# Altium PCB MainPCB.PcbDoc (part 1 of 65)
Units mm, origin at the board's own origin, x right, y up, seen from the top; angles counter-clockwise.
Board outline 92.01 x 92.01 mm, 10 copper layers (Top Layer, PowerPlane2, Mid-Layer 1, MidLayer4, PowerPlane1, Mid-Layer 2, SecondaryGND, Mid-Layer 3, GroundPlane, Bottom Layer); 840 components, 219 nets, 3641 pads, 3367 vias.

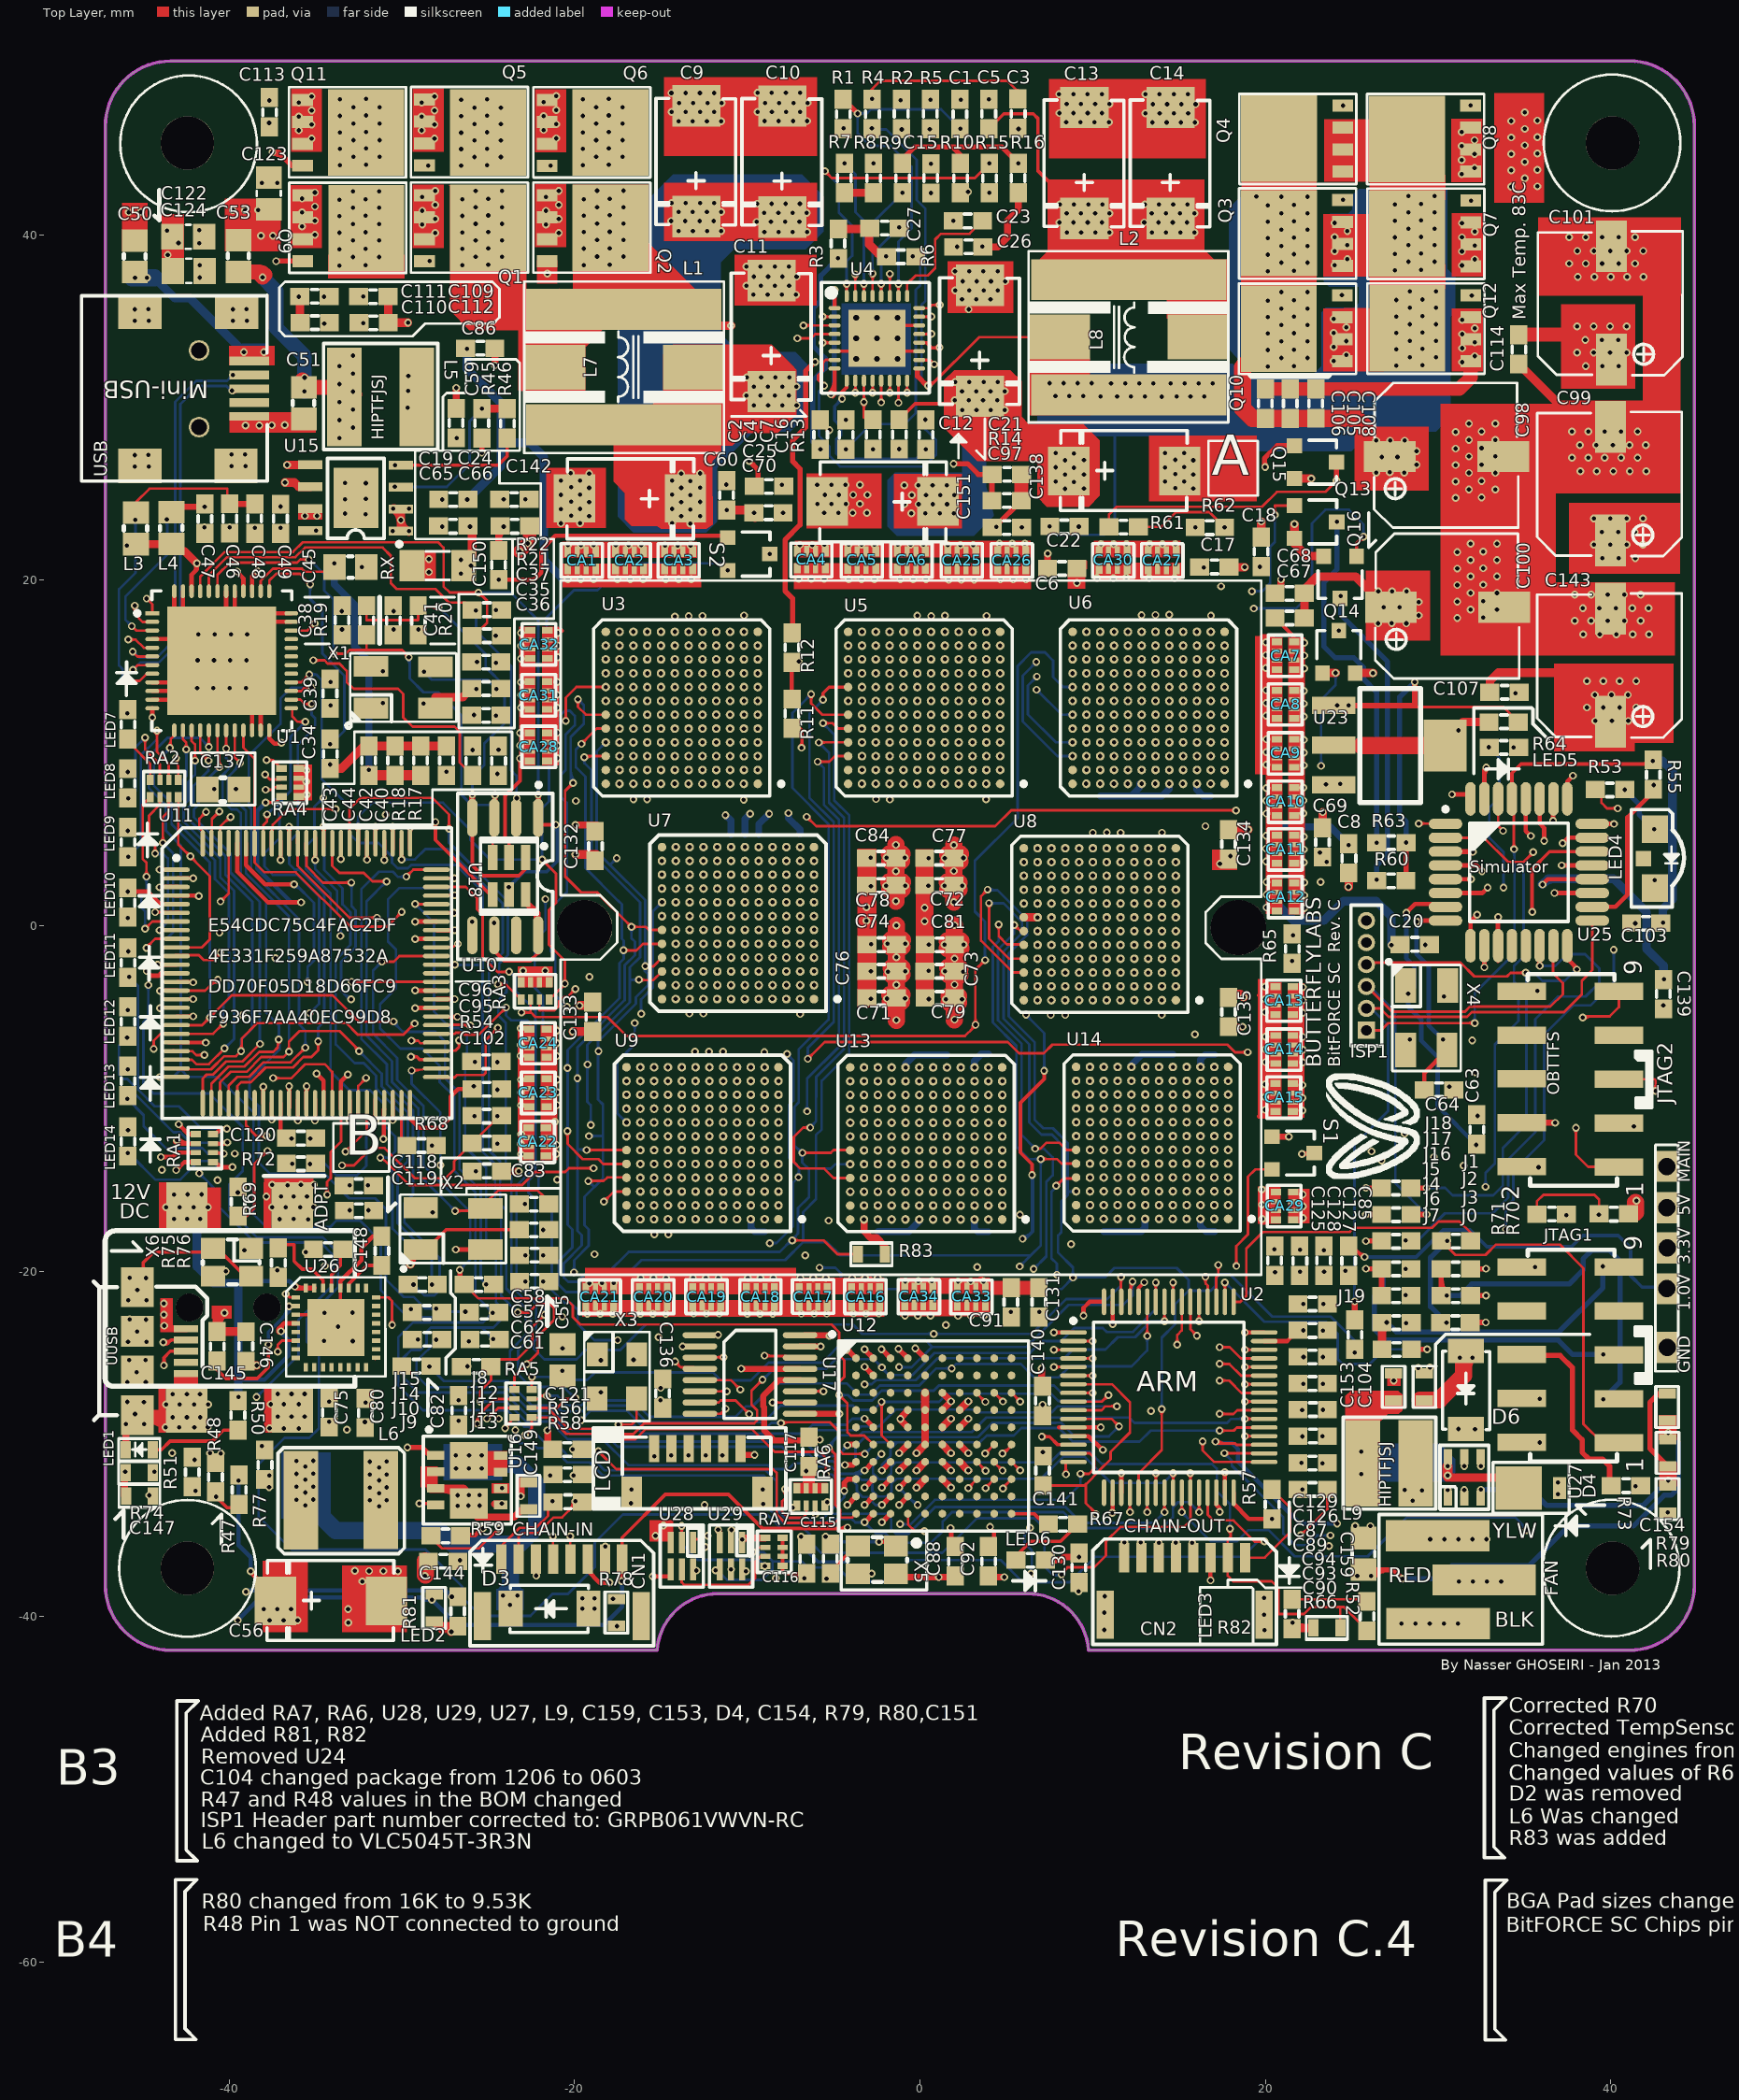
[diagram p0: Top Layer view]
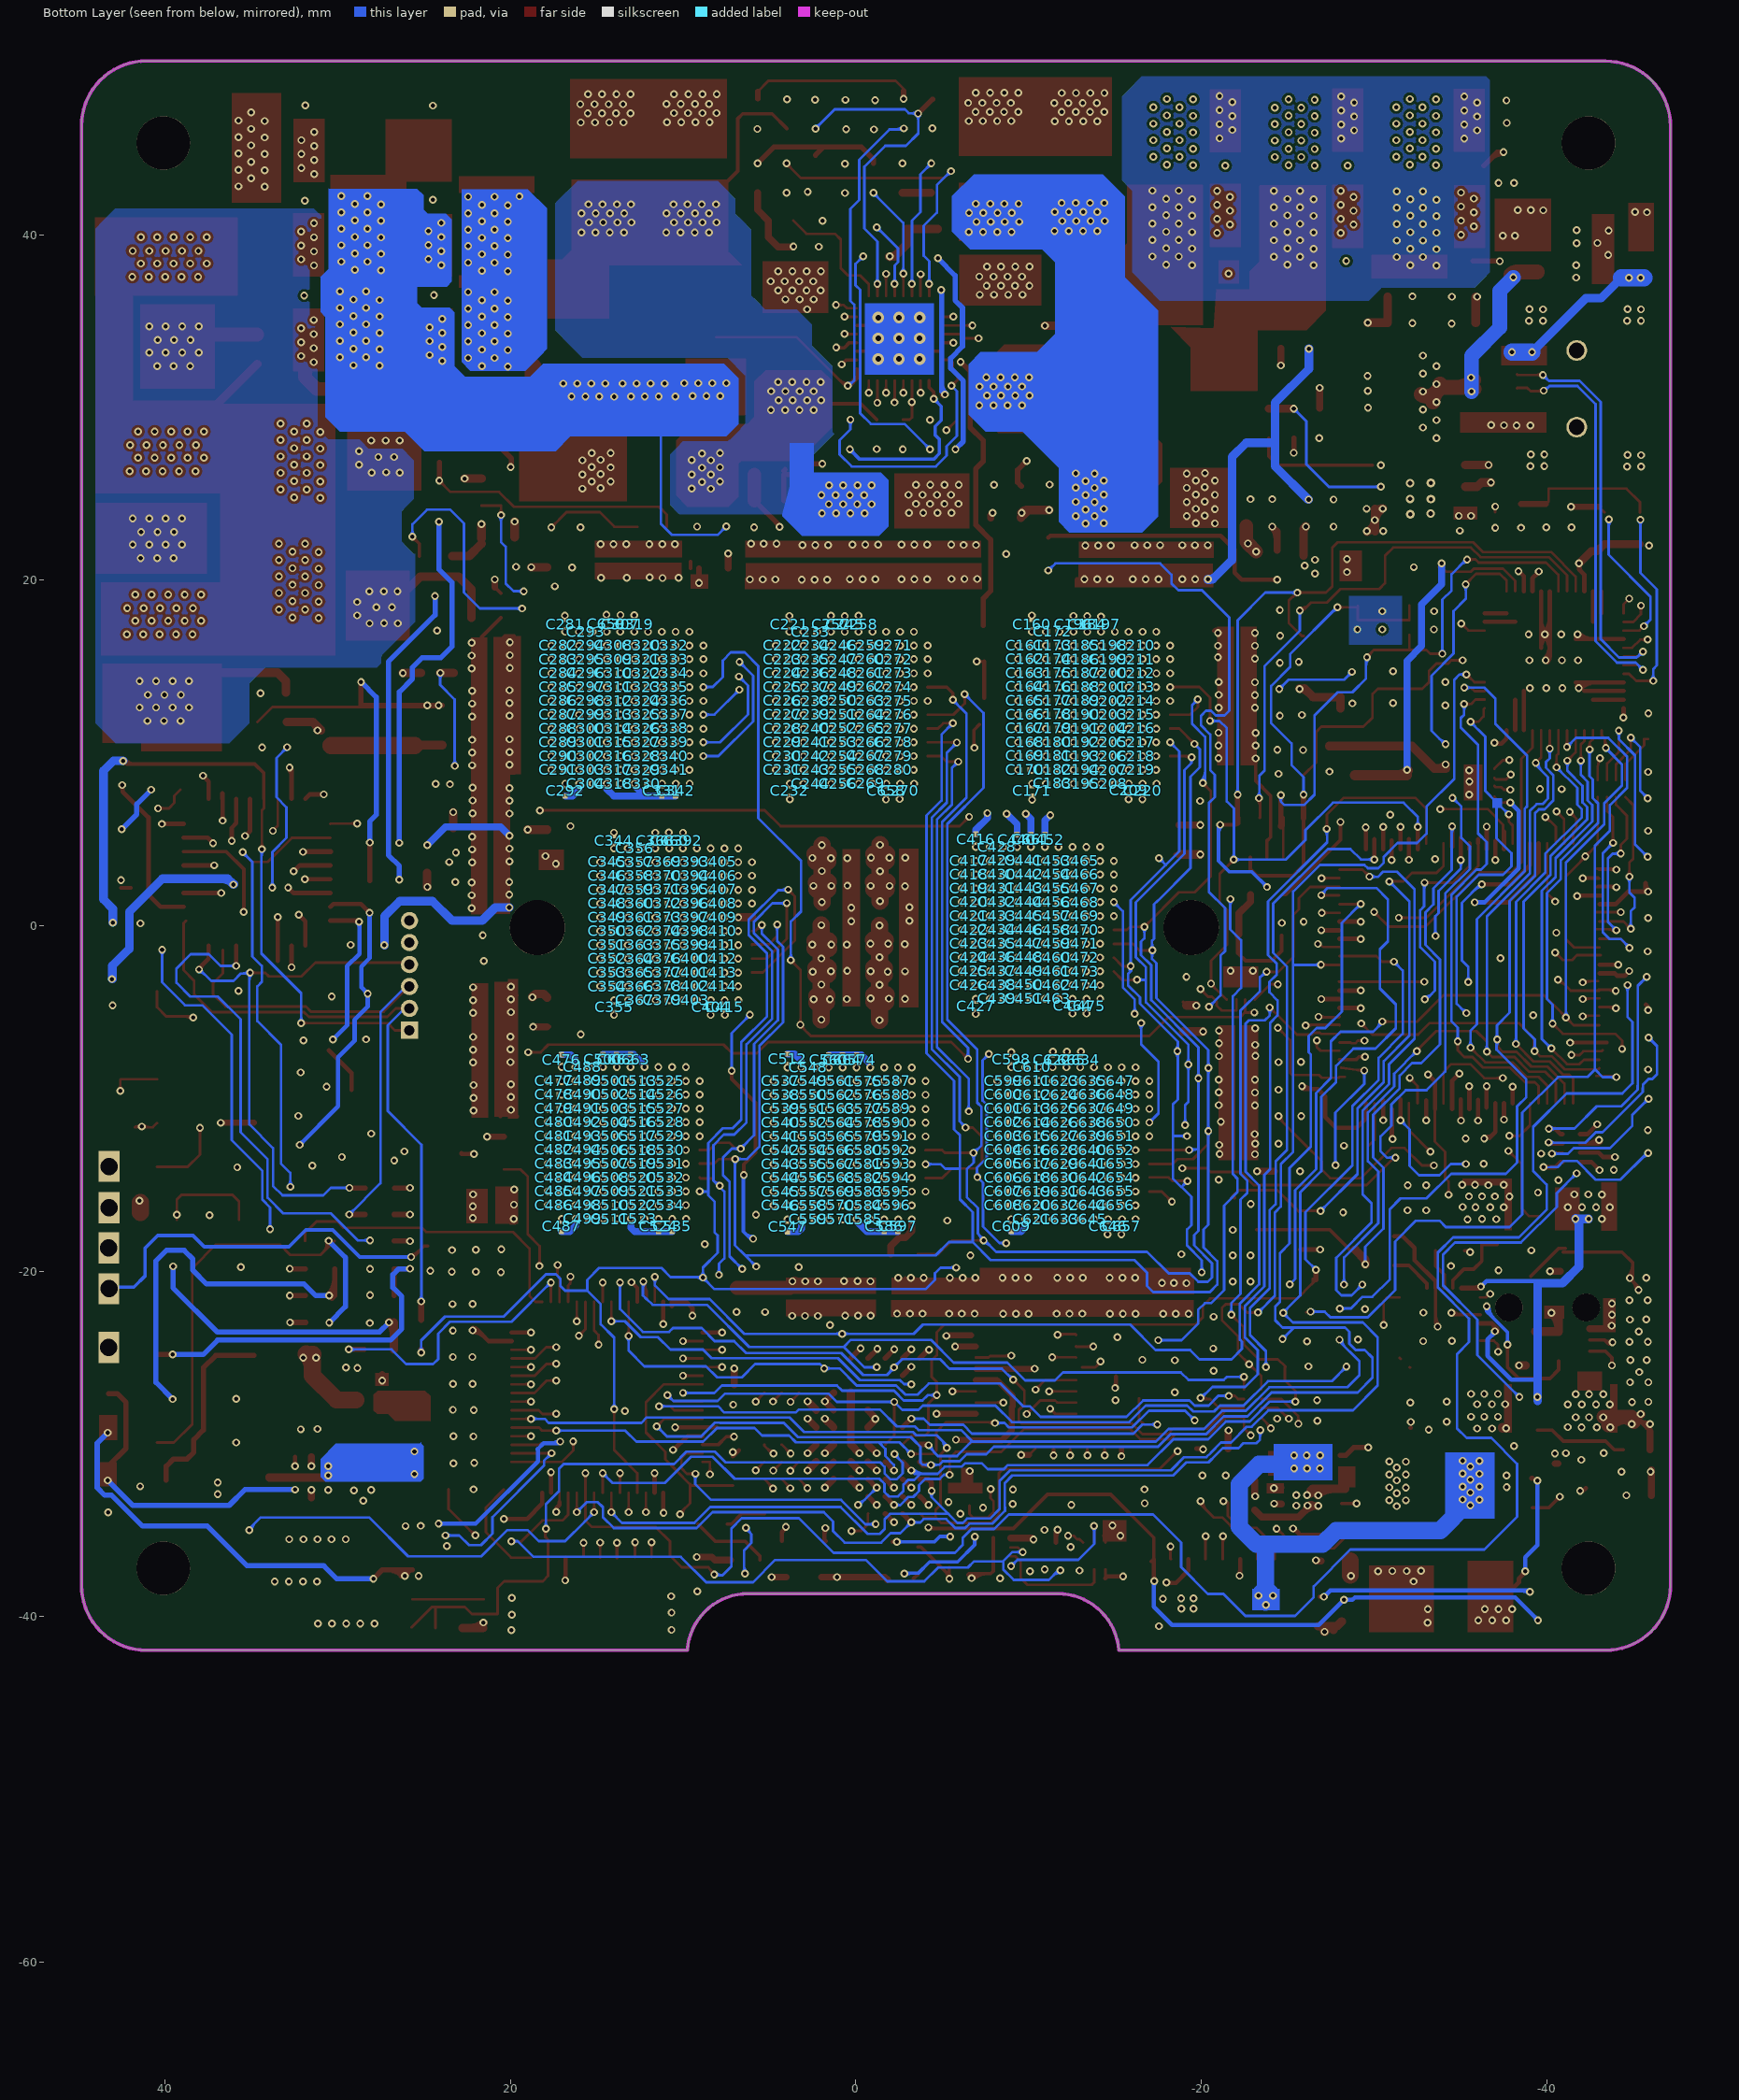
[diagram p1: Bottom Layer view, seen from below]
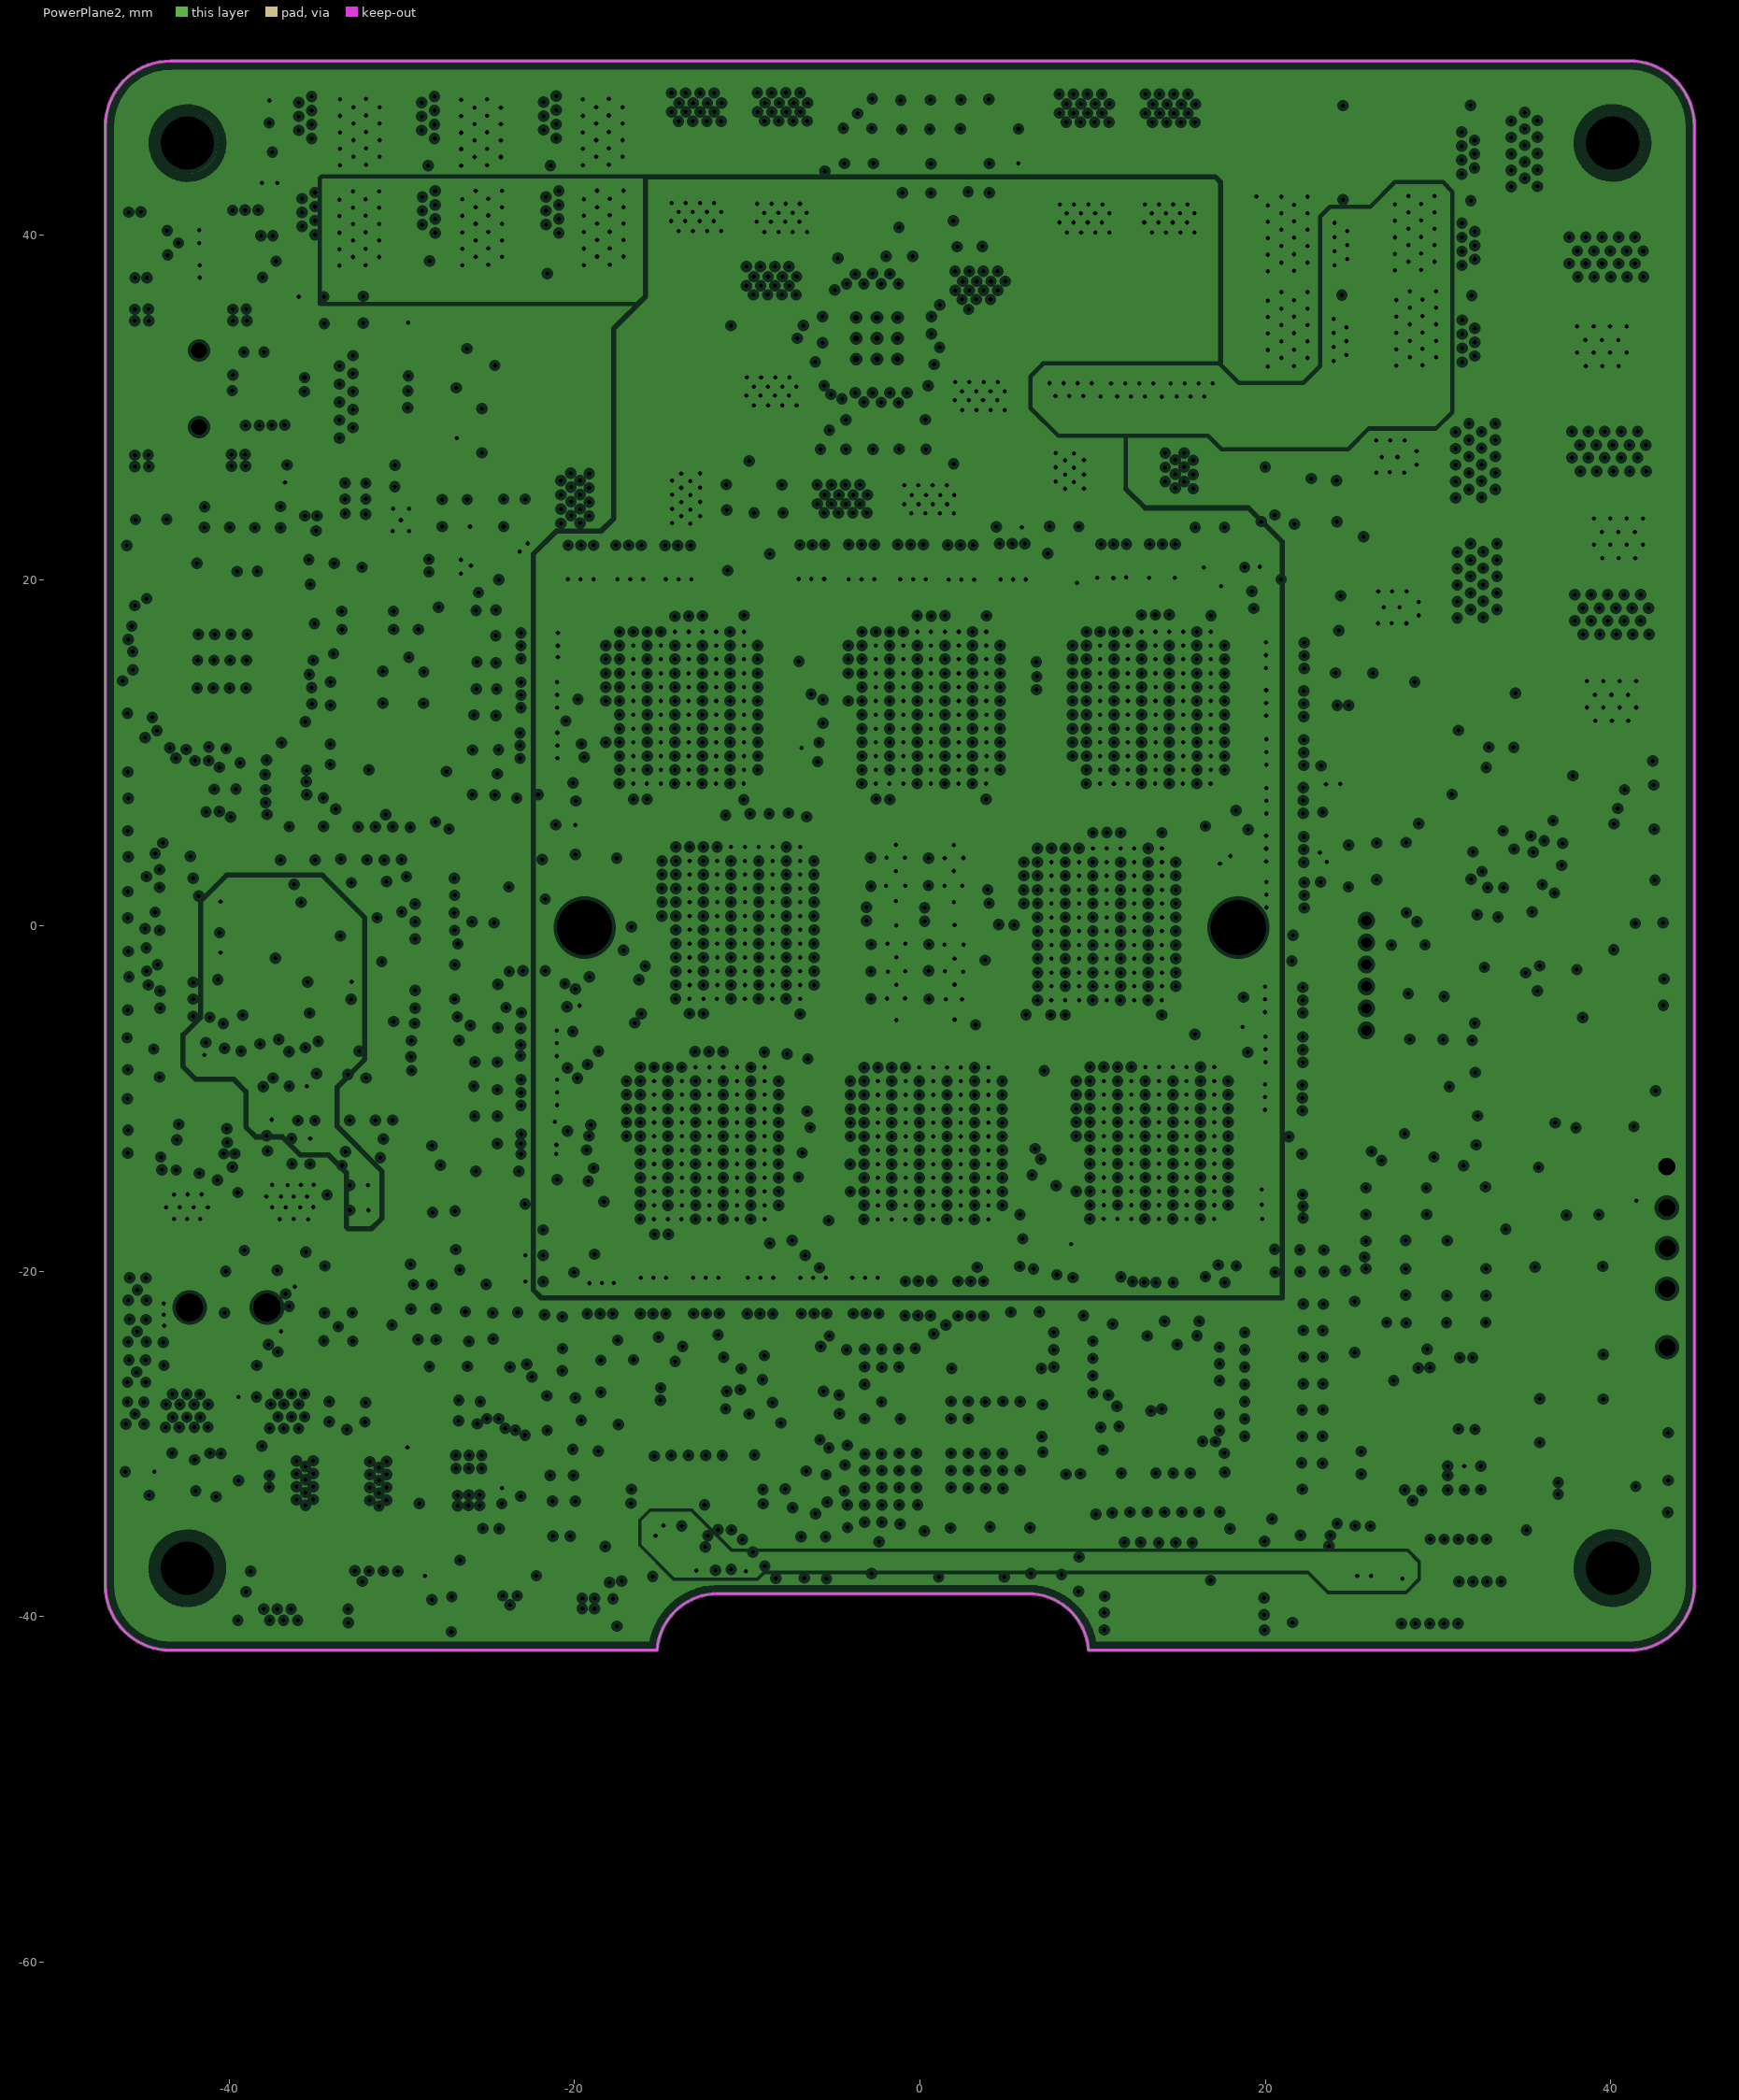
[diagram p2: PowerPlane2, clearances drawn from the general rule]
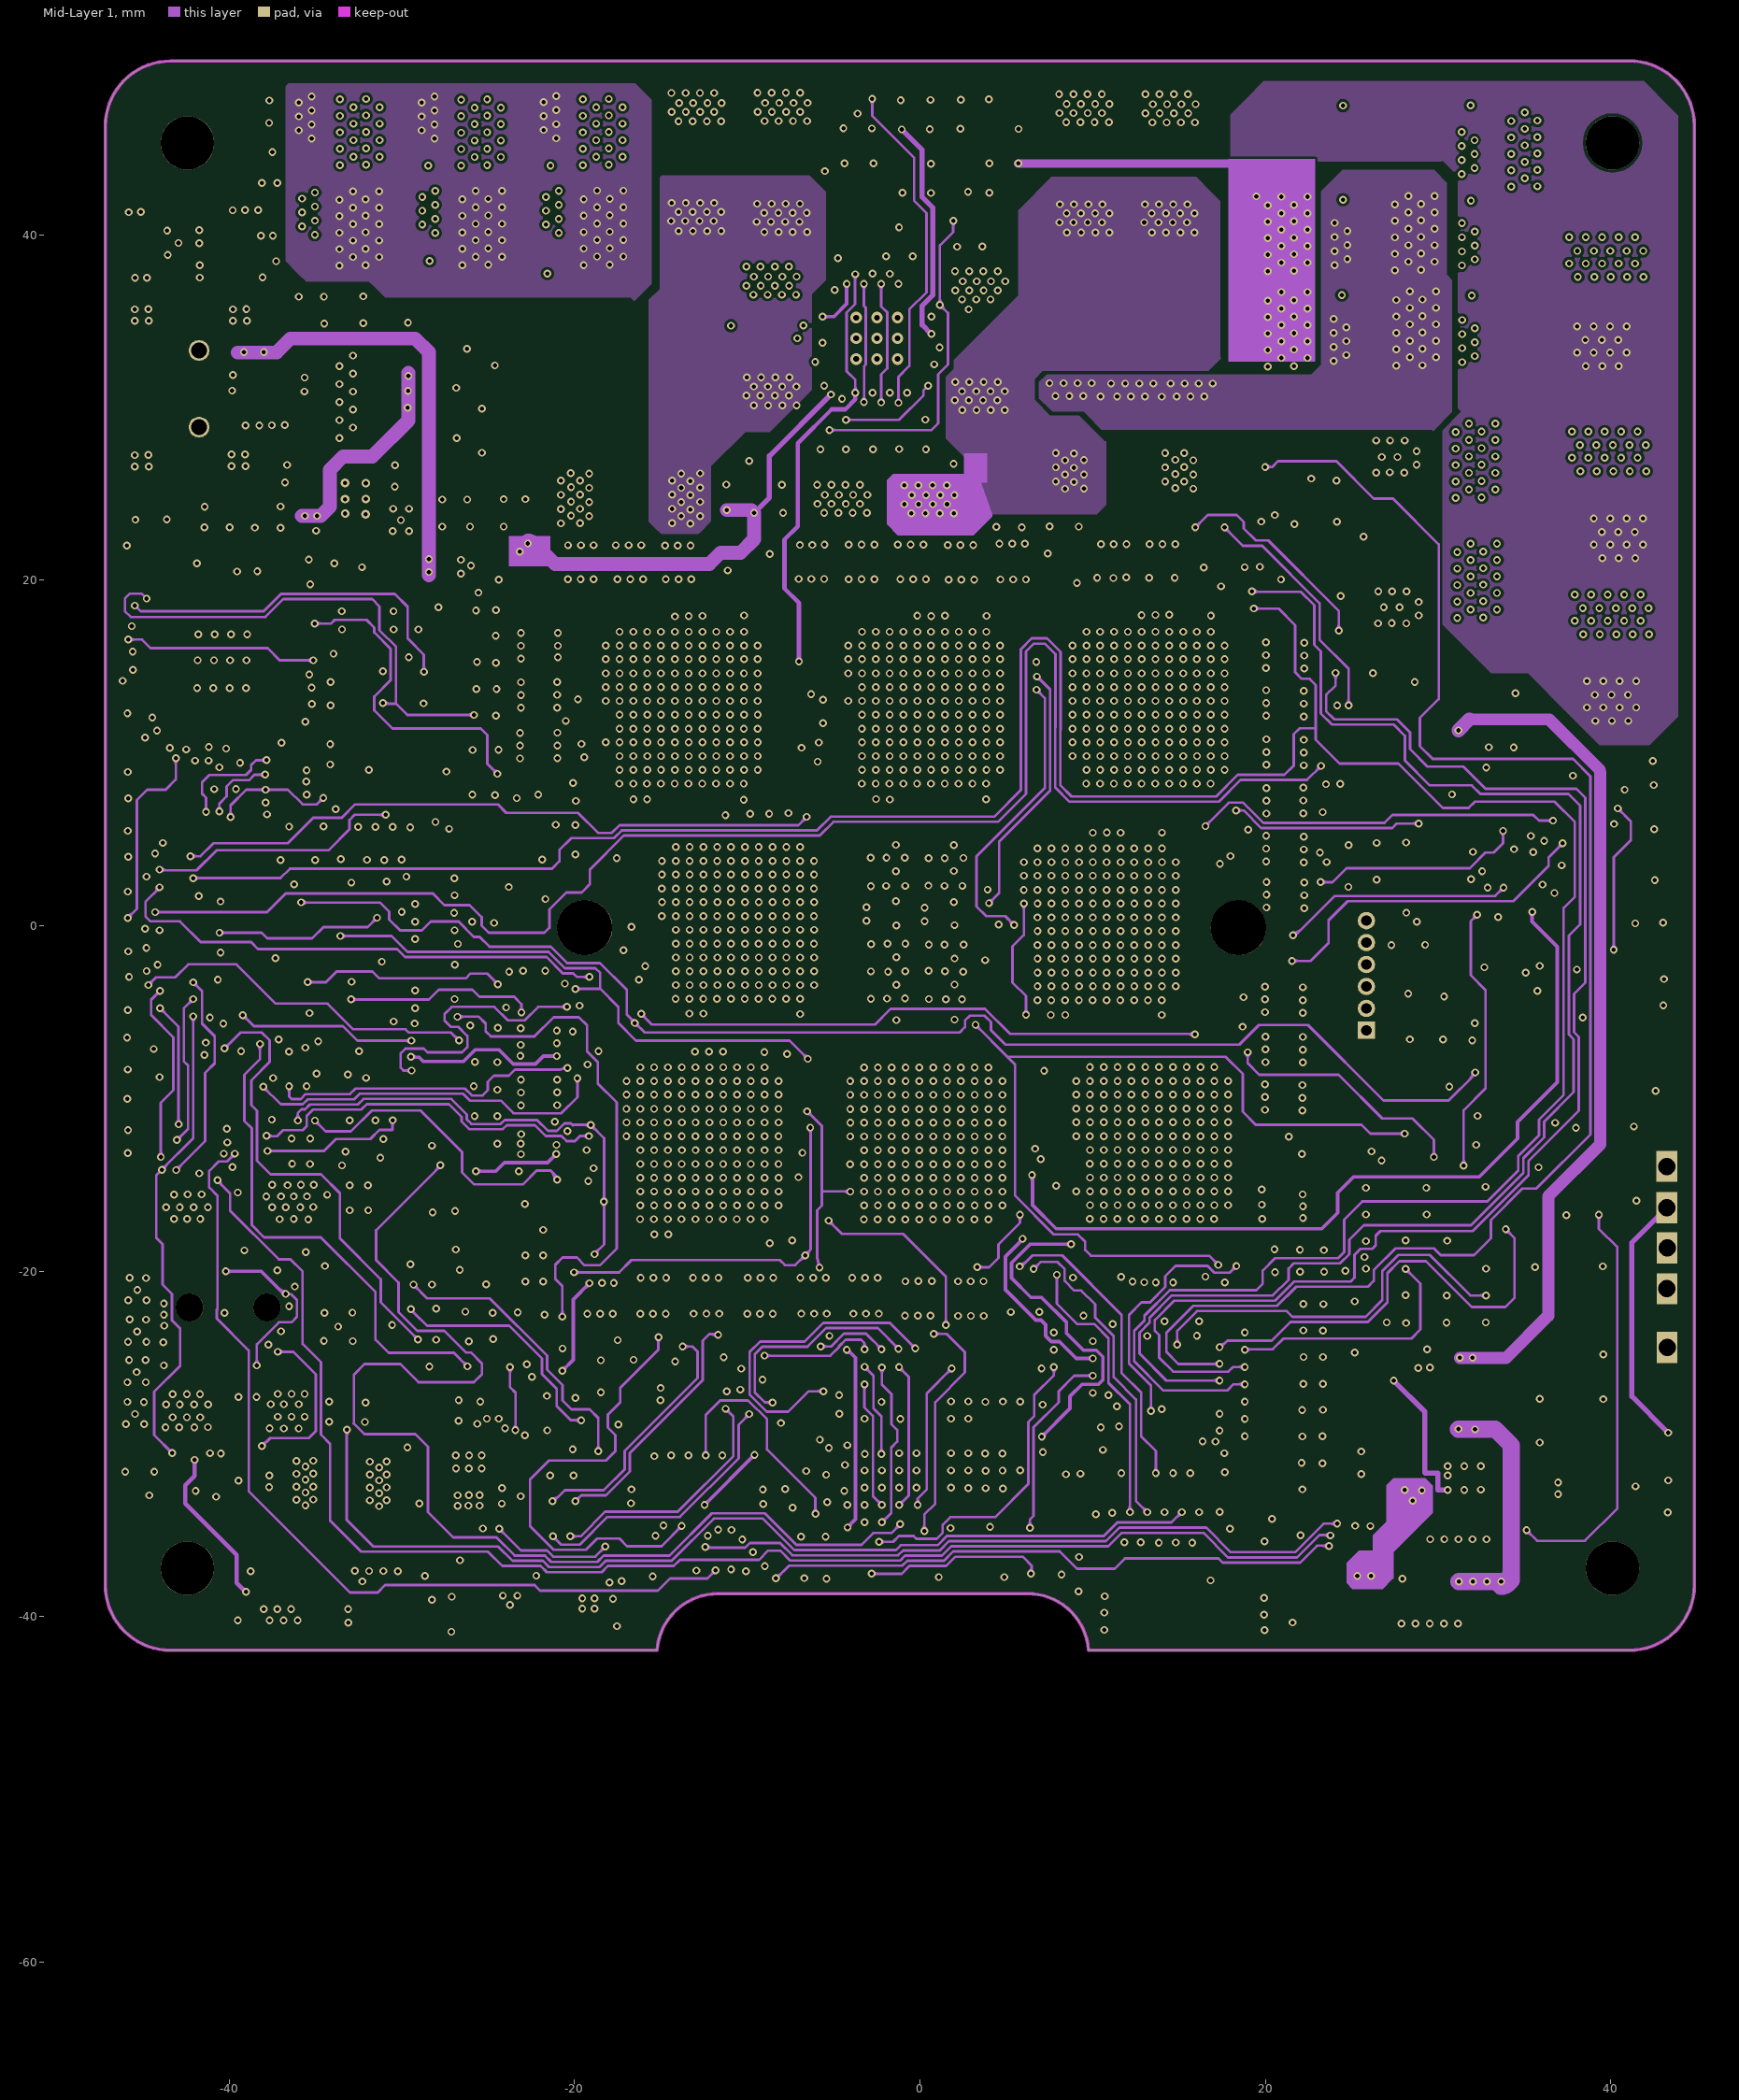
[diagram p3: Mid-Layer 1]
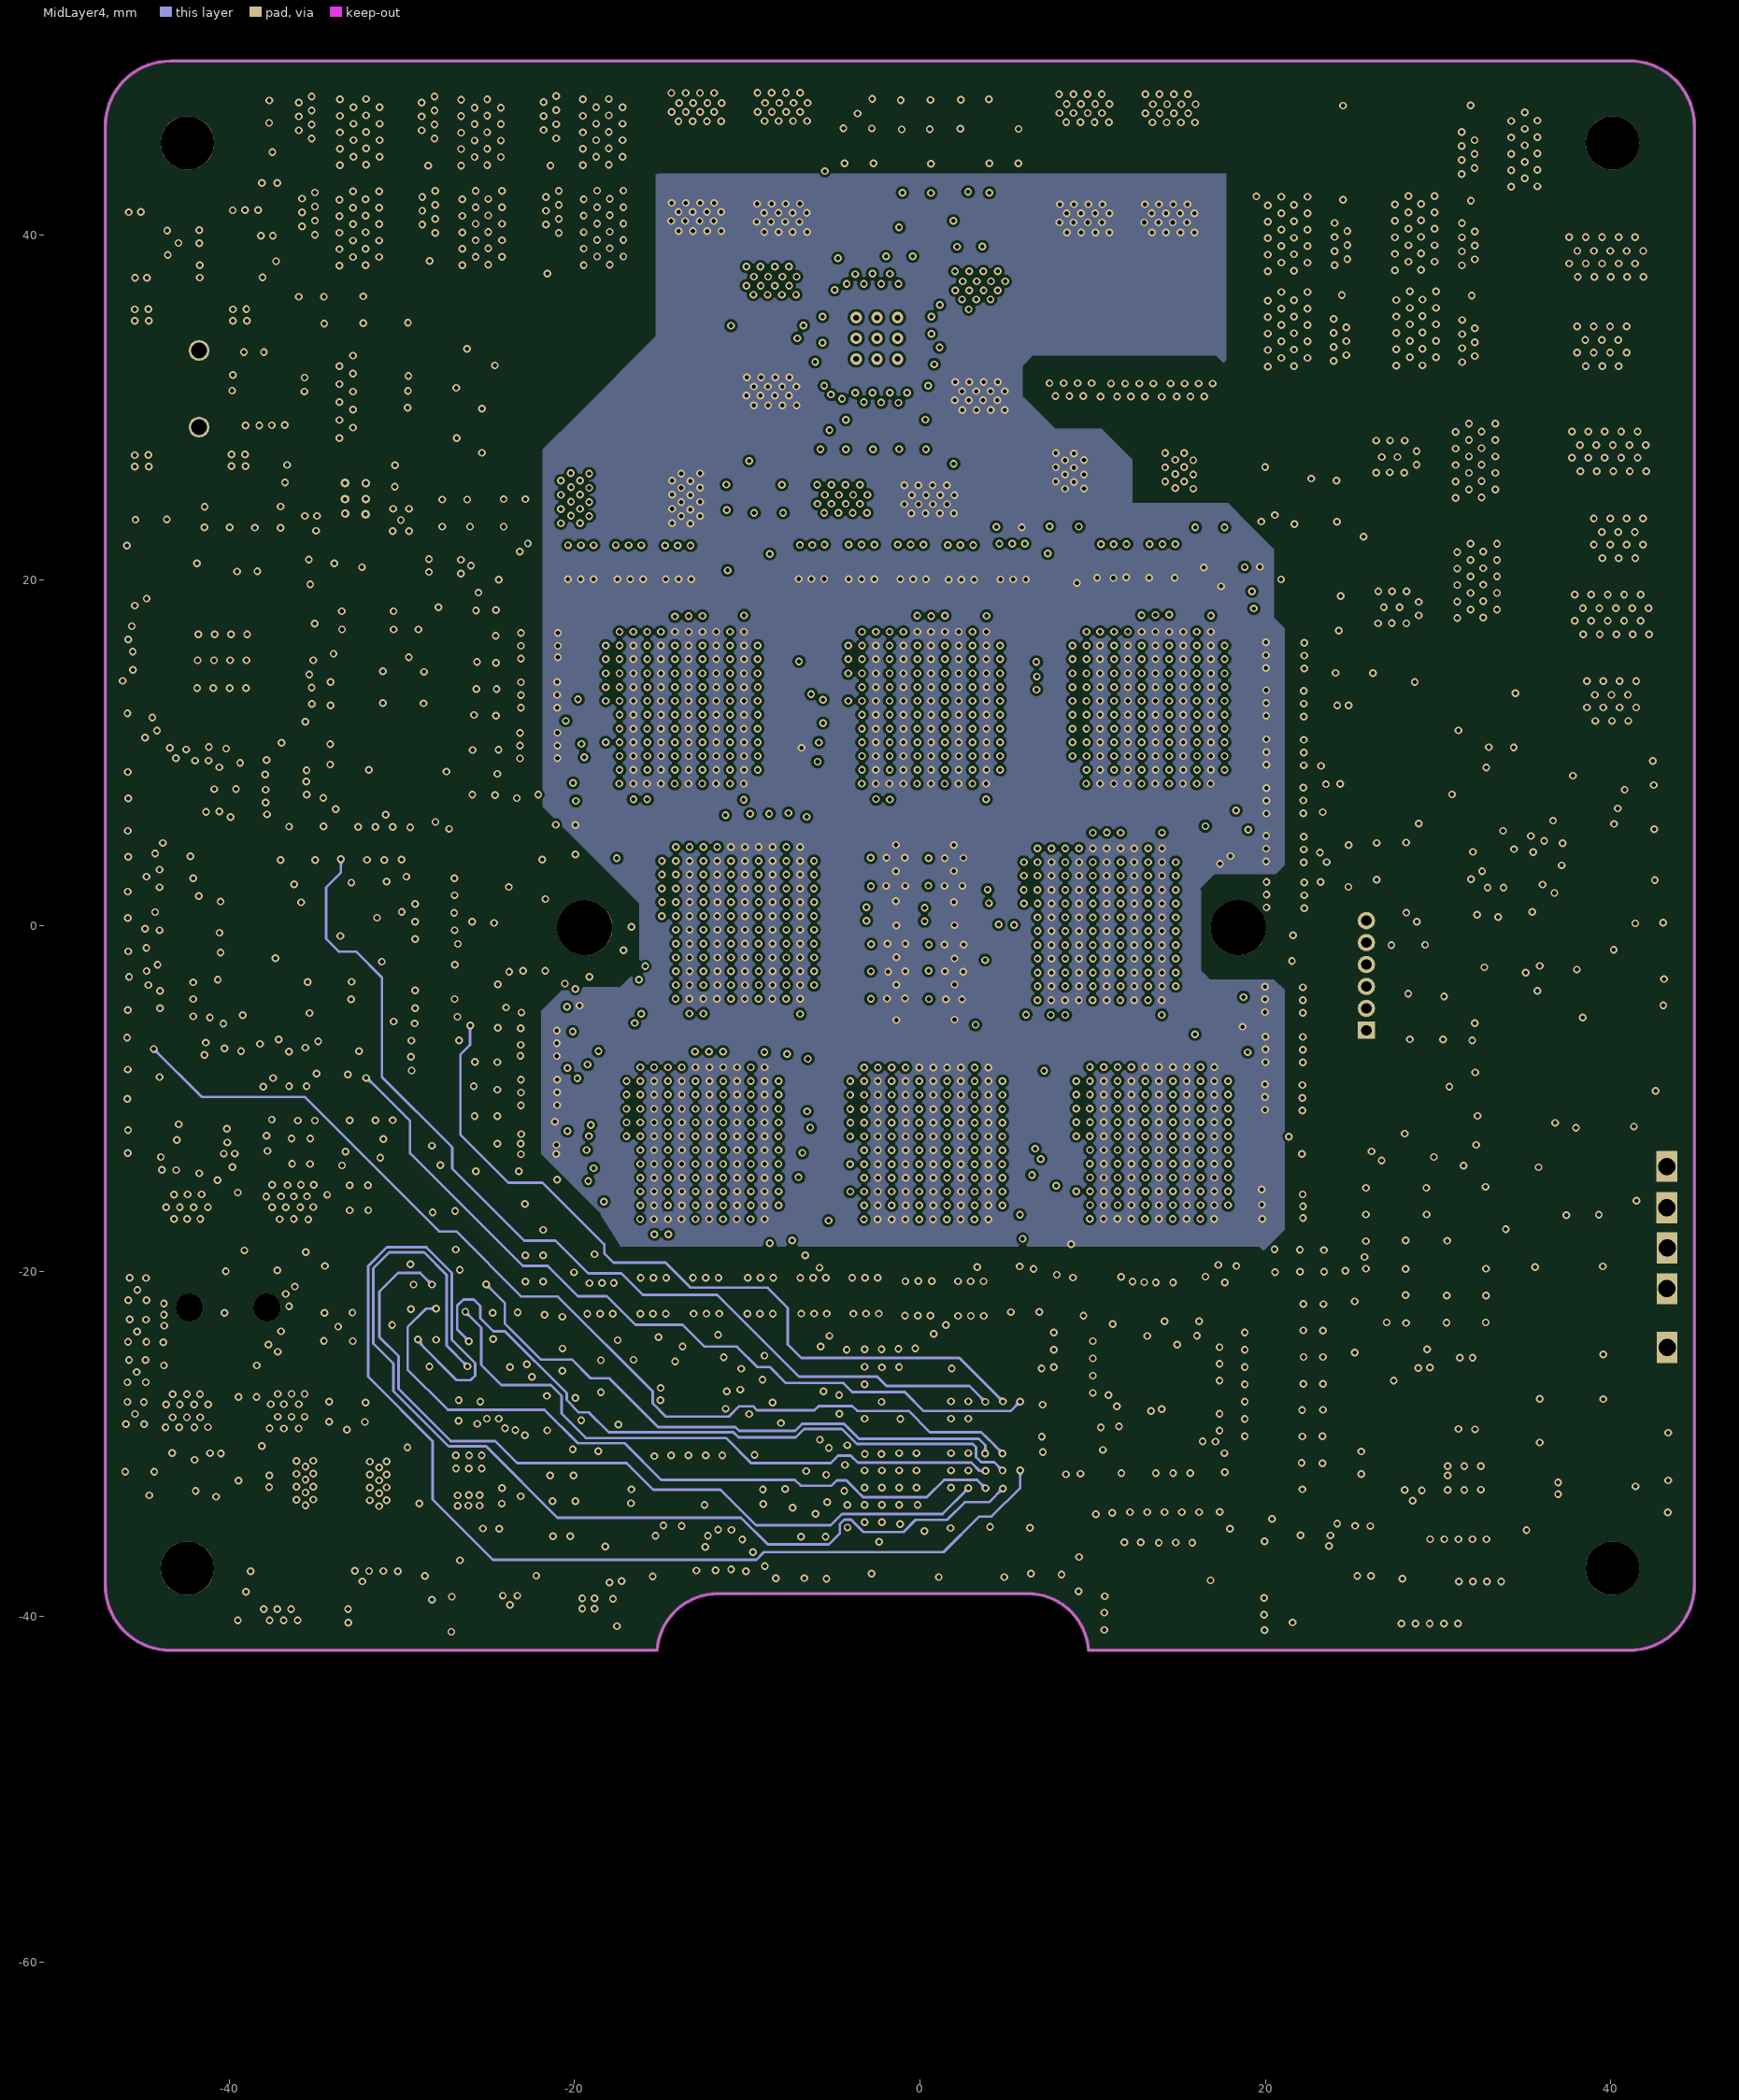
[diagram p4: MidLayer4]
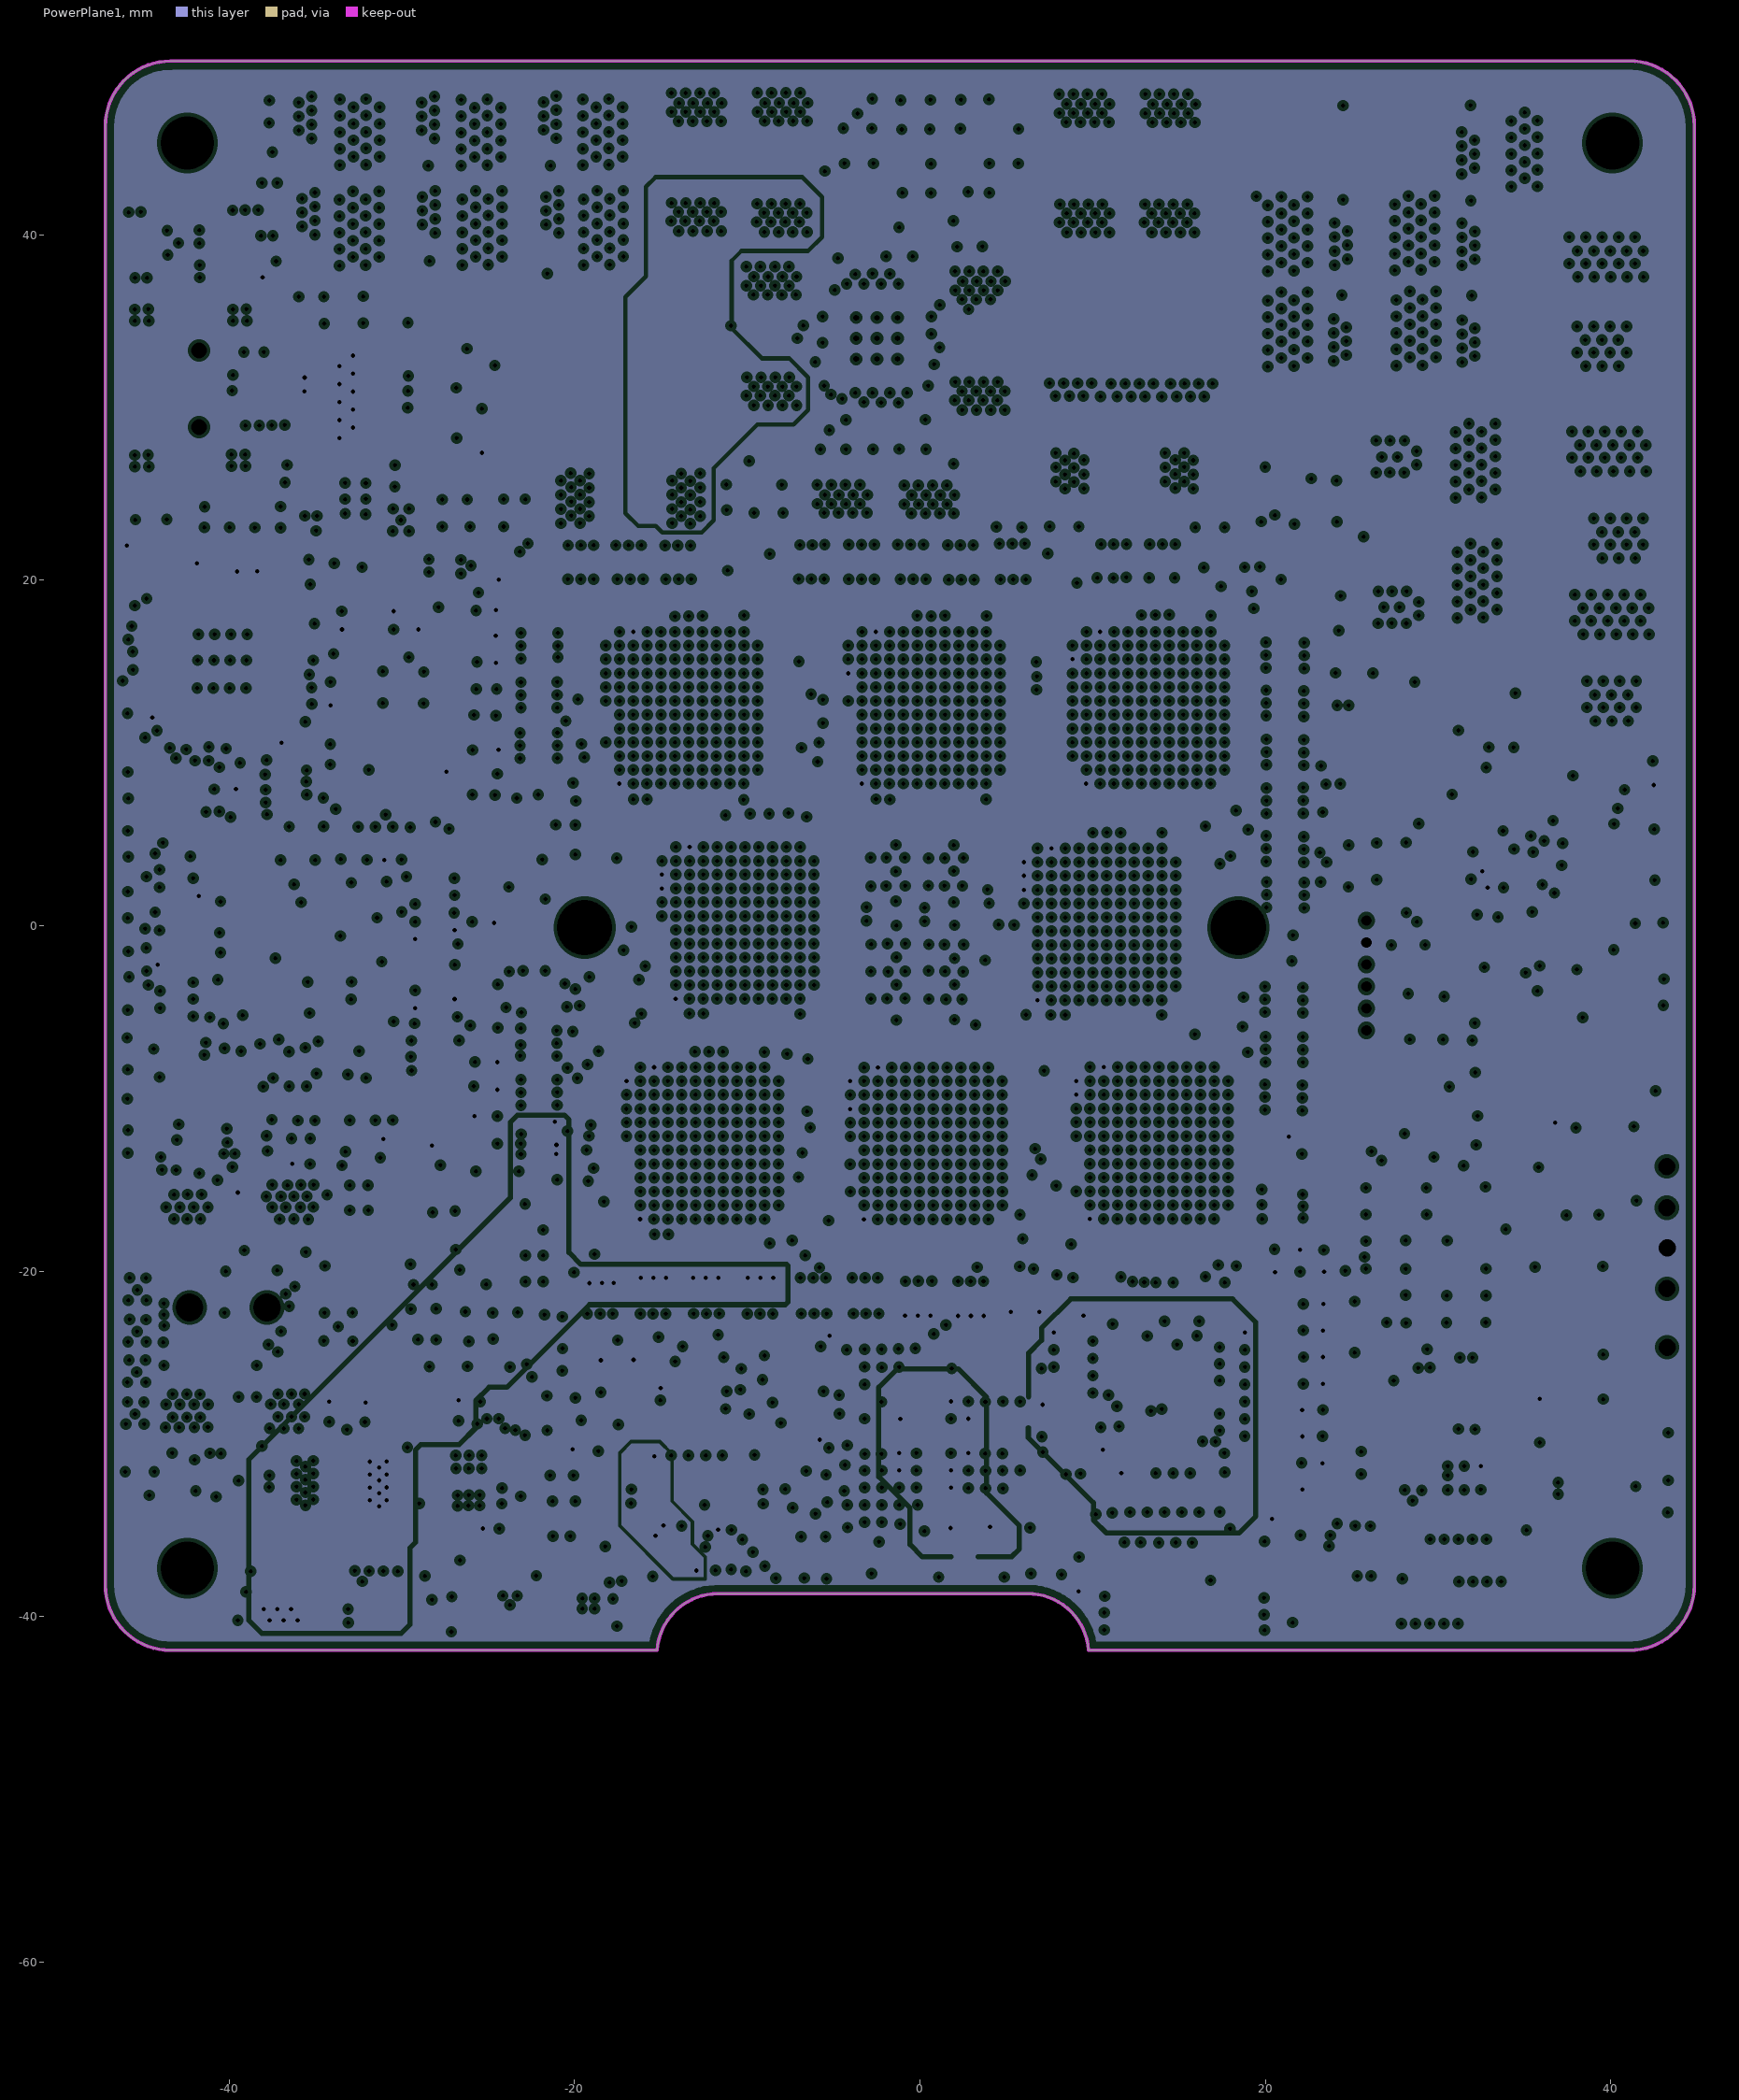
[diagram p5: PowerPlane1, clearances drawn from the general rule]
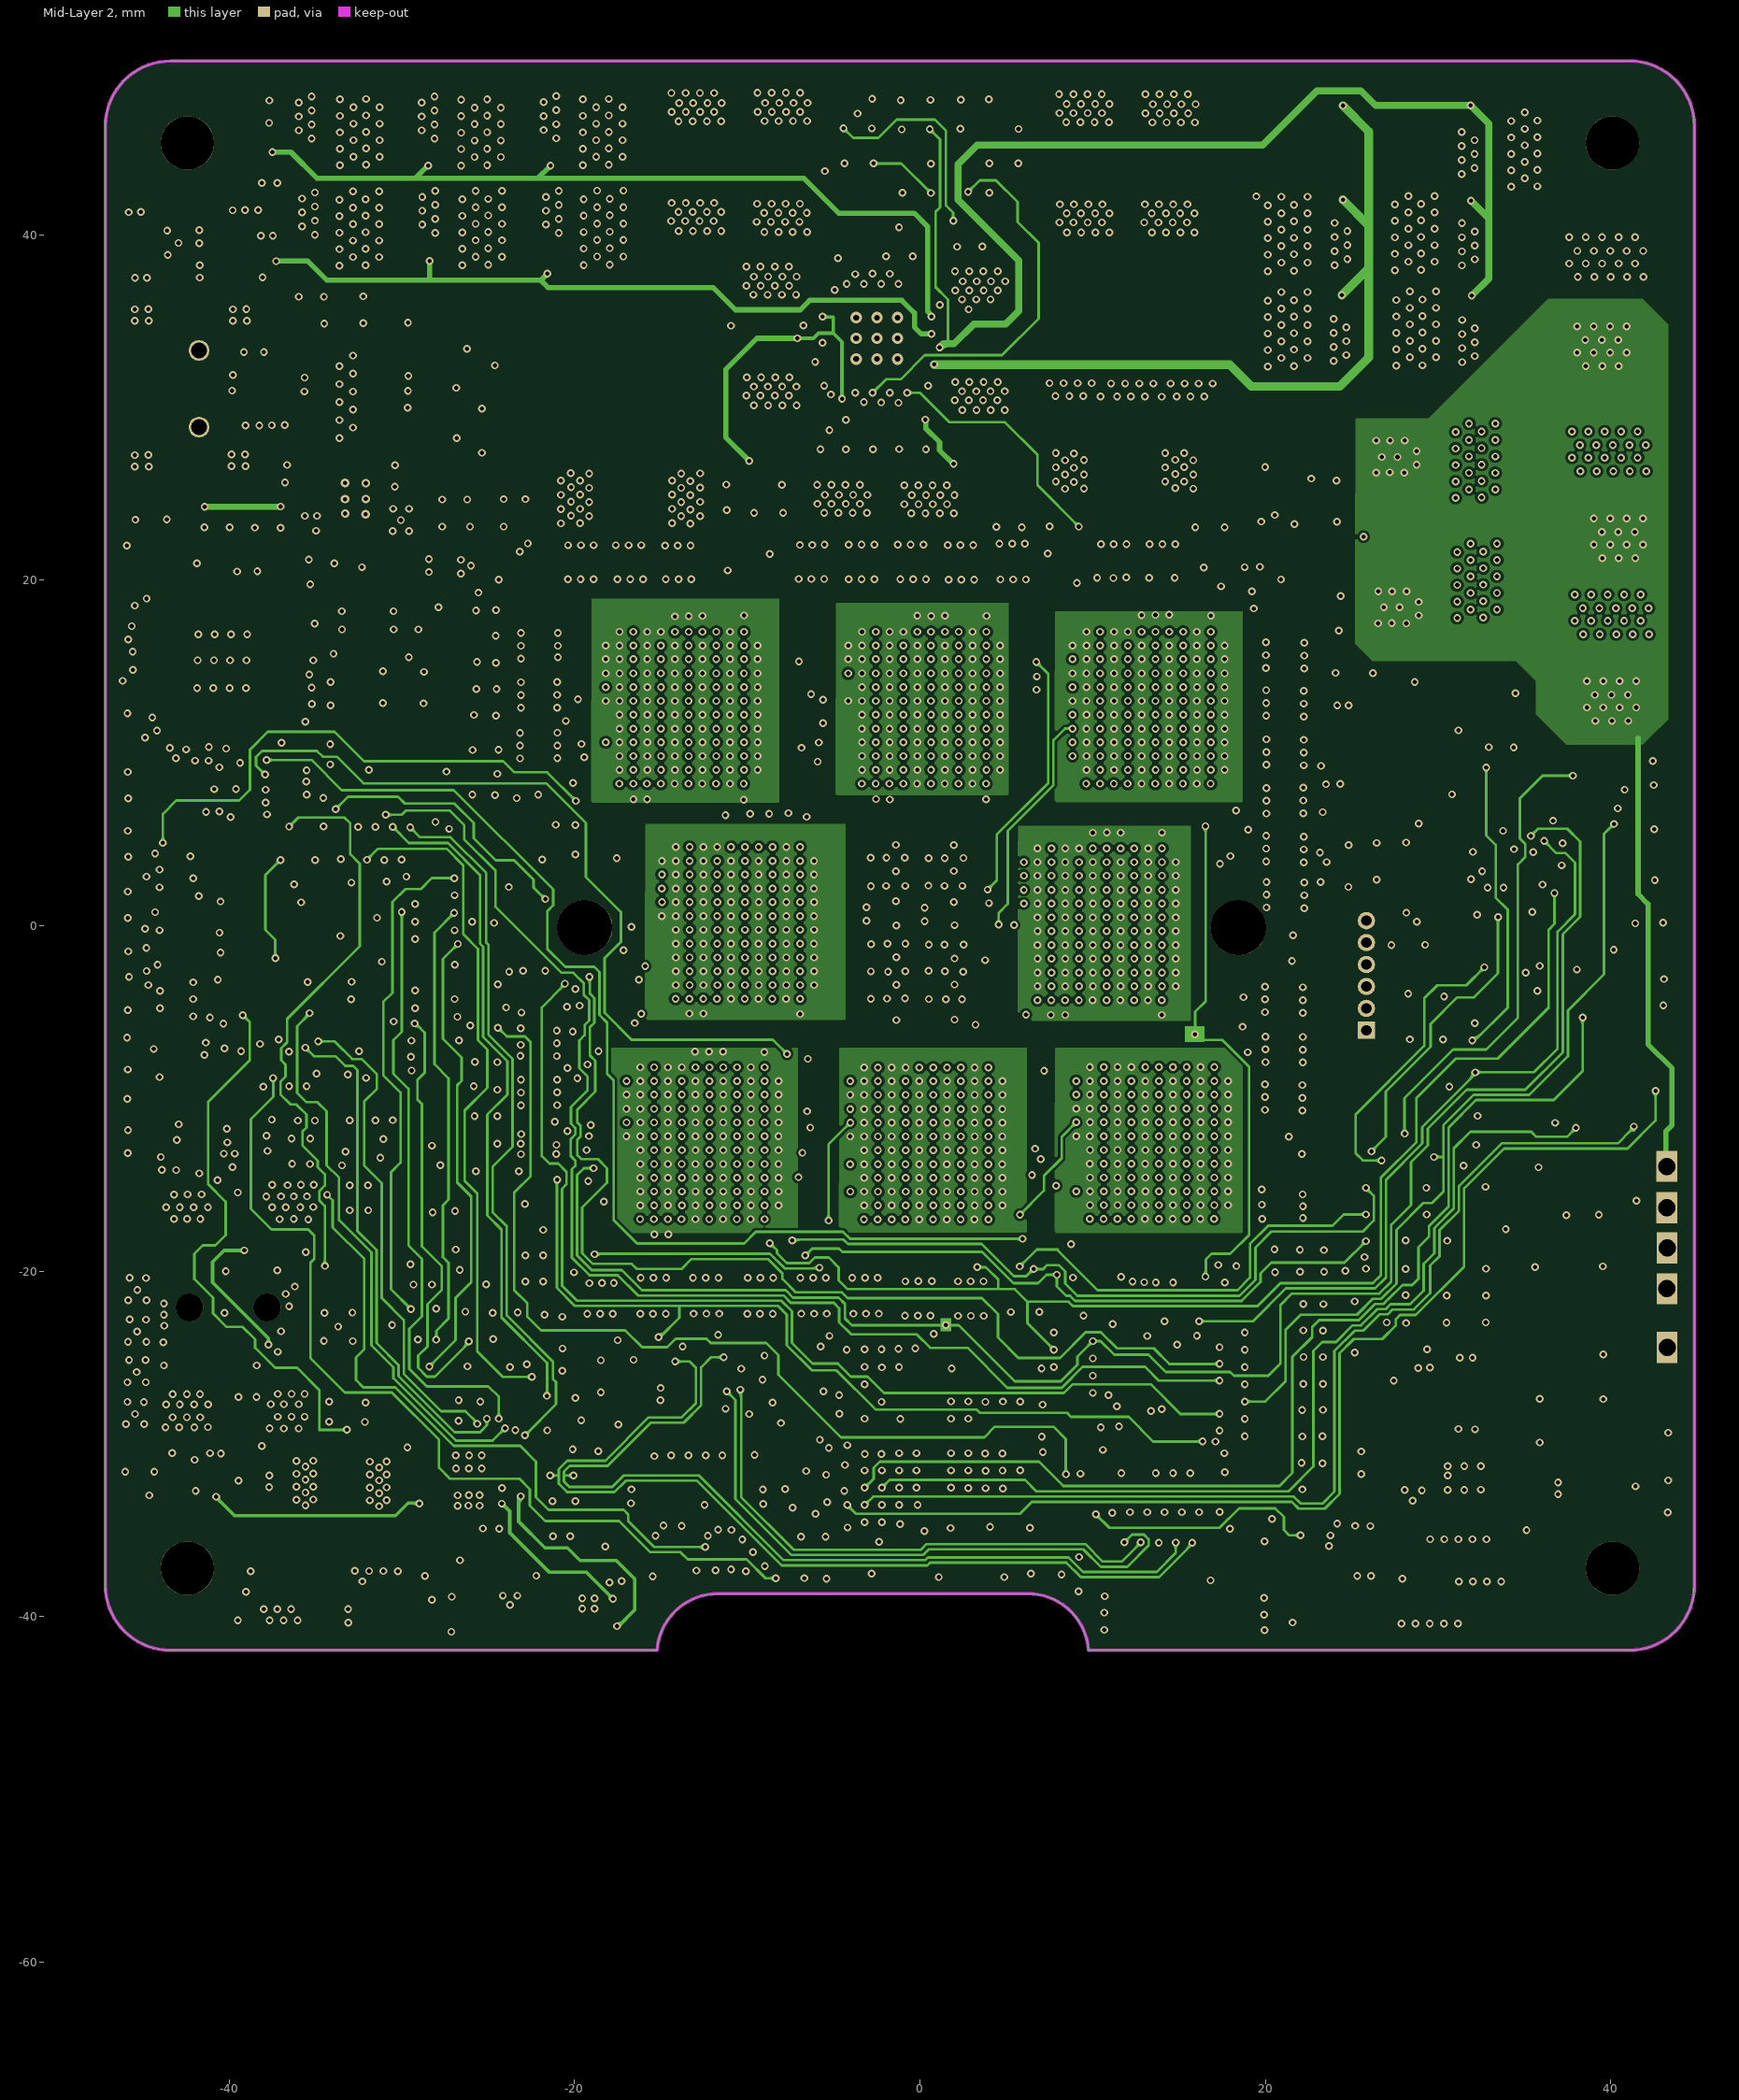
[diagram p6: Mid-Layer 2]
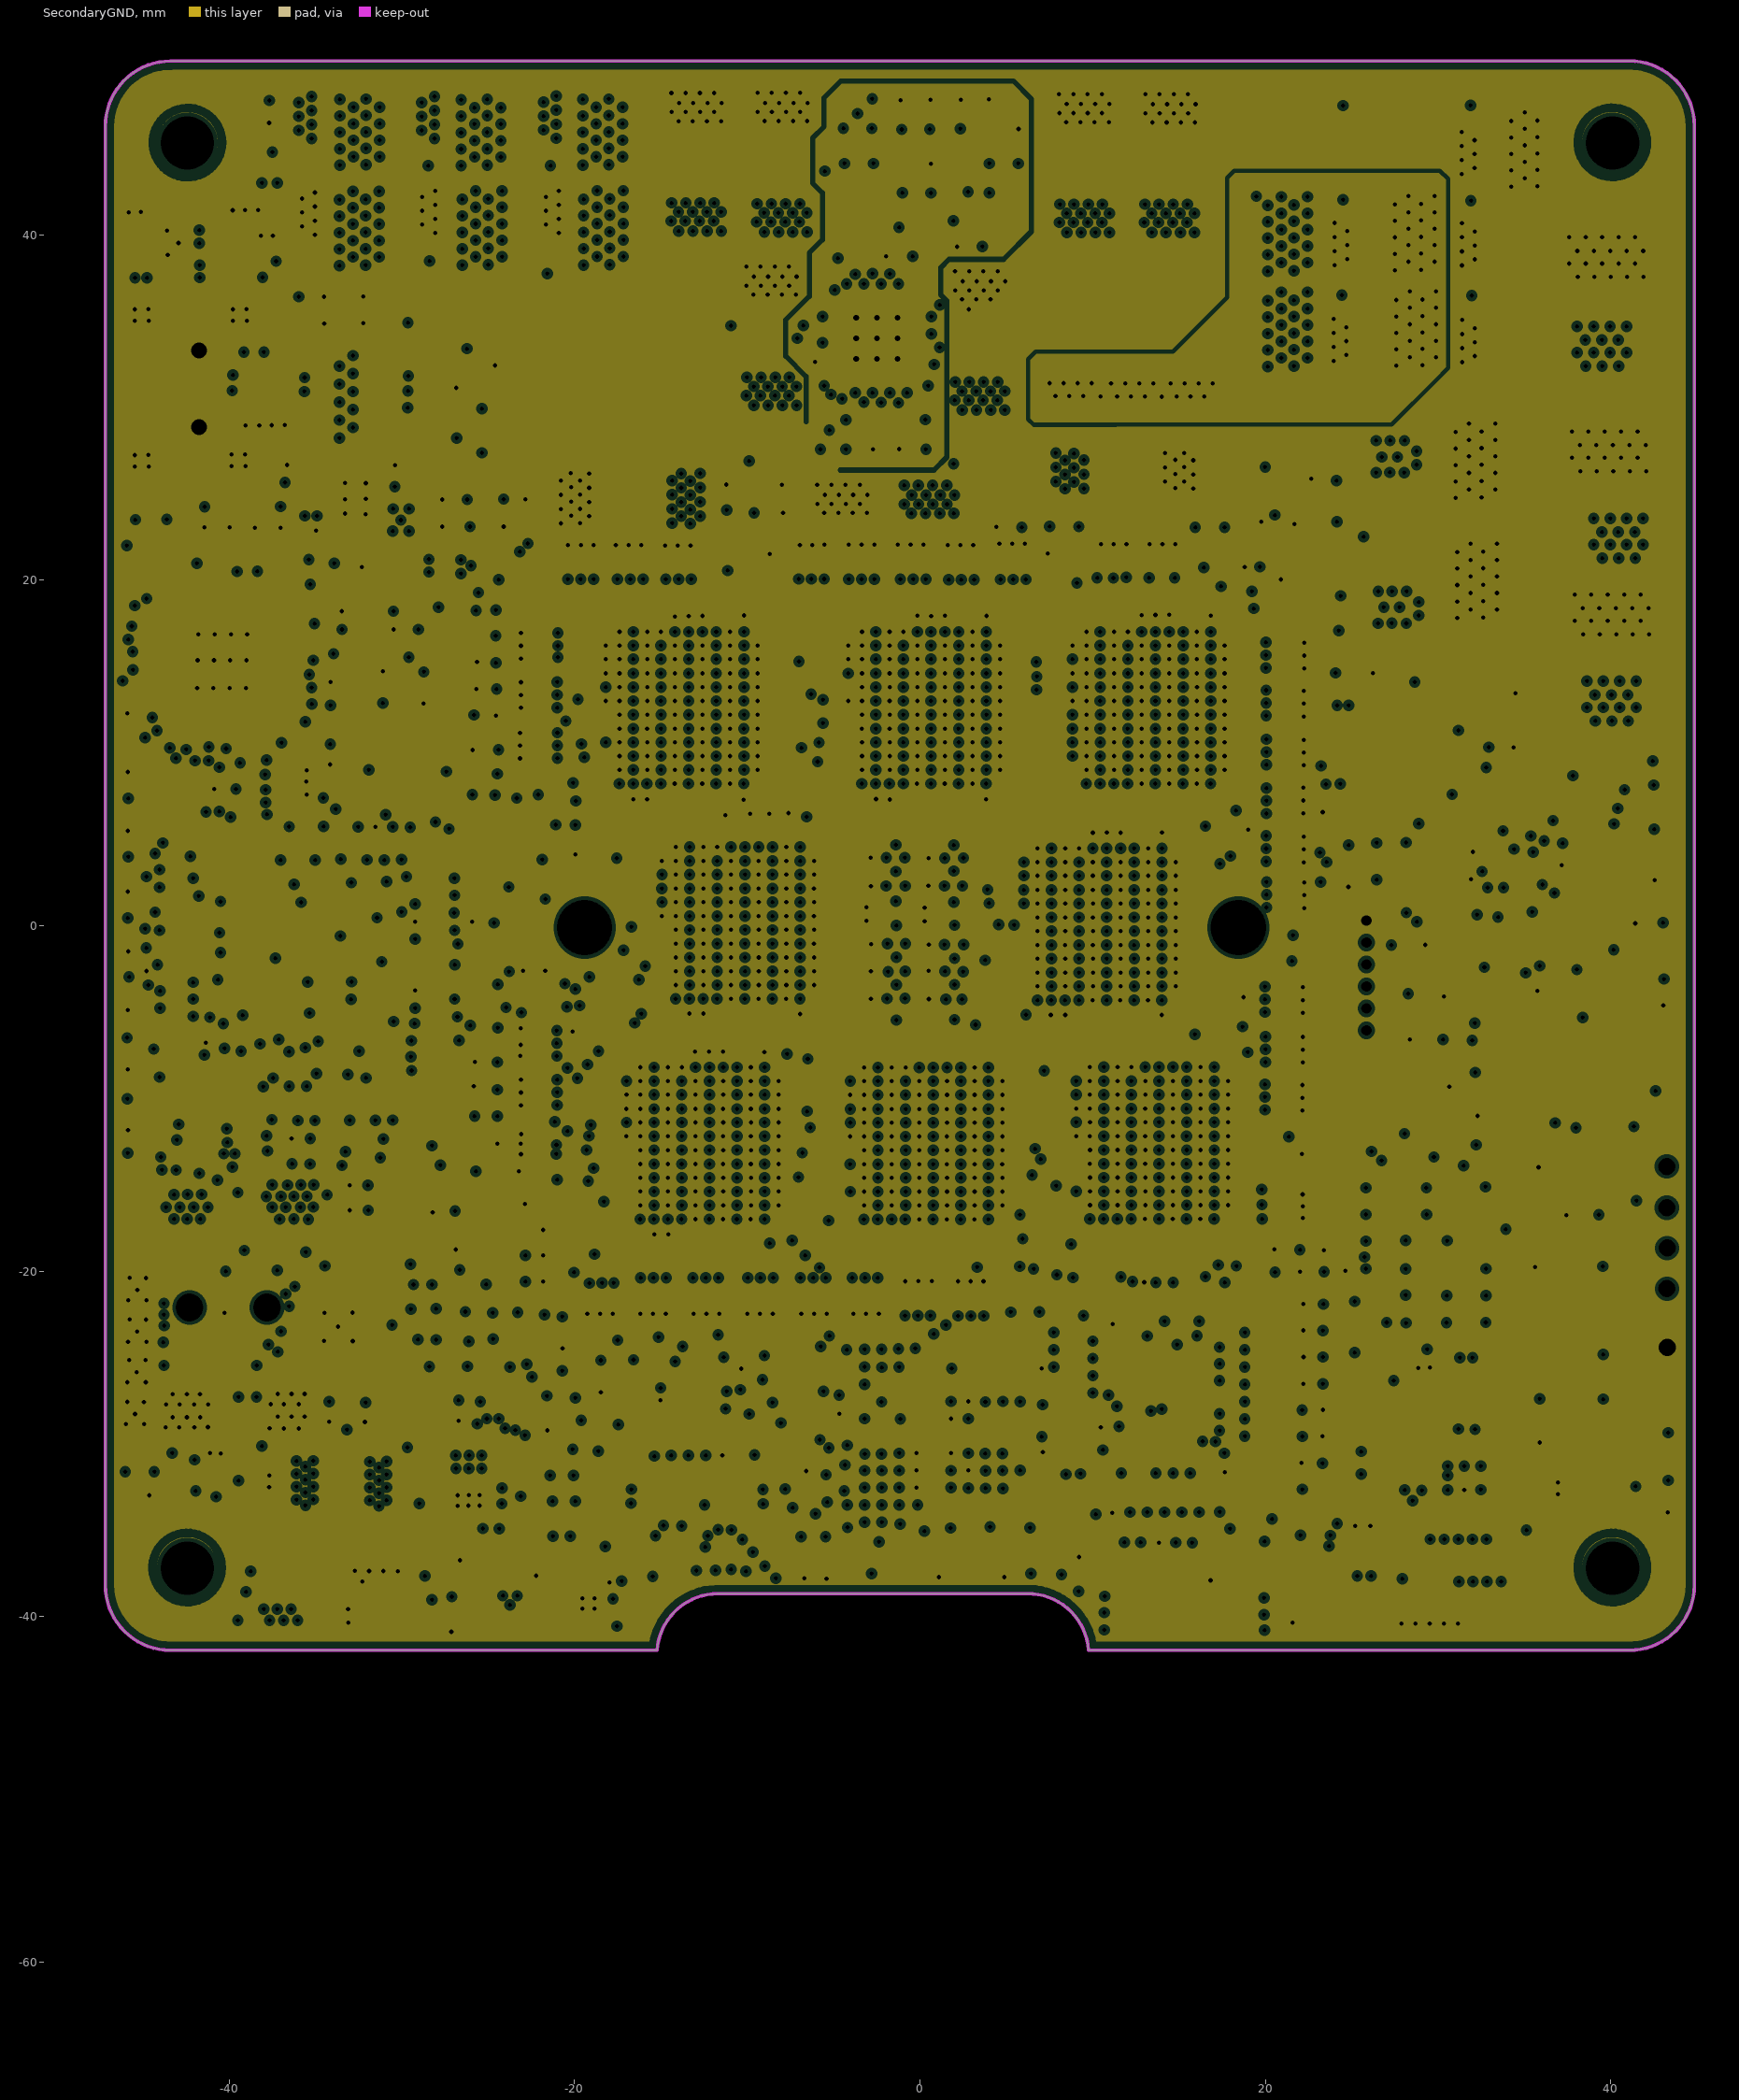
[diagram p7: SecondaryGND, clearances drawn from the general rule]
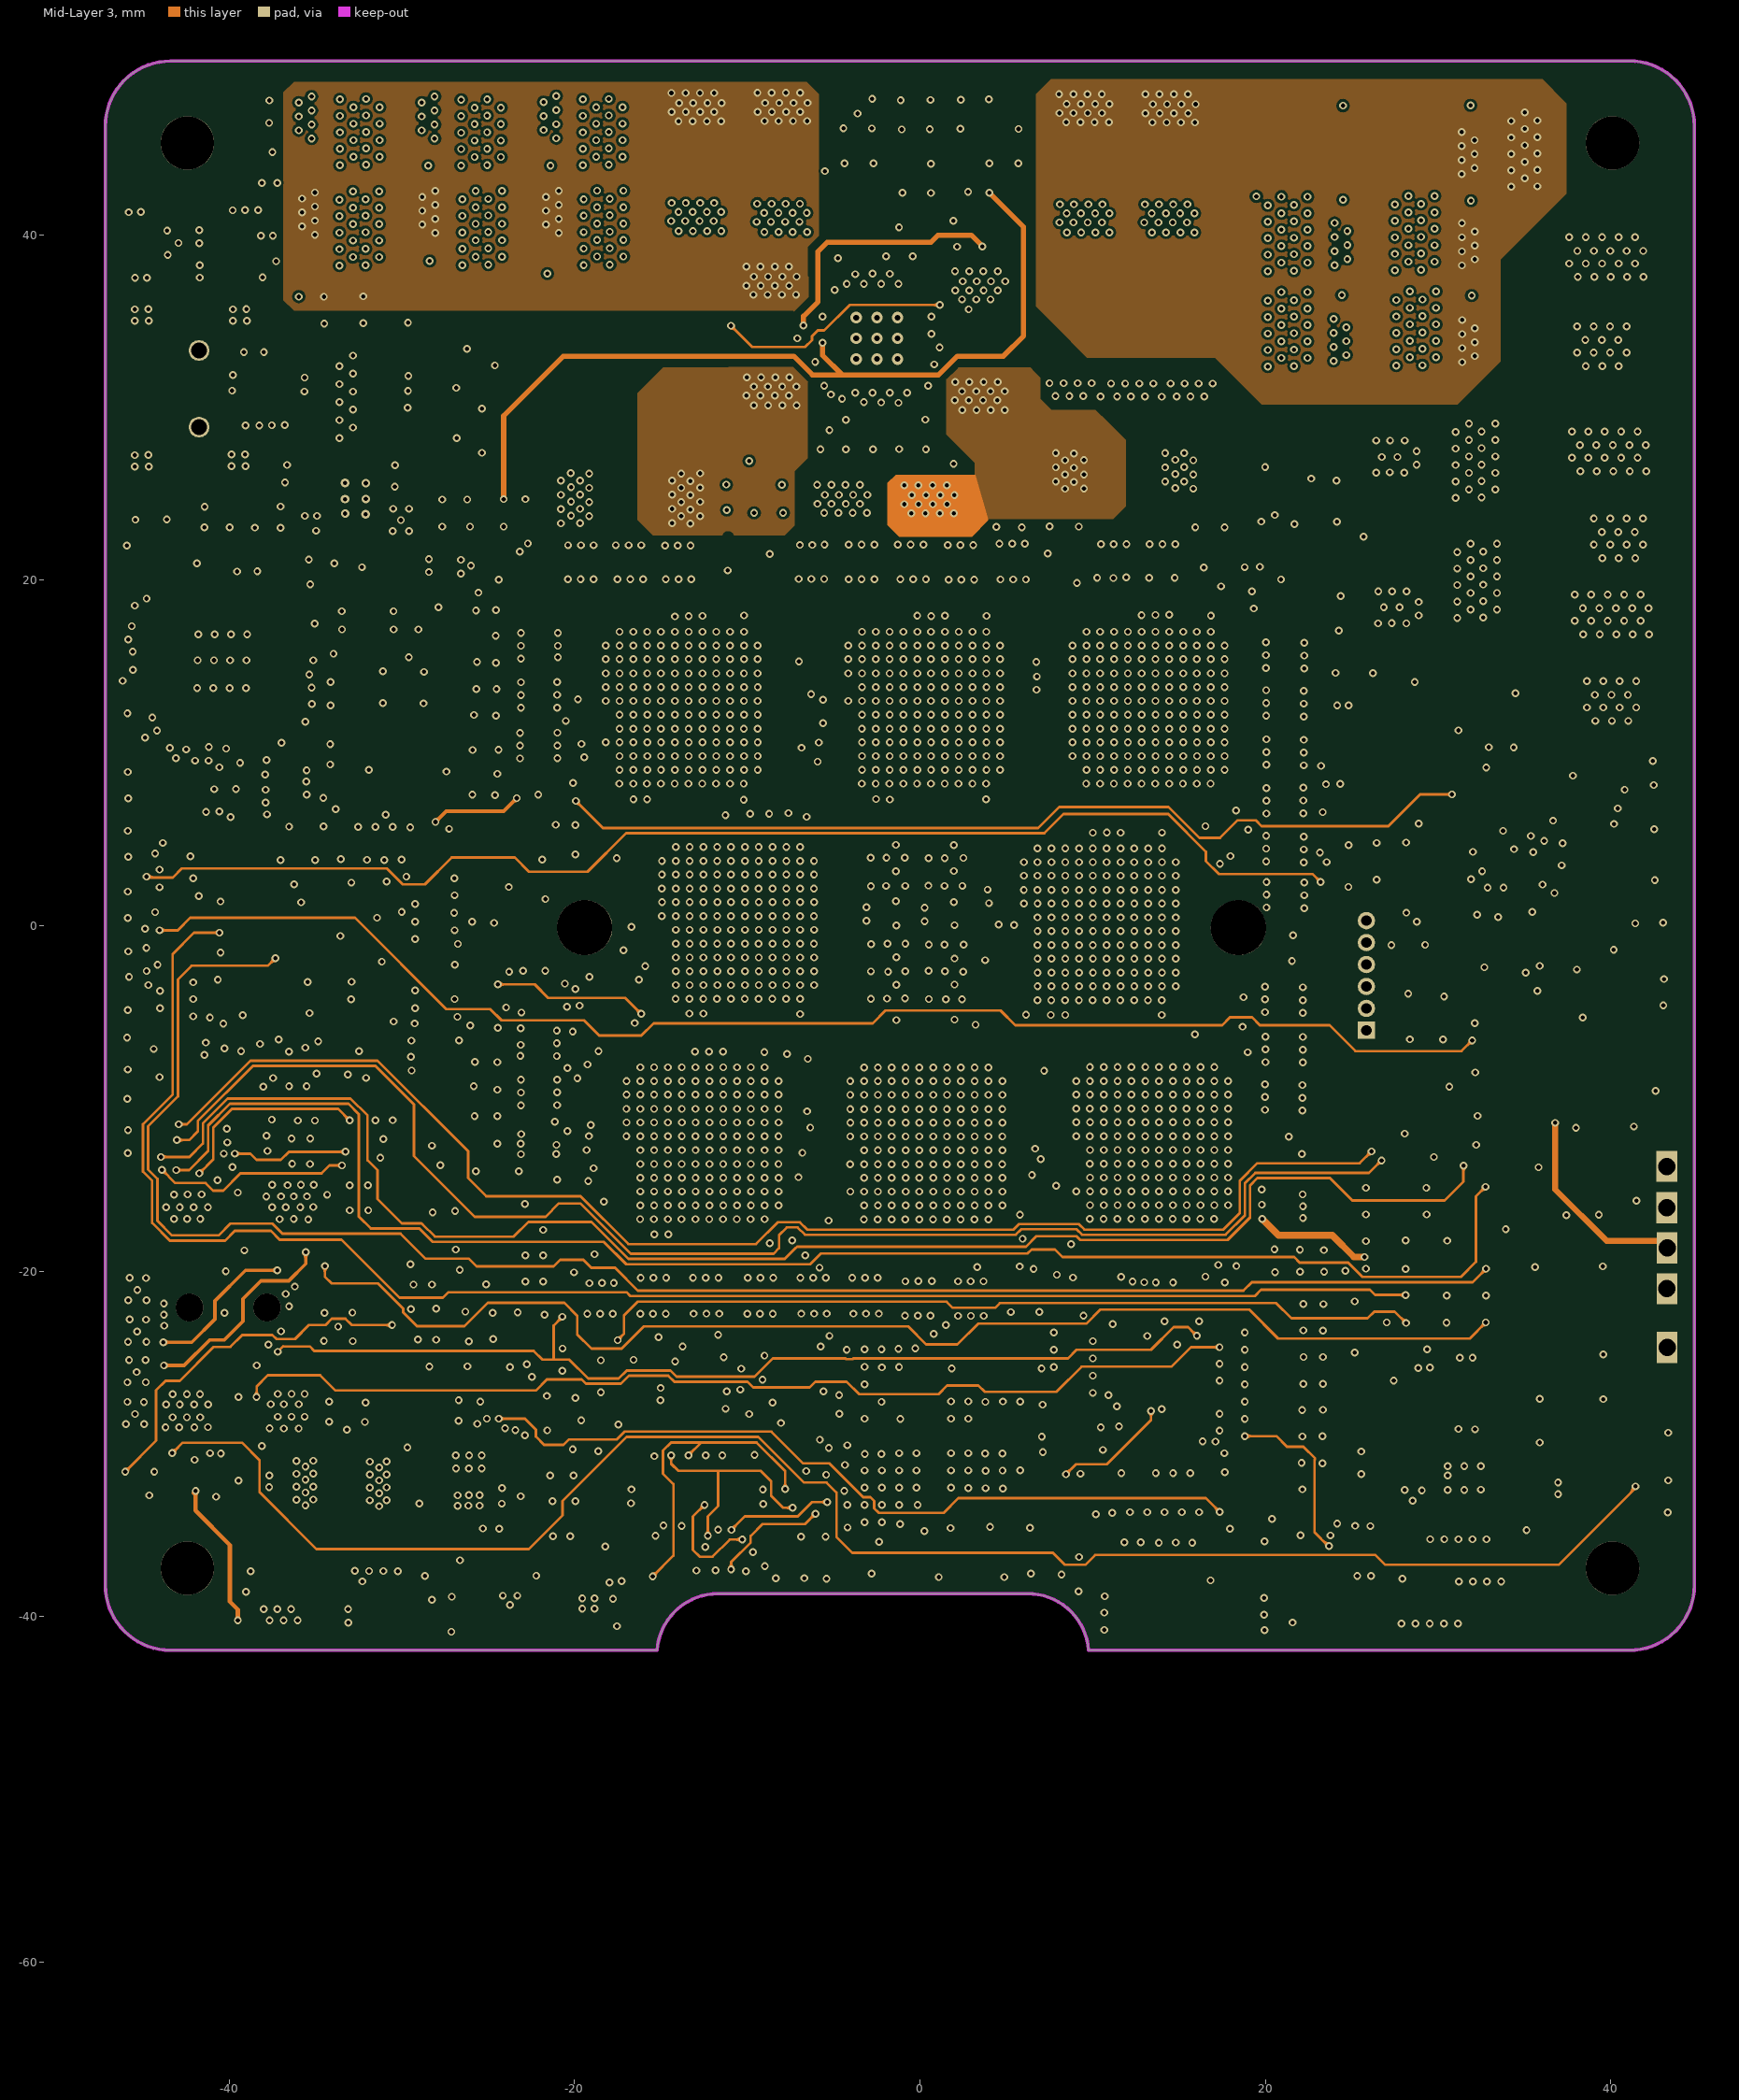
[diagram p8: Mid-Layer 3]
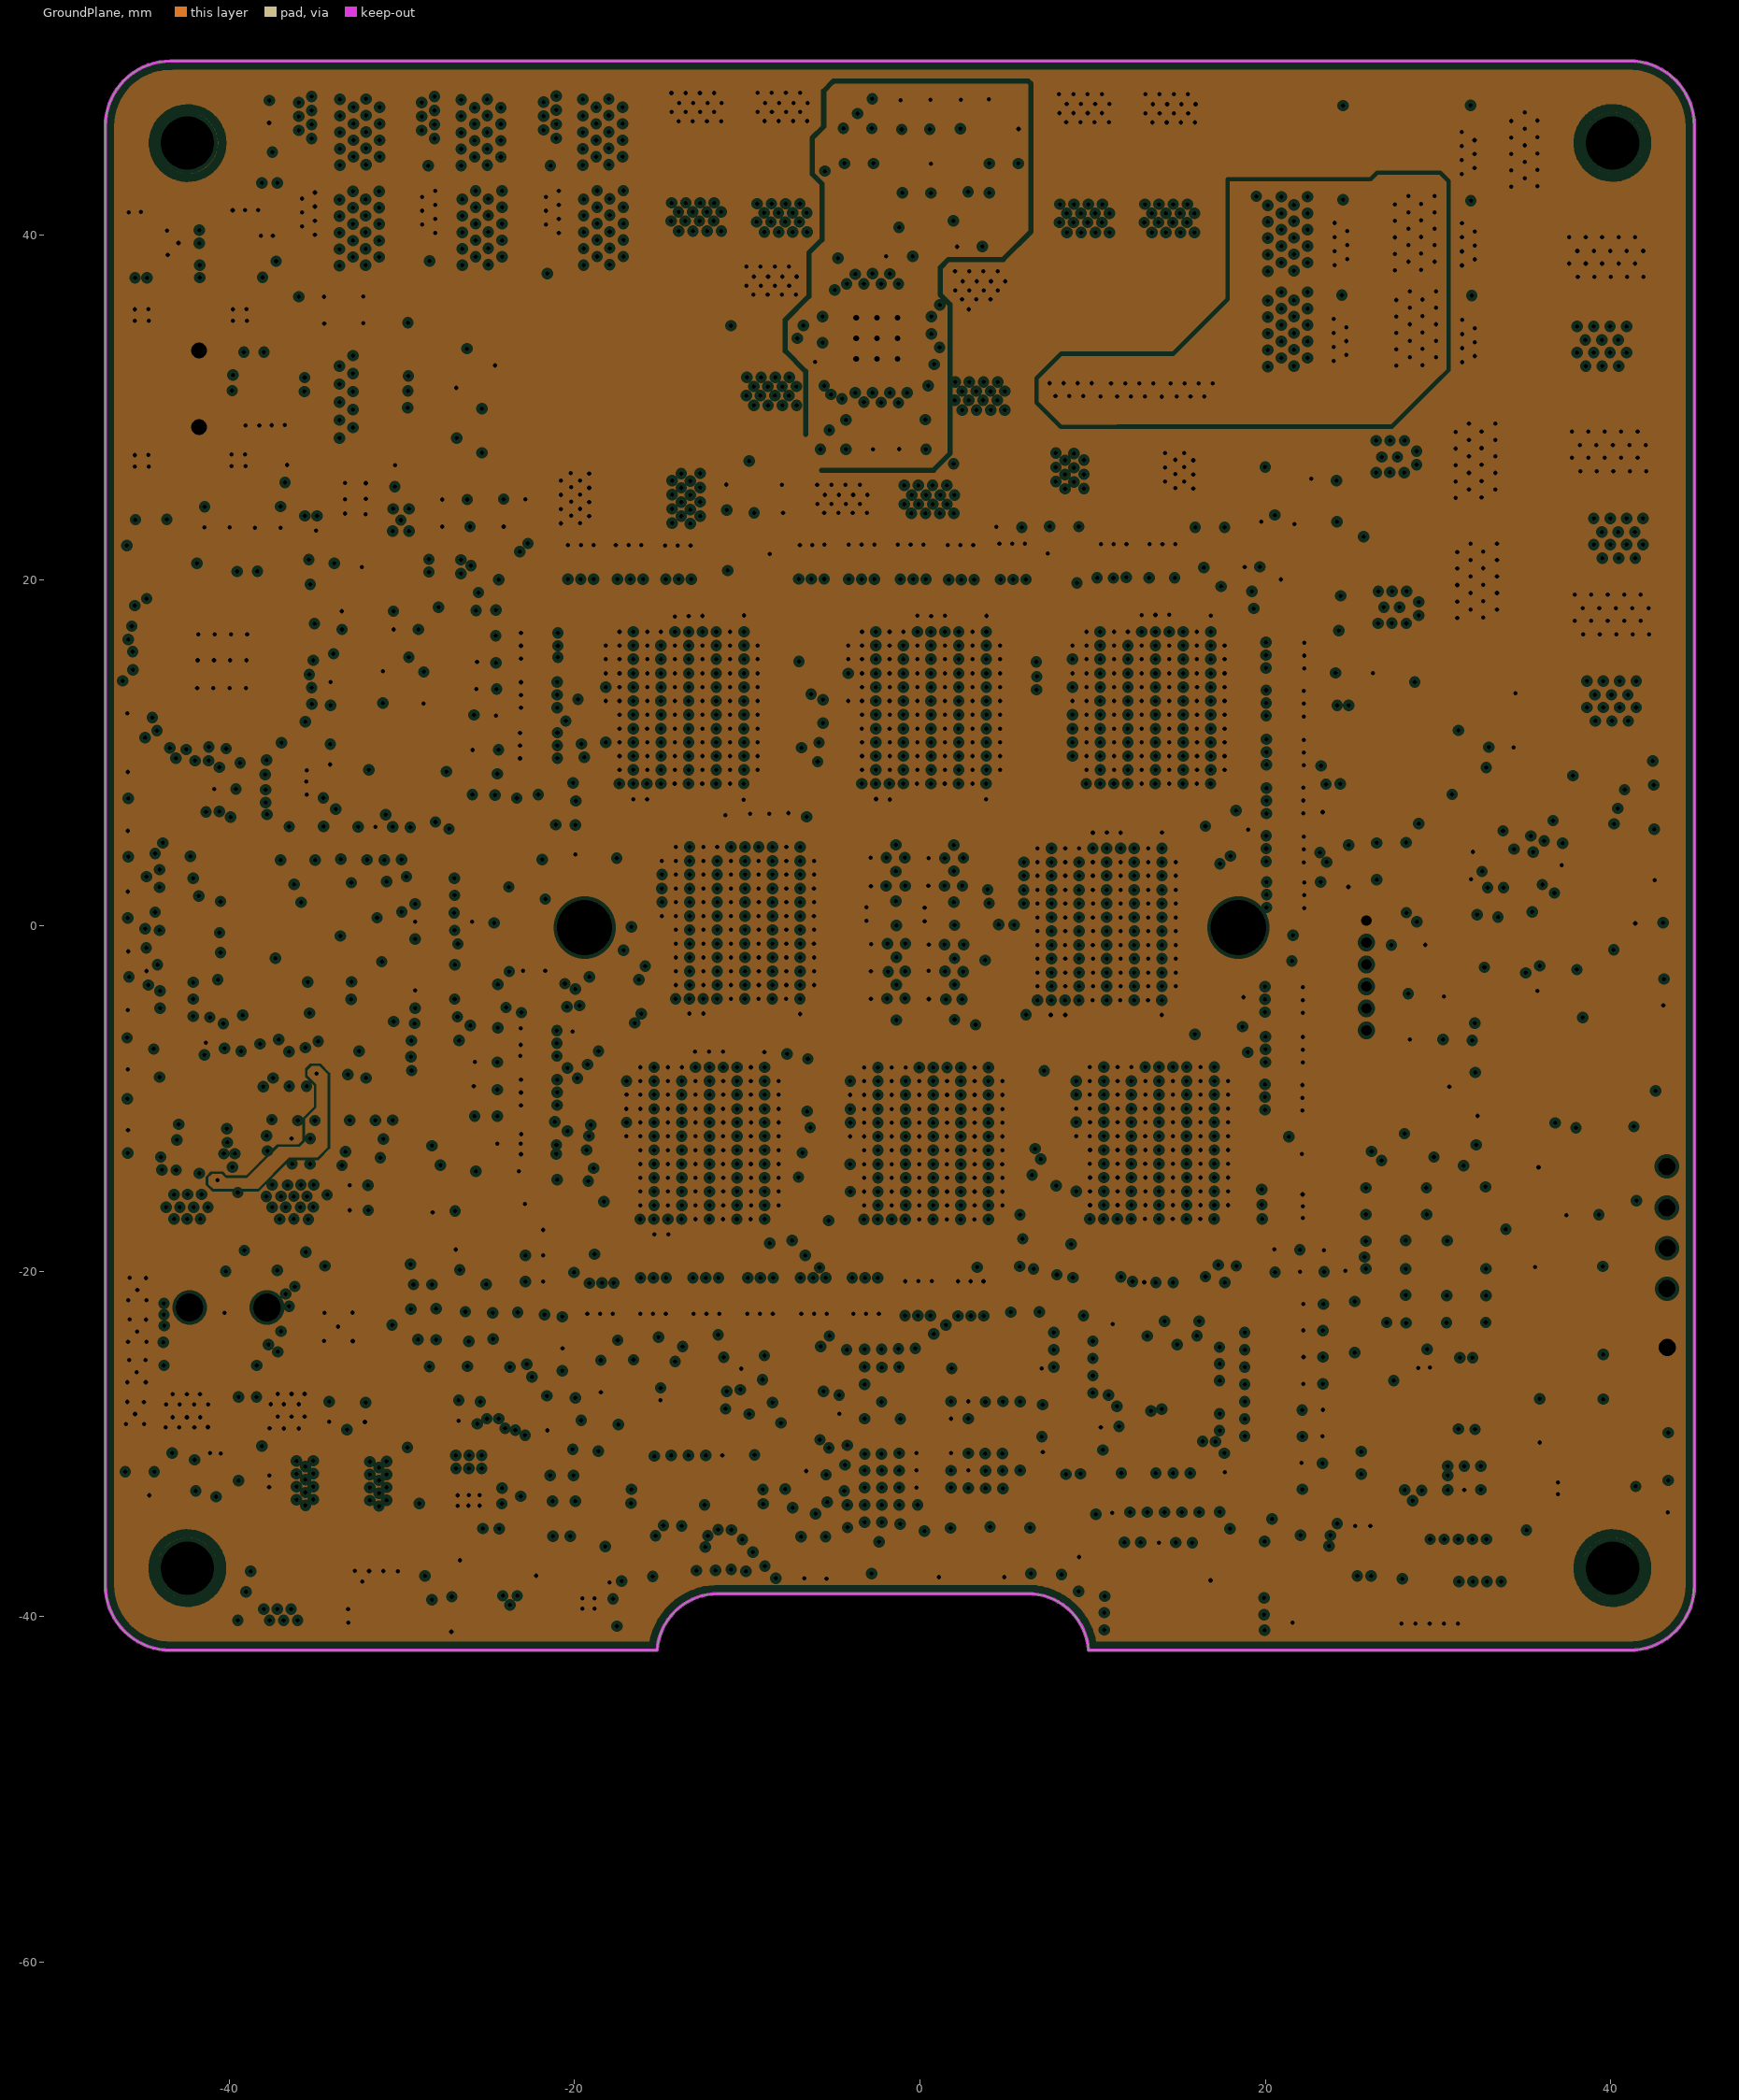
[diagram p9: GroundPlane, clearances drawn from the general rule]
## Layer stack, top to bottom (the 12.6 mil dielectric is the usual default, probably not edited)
Top Layer: signal copper 0.0356
Dielectric: core 0.32, FR-4, Dk 4.8
PowerPlane2: plane copper 0.0356, net (Multiple Nets)
Dielectric: prepreg 0.32, FR-4, Dk 4.8
Mid-Layer 1: signal copper 0.0356
Dielectric: core 0.32, FR-4, Dk 4.8
MidLayer4: signal copper 0.0356
Dielectric: prepreg 0.32, FR-4, Dk 4.8
PowerPlane1: plane copper 0.0356, net (Multiple Nets)
Dielectric: core 0.32, FR-4, Dk 4.8
Mid-Layer 2: signal copper 0.0356
Dielectric: prepreg 0.32, FR-4, Dk 4.8
SecondaryGND: plane copper 0.0356, net GND
Dielectric: core 0.32, FR-4, Dk 4.8
Mid-Layer 3: signal copper 0.0356
Dielectric: prepreg 0.32, FR-4, Dk 4.8
GroundPlane: plane copper 0.0356, net (Multiple Nets)
Dielectric: core 0.32, FR-4, Dk 4.8
Bottom Layer: signal copper 0.0356

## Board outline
-47.16,-38.17 ccw(c-43.398,-38.175) -43.393,-41.937 -15.228,-41.94 -15.218,-41.94 cw(c-11.698,-42.19) -11.449,-38.67 5.992,-38.67 cw(c6.252,-42.18) 9.762,-41.92 9.762,-41.94 41.07,-41.94 ccw(c41.075,-38.178) 44.837,-38.173 44.842,46.303 44.837,46.303 ccw(c41.075,46.308) 41.07,50.07 -43.393,50.069 -43.393,50.057 ccw(c-43.398,46.295) -47.16,46.29 -47.167,46.29

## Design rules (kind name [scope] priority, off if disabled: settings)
AssemblyTestPointUsage [All] p1 off:
AssemblyTestpoint [All] p1 off: testpointundercomponent=TRUE minsize=1.016 maxsize=2.54 preferedsize=1.524 minholesize=0 maxholesize=1.016 preferedholesize=0.813 testpointgrid=0.025 usegrid=TRUE gridtolerance=0 allowsidetop=TRUE allowsidebottom=TRUE
Clearance [All] p1: gap=0.15
ComponentClearance [All] p1 off: gap=0.254 collisioncheckmode=3 verticalgap=0.254 showdistances=FALSE
FabricationTestPointUsage [All] p1 off: valid=0 allowmultiple=FALSE
FabricationTestpoint [All] p1 off: side=3 testpointundercomponent=TRUE minsize=1.016 maxsize=2.54 preferedsize=1.524 minholesize=0 maxholesize=1.016 preferedholesize=0.813 testpointgrid=0.025 allowsidetop=TRUE allowsidebottom=TRUE usegrid=TRUE gridtolerance=0
Height [All] p1 off: minheight=0 maxheight=25.4 prefheight=12.7
HoleSize [All] p1 off: absolutevalues=TRUE maxlimit=2.54 minlimit=0.025 maxpercent=80.000 minpercent=20.000
LayerPairs [All] p1 off: enforce=TRUE
MinimumSolderMaskSliver [All] p1 off: minsoldermaskwidth=0.254
PlaneClearance [All] p1: clearance=0.208
PlaneConnect [All] p1: planeconnectstyle=Direct reliefexpansion=0.508 reliefentries=4 reliefconductorwidth=0.254 reliefairgap=0.254
PolygonConnect [All] p1: connectstyle=Direct reliefconductorwidth=0.254 reliefentries=4 polygonreliefangle="90 Angle"
RoutingVias [All] p1: holewidth=0.25 width=0.45 viastyle="Through Hole" minholewidth=0.25 minwidth=0.45 maxholewidth=10.27 maxwidth=10.27
SilkToSilkClearance [All] p1 off: silktosilkclearance=0.254
SilkscreenOverComponentPads [All] p1 off: minsilkscreentomaskgap=0.254
SolderMaskExpansion [All] p1: expansion=0.102
Width Width_VCC_3.3 [InNet('VCC+3.3')] p1: maxlimit=5 minlimit=0.2 preferedwidth=0.4 midlayer4_minwidth=0.254
Width Width_USB_POWER [InNet('USB_VBUS')] p2: maxlimit=5 minlimit=0.4 preferedwidth=1
Width Width_FAN [InNet('FAN_DRIVE')] p3: maxlimit=4 minlimit=0.254 preferedwidth=0.5
Width Width_PWR_SOURCE [InNet('PWR_MAIN')] p4: maxlimit=20 minlimit=0.2 preferedwidth=3 midlayer4_minwidth=0.5
Width Width_GND [InNet('GND')] p5: maxlimit=20 minlimit=0.15 preferedwidth=0.5
Width Width_VDD_1.0V [InNet('VCC_D')] p6: maxlimit=20 minlimit=0.2 preferedwidth=2 midlayer4_minwidth=0.254
Width Width_GENERAL [All] p7: maxlimit=10 minlimit=0.15 preferedwidth=0.15
15 further rules are at their usual default settings.

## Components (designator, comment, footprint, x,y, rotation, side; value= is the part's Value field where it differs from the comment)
ADPT "PJ-002BH-SMT" Barrel_JACK_SMD_5.5_2.5 -39.39,-22.09 r0 top
C1 "" 0603#1 2.303,47 r90 top
C2 "" 0603#1 -5.76,28.44 r90 top
C3 "" 0603#1 5.68,47.02 r90 top
C4 "" 0603#1 -4.28,28.44 r90 top
C5 "" 0603#1 4,47 r270 top
C6 "" 0603#1 8.24,20.7 r0 top
C7 "" 0603#1 -1.2,28.45 r90 top
C8 "" 0603#1 24.83,3.91 r90 top
C9 "" Cap_7mm3_4mm3 -12.947,44.26 r90 top
C10 "" Cap_7mm3_4mm3 -7.967,44.24 r90 top
C11 "" Cap_7mm3_4mm3 -8.59,34.14 r90 top
C12 "" Cap_7mm3_4mm3 3.48,33.87 r90 top
C13 "" Cap_7mm3_4mm3 9.53,44.16 r90 top
C14 "" Cap_7mm3_4mm3 14.51,44.16 r90 top
C15 "" 0603#1 0.64,43.27 r270 top
C16 "" 0603#1 -2.72,28.45 r90 top
C17 "" 0603#1 17.05,20.76 r180 top
C18 "" 0603#1 19.76,21.65 r270 top
C19 "" 0603#1 -27.01,24.69 r0 top
C20 "" 0603#1 28.65,-1.08 r180 top
C21 "" 0603#1 5.03,26.13 r180 top
C22 "" 0603#1 8.37,23.11 r0 top
C23 "" 0603#1 2.78,40.82 r0 top
C24 "" 0603#1 -23.48,24.69 r0 top
C25 "" 0603#1 -8.73,25.45 r0 top
C26 "" 0603#1 2.8,39.3 r180 top
C27 "" 0603#1 -2.05,40.38 r180 top
C34 "" 0603#1 -34.15,9.96 r90 top
C35 "" 0603#1 -25.108,13.746 r0 top
C36 "" 0603#1 -25.108,12.186 r0 top
C37 "" 0603#1 -25.108,15.276 r0 top
C38 "" 0603#1 -33.45,17.69 r270 top
C39 "" 0603#1 -34.14,13.44 r270 top
C40 "" 0603#1 -27.4,9.56 r270 top
C41 "" 0603#1 -30.49,17.69 r90 top
C42 "" 0603#1 -30.4,9.56 r270 top
C43 "" 0603#1 -31.9,9.56 r270 top
C44 "" 0603#1 -28.9,9.56 r270 top
C45 "" 0805 -32.97,20.77 r0 top
C46 "" 0603#1 -39.96,23.58 r90 top
C47 "" 0603#1 -41.41,23.57 r90 top
C48 "" 0603#1 -38.51,23.57 r270 top
C49 "" 0603#1 -37.01,23.56 r270 top
C50 "" 0805 -45.46,38.76 r90 top
C51 "" 0805 -35.67,30.26 r90 top
C53 "" 0805 -39.45,38.77 r90 top
C55 "" 0805 -20.69,-25.14 r90 top
C56 "" Cap_7mm3_4mm3 -34.1,-39.08 r0 top
C57 "" 0603#1 -22.34,-17.59 r0 top
C58 "" 0603#1 -22.34,-16.1 r0 top
C59 "" 0603#1 -26.85,29.1 r270 top
C60 "" 0603#1 -11.18,24.92 r270 top
C61 "" 0603#1 -22.33,-20.59 r180 top
C62 "" 0603#1 -22.33,-19.08 r180 top
C63 "" 0603#1 32.23,-11.79 r90 top
C64 "" 0603#1 30.05,-9.5 r180 top
C65 "" 0603#1 -27.02,23.14 r0 top
C66 "" 0603#1 -23.45,23.14 r0 top
C67 "4.7uF For MOSFET Inputs" 0603#1 21.41,17.83 r0 top
C68 "4.7uF For MOSFET Inputs" 0603#1 21.41,19.25 r0 top
C69 "4.7uF For MOSFET Inputs" 0603#1 23.32,4.83 r270 top
C70 "" 0603#1 -8.77,23.9 r180 top
C71 "" 0603#1 -2.21,-4.184 r0 top
C72 "" 0603#1 1.122,2.34 r0 top
C73 "" 0603#1 1.14,-2.62 r0 top
C74 "" 0603#1 -2.21,-1.08 r0 top
C75 "" 0603#1 -34.2,-28.17 r90 top
C76 "" 0603#1 -2.22,-2.62 r0 top
C77 "" 0603#1 1.122,3.926 r0 top
C78 "" 0603#1 -2.24,2.35 r0 top
C79 "" 0603#1 1.152,-4.184 r0 top
C80 "" 0603#1 -32.12,-28.2 r90 top
C81 "" 0603#1 1.152,-1.09 r0 top
C82 "" 0603#1 -26.71,-28.05 r90 top
C83 "" 0603#1 -25.08,-14.2 r180 top
C84 "" 0603#1 -2.24,3.926 r0 top
C85 "" 0603#1 24.81,-19.39 r90 top
C86 "" 0603#1 -25.46,33.43 r180 top
C87 "" 0603#1 22.74,-24.949 r0 top
C88 "" 0603#1 2.05,-36.78 r90 top
C89 "" 0603#1 22.74,-26.483 r0 top
C90 "" 0603#1 22.74,-31.086 r0 top
C91 "" 0603#1 5.28,-21.8 r270 top
C92 "" 0603#1 3.97,-36.78 r90 top
C93 "" 0603#1 22.74,-29.551 r180 top
C94 "" 0603#1 22.74,-28.017 r180 top
C95 "" 0603#1 -25.07,-9.45 r0 top
C96 "" 0603#1 -25.1,-7.86 r0 top
C97 "" 0603#1 5.04,23.07 r0 top
C98 "" Capacitor_SMD_8.3_8.3 30.49,27.17 r0 top
C99 "" Capacitor_SMD_8.3_8.3 39.99,25.6 r90 top
C100 "" Capacitor_SMD_8.3_8.3 30.55,18.44 r0 top
C101 "" Capacitor_SMD_8.3_8.3 40.04,36.06 r90 top
C102 "" 0603#1 -25.08,-12.59 r180 top
C103 "" 0603#1 42.05,0.15 r0 top
C104 "" 0603#2 29.2,-26.69 r270 top
C105 "" 0603#1 21.45,30.22 r270 top
C106 "" 0603#1 20,30.22 r270 top
C107 "" 0603#1 33.85,13.51 r180 top
C108 "" 0603#1 22.93,30.23 r270 top
C109 "" 0603#1 -31.648,36.426 r0 top
C110 "" 0603#1 -35.038,34.906 r180 top
C111 "" 0603#1 -35.058,36.426 r180 top
C112 "" 0603#1 -31.63,34.92 r0 top
C113 "" 0603#1 -37.67,47.1 r90 top
C114 "" 0603#1 34.67,33.37 r90 top
C115 "" 0603#1 -5.18,-36.64 r270 top
C116 "" 0603#1 -6.55,-36.64 r90 top
C117 "" 0603#1 -6.41,-30.45 r90 top
C118 "" 0603#1 -32.48,-15.04 r0 top
C119 "" 0603#1 -32.47,-16.48 r0 top
C120 "" 0603#1 -35.83,-12.28 r0 top
C121 "This is the Decoupler for the SRAM" 0603#1 -20.41,-30.31 r0 top
C122 "2uF 16V" 0805 -42.36,39.9 r0 top
C123 "2uF 16V" 0805 -37.69,42.4 r90 top
C124 "2uF 16V" 0805 -42.34,37.91 r0 top
C125 "" 0603#1 20.55,-19.39 r270 top
C126 "" 0603#1 22.74,-23.414 r0 top
C127 "" 0603#1 23.39,-19.39 r270 top
C128 "" 0603#1 21.99,-19.39 r90 top
C129 "" 0603#1 22.74,-21.88 r0 top
C130 "" 0603#1 9.21,-37.16 r270 top
C131 "" 0603#1 6.9,-21.8 r270 top
C132 "" 0603#1 -18.8,4.62 r90 top
C133 "" 0603#1 -18.95,-5.27 r90 top
C134 "" 0603#1 17.88,4.72 r270 top
C135 "" 0603#1 17.88,-4.99 r270 top
C136 "" 0603#1 -14.89,-27.08 r270 top
C137 "2uF 16V" 0805 -40.34,7.89 r0 top
C138 "" Cap_7mm3_4mm3 11.83,26.33 r0 top
C139 "" 0603#1 43.06,-3.96 r270 top
C140 "" 0603#1 7.11,-27.5 r270 top
C141 "" 0603#1 7.12,-31.55 r270 top
C142 "" Cap_7mm3_4mm3 -16.79,24.74 r180 top
C143 "" Capacitor_SMD_8.3_8.3 39.99,15.09 r90 top
C144 "2uF 16V" 0603#1 -27.6,-36.79 r180 top
C145 "" 0603#1 -40.69,-24.34 r90 top
C146 "" 0603#1 -39.01,-24.35 r270 top
C147 "" 0603#2 -45.18,-33 r0 top
C148 "" 0603#1 -31.16,-18.81 r90 top
C149 "" 0603#2 -22.66,-33 r90 top
C150 "" 0603#1 -24.38,20.88 r270 top
C151 "" Cap_7mm3_4mm3 -2.16,24.57 r180 top
C153 "this is for the AP5100 22nF Boost Pin" 0603#2 27.42,-26.69 r270 top
C154 "this is for the AP5100 22nF Boost Pin" 0603#2 43.26,-27.86 r270 top
C159 "" 0805 25.69,-36.36 r270 top
C160 "" 0201 -10.174,17.44 r90 bottom
C161 "" 0201 -9.783,16.232 r0 bottom
C162 "" 0201 -9.783,15.432 r0 bottom
C163 "" 0201 -9.783,14.632 r0 bottom
C164 "" 0201 -9.783,13.832 r0 bottom
C165 "" 0201 -9.783,13.032 r0 bottom
C166 "" 0201 -9.783,12.232 r0 bottom
C167 "" 0201 -9.783,11.432 r0 bottom
C168 "" 0201 -9.783,10.632 r0 bottom
C169 "" 0201 -9.783,9.832 r0 bottom
C170 "" 0201 -9.783,9.032 r0 bottom
C171 "" 0201 -10.198,7.818 r270 bottom
C172 "" 0201 -11.388,17.037 r0 bottom
C173 "" 0201 -11.388,16.237 r0 bottom
C174 "" 0201 -11.388,15.437 r0 bottom
C175 "" 0201 -11.388,14.637 r0 bottom
C176 "" 0201 -11.388,13.837 r0 bottom
C177 "" 0201 -11.388,13.037 r0 bottom
C178 "" 0201 -11.388,12.237 r0 bottom
C179 "" 0201 -11.388,11.437 r0 bottom
C180 "" 0201 -11.388,10.637 r0 bottom
C181 "" 0201 -11.388,9.837 r0 bottom
C182 "" 0201 -11.388,9.037 r0 bottom
C183 "" 0201 -11.388,8.237 r0 bottom
C184 "" 0201 -13.385,17.434 r90 bottom
C185 "" 0201 -12.987,16.219 r0 bottom
C186 "" 0201 -12.987,15.419 r0 bottom
C187 "" 0201 -12.987,14.619 r0 bottom
C188 "" 0201 -12.987,13.819 r0 bottom
C189 "" 0201 -12.987,13.019 r0 bottom
C190 "" 0201 -12.987,12.219 r0 bottom
C191 "" 0201 -12.987,11.419 r0 bottom
C192 "" 0201 -12.987,10.619 r0 bottom
C193 "" 0201 -12.987,9.819 r0 bottom
C194 "" 0201 -12.987,9.019 r0 bottom
C195 "" 0201 -12.987,8.219 r0 bottom
C196 "" 0201 -12.59,17.435 r90 bottom
C197 "" 0201 -14.186,17.43 r90 bottom
C198 "" 0201 -14.588,16.215 r0 bottom
C199 "" 0201 -14.588,15.415 r0 bottom
C200 "" 0201 -14.588,14.615 r0 bottom
C201 "" 0201 -14.588,13.815 r0 bottom
C202 "" 0201 -14.588,13.015 r0 bottom
C203 "" 0201 -14.588,12.215 r0 bottom
C204 "" 0201 -14.588,11.415 r0 bottom
C205 "" 0201 -14.588,10.615 r0 bottom
C206 "" 0201 -14.588,9.815 r0 bottom
C207 "" 0201 -14.588,9.015 r0 bottom
C208 "" 0201 -14.588,8.215 r0 bottom
C209 "" 0201 -15.794,7.827 r270 bottom
C210 "" 0201 -16.189,16.223 r0 bottom
C211 "" 0201 -16.189,15.423 r0 bottom
C212 "" 0201 -16.189,14.623 r0 bottom
C213 "" 0201 -16.189,13.823 r0 bottom
C214 "" 0201 -16.189,13.023 r0 bottom
C215 "" 0201 -16.189,12.223 r0 bottom
C216 "" 0201 -16.189,11.423 r0 bottom
C217 "" 0201 -16.189,10.623 r0 bottom
C218 "" 0201 -16.189,9.823 r0 bottom
C219 "" 0201 -16.189,9.023 r0 bottom
C220 "" 0201 -16.588,7.823 r270 bottom
C221 "" 0201 3.855,17.437 r90 bottom
C222 "" 0201 4.248,16.219 r0 bottom
C223 "" 0201 4.248,15.419 r0 bottom
C224 "" 0201 4.248,14.619 r0 bottom
C225 "" 0201 4.248,13.819 r0 bottom
C226 "" 0201 4.248,13.019 r0 bottom
C227 "" 0201 4.248,12.219 r0 bottom
C228 "" 0201 4.248,11.419 r0 bottom
C229 "" 0201 4.248,10.619 r0 bottom
C230 "" 0201 4.248,9.819 r0 bottom
C231 "" 0201 4.248,9.019 r0 bottom
C232 "" 0201 3.844,7.819 r270 bottom
C233 "" 0201 2.643,17.016 r0 bottom
C234 "" 0201 2.643,16.216 r0 bottom
C235 "" 0201 2.643,15.416 r0 bottom
C236 "" 0201 2.643,14.616 r0 bottom
C237 "" 0201 2.643,13.816 r0 bottom
C238 "" 0201 2.643,13.016 r0 bottom
C239 "" 0201 2.643,12.216 r0 bottom
C240 "" 0201 2.643,11.416 r0 bottom
C241 "" 0201 2.643,10.616 r0 bottom
C242 "" 0201 2.643,9.816 r0 bottom
C243 "" 0201 2.643,9.016 r0 bottom
C244 "" 0201 2.643,8.216 r0 bottom
C245 "" 0201 0.646,17.431 r90 bottom
C246 "" 0201 1.046,16.225 r0 bottom
C247 "" 0201 1.046,15.425 r0 bottom
C248 "" 0201 1.046,14.625 r0 bottom
C249 "" 0201 1.046,13.825 r0 bottom
C250 "" 0201 1.046,13.025 r0 bottom
C251 "" 0201 1.046,12.225 r0 bottom
C252 "" 0201 1.046,11.425 r0 bottom
C253 "" 0201 1.046,10.625 r0 bottom
C254 "" 0201 1.046,9.825 r0 bottom
C255 "" 0201 1.046,9.025 r0 bottom
C256 "" 0201 1.046,8.225 r0 bottom
C257 "" 0201 1.44,17.434 r90 bottom
C258 "" 0201 -0.159,17.431 r90 bottom
C259 "" 0201 -0.557,16.233 r0 bottom
C260 "" 0201 -0.557,15.433 r0 bottom
C261 "" 0201 -0.557,14.633 r0 bottom
C262 "" 0201 -0.557,13.833 r0 bottom
C263 "" 0201 -0.557,13.033 r0 bottom
C264 "" 0201 -0.557,12.233 r0 bottom
C265 "" 0201 -0.557,11.433 r0 bottom
C266 "" 0201 -0.557,10.633 r0 bottom
C267 "" 0201 -0.557,9.833 r0 bottom
C268 "" 0201 -0.557,9.033 r0 bottom
C269 "" 0201 -0.557,8.233 r0 bottom
C270 "" 0201 -2.543,7.819 r270 bottom
C271 "" 0201 -2.149,16.216 r0 bottom
C272 "" 0201 -2.149,15.416 r0 bottom
C273 "" 0201 -2.149,14.616 r0 bottom
C274 "" 0201 -2.149,13.816 r0 bottom
C275 "" 0201 -2.149,13.016 r0 bottom
C276 "" 0201 -2.149,12.216 r0 bottom
C277 "" 0201 -2.149,11.416 r0 bottom
C278 "" 0201 -2.149,10.616 r0 bottom
C279 "" 0201 -2.149,9.816 r0 bottom
C280 "" 0201 -2.149,9.016 r0 bottom
C281 "" 0201 16.845,17.437 r90 bottom
C282 "" 0201 17.246,16.219 r0 bottom
C283 "" 0201 17.246,15.419 r0 bottom
C284 "" 0201 17.246,14.619 r0 bottom
C285 "" 0201 17.246,13.819 r0 bottom
C286 "" 0201 17.246,13.019 r0 bottom
C287 "" 0201 17.246,12.219 r0 bottom
C288 "" 0201 17.246,11.419 r0 bottom
C289 "" 0201 17.246,10.619 r0 bottom
C290 "" 0201 17.246,9.819 r0 bottom
C291 "" 0201 17.246,9.019 r0 bottom
C292 "" 0201 16.828,7.823 r270 bottom
C293 "" 0201 15.638,17.021 r0 bottom
C294 "" 0201 15.638,16.221 r0 bottom
C295 "" 0201 15.638,15.421 r0 bottom
C296 "" 0201 15.638,14.621 r0 bottom
C297 "" 0201 15.638,13.821 r0 bottom
C298 "" 0201 15.638,13.021 r0 bottom
C299 "" 0201 15.638,12.221 r0 bottom
C300 "" 0201 15.638,11.421 r0 bottom
C301 "" 0201 15.638,10.621 r0 bottom
C302 "" 0201 15.638,9.821 r0 bottom
C303 "" 0201 15.638,9.021 r0 bottom
C304 "" 0201 15.638,8.221 r0 bottom
C307 "" 0201 13.641,17.445 r90 bottom
C308 "" 0201 14.042,16.218 r0 bottom
C309 "" 0201 14.042,15.418 r0 bottom
C310 "" 0201 14.042,14.618 r0 bottom
C311 "" 0201 14.042,13.818 r0 bottom
C312 "" 0201 14.042,13.018 r0 bottom
C313 "" 0201 14.042,12.218 r0 bottom
C314 "" 0201 14.042,11.418 r0 bottom
C315 "" 0201 14.042,10.618 r0 bottom
C316 "" 0201 14.042,9.818 r0 bottom
C317 "" 0201 14.042,9.018 r0 bottom
C318 "" 0201 14.042,8.218 r0 bottom
C319 "" 0201 12.837,17.437 r90 bottom
C320 "" 0201 12.439,16.212 r0 bottom
C321 "" 0201 12.439,15.412 r0 bottom
C322 "" 0201 12.439,14.612 r0 bottom
C323 "" 0201 12.439,13.812 r0 bottom
C324 "" 0201 12.439,13.012 r0 bottom
C325 "" 0201 12.439,12.212 r0 bottom
C326 "" 0201 12.439,11.412 r0 bottom
C327 "" 0201 12.439,10.612 r0 bottom
C328 "" 0201 12.439,9.812 r0 bottom
C329 "" 0201 12.439,9.012 r0 bottom
C330 "" 0201 12.439,8.212 r0 bottom
C331 "" 0201 11.236,7.808 r270 bottom
C332 "" 0201 10.838,16.225 r0 bottom
C333 "" 0201 10.838,15.425 r0 bottom
C334 "" 0201 10.838,14.625 r0 bottom
C335 "" 0201 10.838,13.825 r0 bottom
C336 "" 0201 10.838,13.025 r0 bottom
C337 "" 0201 10.838,12.225 r0 bottom
C338 "" 0201 10.838,11.425 r0 bottom
C339 "" 0201 10.838,10.625 r0 bottom
C340 "" 0201 10.838,9.825 r0 bottom
C341 "" 0201 10.838,9.025 r0 bottom
C342 "" 0201 10.442,7.808 r270 bottom
C344 "" 0201 14.023,4.909 r90 bottom
C345 "" 0201 14.416,3.69 r0 bottom
C346 "" 0201 14.416,2.89 r0 bottom
C347 "" 0201 14.416,2.09 r0 bottom
C348 "" 0201 14.416,1.29 r0 bottom
C349 "" 0201 14.416,0.49 r0 bottom
C350 "" 0201 14.416,-0.31 r0 bottom
C351 "" 0201 14.416,-1.11 r0 bottom
C352 "" 0201 14.416,-1.91 r0 bottom
C353 "" 0201 14.416,-2.71 r0 bottom
C354 "" 0201 14.416,-3.51 r0 bottom
C355 "" 0201 14,-4.719 r270 bottom
C356 "" 0201 12.808,4.484 r0 bottom
C357 "" 0201 12.808,3.684 r0 bottom
C358 "" 0201 12.808,2.884 r0 bottom
C359 "" 0201 12.808,2.084 r0 bottom
C360 "" 0201 12.808,1.284 r0 bottom
C361 "" 0201 12.808,0.484 r0 bottom
C362 "" 0201 12.808,-0.316 r0 bottom
C363 "" 0201 12.808,-1.116 r0 bottom
C364 "" 0201 12.808,-1.916 r0 bottom
C365 "" 0201 12.808,-2.716 r0 bottom
C366 "" 0201 12.808,-3.516 r0 bottom
C367 "" 0201 12.808,-4.316 r0 bottom
C368 "" 0201 11.62,4.924 r90 bottom
C369 "" 0201 11.216,3.692 r0 bottom
C370 "" 0201 11.216,2.892 r0 bottom
C371 "" 0201 11.216,2.092 r0 bottom
C372 "" 0201 11.216,1.292 r0 bottom
C373 "" 0201 11.216,0.492 r0 bottom
C374 "" 0201 11.216,-0.308 r0 bottom
C375 "" 0201 11.216,-1.108 r0 bottom
C376 "" 0201 11.216,-1.908 r0 bottom
C377 "" 0201 11.216,-2.708 r0 bottom
C378 "" 0201 11.216,-3.508 r0 bottom
C379 "" 0201 11.216,-4.308 r0 bottom
C392 "" 0201 10.019,4.921 r90 bottom
C393 "" 0201 9.608,3.691 r0 bottom
C394 "" 0201 9.608,2.891 r0 bottom
C395 "" 0201 9.608,2.091 r0 bottom
C396 "" 0201 9.608,1.291 r0 bottom
C397 "" 0201 9.608,0.491 r0 bottom
C398 "" 0201 9.608,-0.309 r0 bottom
C399 "" 0201 9.608,-1.109 r0 bottom
C400 "" 0201 9.608,-1.909 r0 bottom
C401 "" 0201 9.608,-2.709 r0 bottom
C402 "" 0201 9.608,-3.509 r0 bottom
C403 "" 0201 9.608,-4.309 r0 bottom
C404 "" 0201 8.41,-4.708 r270 bottom
C405 "" 0201 8.022,3.693 r0 bottom
C406 "" 0201 8.022,2.893 r0 bottom
C407 "" 0201 8.022,2.093 r0 bottom
C408 "" 0201 8.022,1.293 r0 bottom
C409 "" 0201 8.022,0.493 r0 bottom
C410 "" 0201 8.022,-0.307 r0 bottom
C411 "" 0201 8.022,-1.107 r0 bottom
C412 "" 0201 8.022,-1.907 r0 bottom
C413 "" 0201 8.022,-2.707 r0 bottom
C414 "" 0201 8.022,-3.507 r0 bottom
C415 "" 0201 7.603,-4.71 r270 bottom
C416 "" 0201 -6.938,5.01 r90 bottom
C417 "" 0201 -6.523,3.762 r0 bottom
C418 "" 0201 -6.523,2.962 r0 bottom
C419 "" 0201 -6.523,2.162 r0 bottom
C420 "" 0201 -6.523,1.362 r0 bottom
C421 "" 0201 -6.523,0.562 r0 bottom
C422 "" 0201 -6.523,-0.238 r0 bottom
C423 "" 0201 -6.523,-1.038 r0 bottom
C424 "" 0201 -6.523,-1.838 r0 bottom
C425 "" 0201 -6.523,-2.638 r0 bottom
C426 "" 0201 -6.523,-3.438 r0 bottom
C427 "" 0201 -6.944,-4.653 r270 bottom
C428 "" 0201 -8.144,4.569 r0 bottom
C429 "" 0201 -8.144,3.769 r0 bottom
C430 "" 0201 -8.144,2.969 r0 bottom
C431 "" 0201 -8.144,2.169 r0 bottom
C432 "" 0201 -8.144,1.369 r0 bottom
C433 "" 0201 -8.144,0.569 r0 bottom
C434 "" 0201 -8.144,-0.231 r0 bottom
C435 "" 0201 -8.144,-1.031 r0 bottom
C436 "" 0201 -8.144,-1.831 r0 bottom
C437 "" 0201 -8.144,-2.631 r0 bottom
C438 "" 0201 -8.144,-3.431 r0 bottom
C439 "" 0201 -8.144,-4.231 r0 bottom
C440 "" 0201 -9.331,4.981 r90 bottom
C441 "" 0201 -9.737,3.772 r0 bottom
C442 "" 0201 -9.737,2.972 r0 bottom
C443 "" 0201 -9.737,2.172 r0 bottom
C444 "" 0201 -9.737,1.372 r0 bottom
C445 "" 0201 -9.737,0.572 r0 bottom
C446 "" 0201 -9.737,-0.228 r0 bottom
C447 "" 0201 -9.737,-1.028 r0 bottom
C448 "" 0201 -9.737,-1.828 r0 bottom
C449 "" 0201 -9.737,-2.628 r0 bottom
C450 "" 0201 -9.737,-3.428 r0 bottom
C451 "" 0201 -9.737,-4.228 r0 bottom
C452 "" 0201 -10.941,4.982 r90 bottom
C453 "" 0201 -11.334,3.763 r0 bottom
C454 "" 0201 -11.334,2.963 r0 bottom
C455 "" 0201 -11.334,2.163 r0 bottom
C456 "" 0201 -11.334,1.363 r0 bottom
C457 "" 0201 -11.334,0.563 r0 bottom
C458 "" 0201 -11.334,-0.237 r0 bottom
C459 "" 0201 -11.334,-1.037 r0 bottom
C460 "" 0201 -11.334,-1.837 r0 bottom
C461 "" 0201 -11.334,-2.637 r0 bottom
C462 "" 0201 -11.334,-3.437 r0 bottom
C463 "" 0201 -11.334,-4.237 r0 bottom
C464 "" 0201 -12.536,-4.642 r270 bottom
C465 "" 0201 -12.939,3.756 r0 bottom
C466 "" 0201 -12.939,2.956 r0 bottom
C467 "" 0201 -12.939,2.156 r0 bottom
C468 "" 0201 -12.939,1.356 r0 bottom
C469 "" 0201 -12.939,0.556 r0 bottom
C470 "" 0201 -12.939,-0.244 r0 bottom
C471 "" 0201 -12.939,-1.044 r0 bottom
C472 "" 0201 -12.939,-1.844 r0 bottom
C473 "" 0201 -12.939,-2.644 r0 bottom
C474 "" 0201 -12.939,-3.444 r0 bottom
C475 "" 0201 -13.332,-4.649 r270 bottom
C476 "" 0201 17.05,-7.758 r90 bottom
C477 "" 0201 17.478,-8.976 r0 bottom
C478 "" 0201 17.478,-9.776 r0 bottom
C479 "" 0201 17.478,-10.576 r0 bottom
C480 "" 0201 17.478,-11.376 r0 bottom
C481 "" 0201 17.478,-12.176 r0 bottom
C482 "" 0201 17.478,-12.976 r0 bottom
C483 "" 0201 17.478,-13.776 r0 bottom
C484 "" 0201 17.478,-14.576 r0 bottom
C485 "" 0201 17.478,-15.376 r0 bottom
C486 "" 0201 17.478,-16.176 r0 bottom
C487 "" 0201 17.049,-17.401 r270 bottom
C488 "" 0201 15.845,-8.173 r0 bottom
C489 "" 0201 15.845,-8.973 r0 bottom
C490 "" 0201 15.845,-9.773 r0 bottom
C491 "" 0201 15.845,-10.573 r0 bottom
C492 "" 0201 15.845,-11.373 r0 bottom
C493 "" 0201 15.845,-12.173 r0 bottom
C494 "" 0201 15.845,-12.973 r0 bottom
C495 "" 0201 15.845,-13.773 r0 bottom
C496 "" 0201 15.845,-14.573 r0 bottom
C497 "" 0201 15.845,-15.373 r0 bottom
C498 "" 0201 15.845,-16.173 r0 bottom
C499 "" 0201 15.845,-16.973 r0 bottom
C500 "" 0201 14.652,-7.746 r90 bottom
C501 "" 0201 14.252,-8.984 r0 bottom
C502 "" 0201 14.252,-9.784 r0 bottom
C503 "" 0201 14.252,-10.584 r0 bottom
C504 "" 0201 14.252,-11.384 r0 bottom
C505 "" 0201 14.252,-12.184 r0 bottom
C506 "" 0201 14.252,-12.984 r0 bottom
C507 "" 0201 14.252,-13.784 r0 bottom
C508 "" 0201 14.252,-14.584 r0 bottom
C509 "" 0201 14.252,-15.384 r0 bottom
C510 "" 0201 14.252,-16.184 r0 bottom
C511 "" 0201 14.252,-16.984 r0 bottom
C512 "" 0201 3.966,-7.722 r90 bottom
C513 "" 0201 12.647,-8.98 r0 bottom
C514 "" 0201 12.647,-9.78 r0 bottom
C515 "" 0201 12.647,-10.58 r0 bottom
C516 "" 0201 12.647,-11.38 r0 bottom
C517 "" 0201 12.647,-12.18 r0 bottom
C518 "" 0201 12.647,-12.98 r0 bottom
C519 "" 0201 12.647,-13.78 r0 bottom
C520 "" 0201 12.647,-14.58 r0 bottom
C521 "" 0201 12.647,-15.38 r0 bottom
C522 "" 0201 12.647,-16.18 r0 bottom
C523 "" 0201 12.647,-16.98 r0 bottom
C524 "" 0201 11.437,-17.39 r270 bottom
C525 "" 0201 11.056,-8.981 r0 bottom
C526 "" 0201 11.056,-9.781 r0 bottom
C527 "" 0201 11.056,-10.581 r0 bottom
C528 "" 0201 11.056,-11.381 r0 bottom
C529 "" 0201 11.056,-12.181 r0 bottom
C530 "" 0201 11.056,-12.981 r0 bottom
C531 "" 0201 11.056,-13.781 r0 bottom
C532 "" 0201 11.056,-14.581 r0 bottom
C533 "" 0201 11.056,-15.381 r0 bottom
C534 "" 0201 11.056,-16.181 r0 bottom
C535 "" 0201 10.645,-17.39 r270 bottom
C537 "" 0201 4.369,-8.993 r0 bottom
C538 "" 0201 4.369,-9.793 r0 bottom
C539 "" 0201 4.369,-10.593 r0 bottom
C540 "" 0201 4.369,-11.393 r0 bottom
C541 "" 0201 4.369,-12.193 r0 bottom
C542 "" 0201 4.369,-12.993 r0 bottom
C543 "" 0201 4.369,-13.793 r0 bottom
C544 "" 0201 4.369,-14.593 r0 bottom
C545 "" 0201 4.369,-15.393 r0 bottom
C546 "" 0201 4.369,-16.193 r0 bottom
C547 "" 0201 3.964,-17.414 r270 bottom
C548 "" 0201 2.766,-8.197 r0 bottom
C549 "" 0201 2.766,-8.997 r0 bottom
C550 "" 0201 2.766,-9.797 r0 bottom
C551 "" 0201 2.766,-10.597 r0 bottom
C552 "" 0201 2.766,-11.397 r0 bottom
C553 "" 0201 2.766,-12.197 r0 bottom
C554 "" 0201 2.766,-12.997 r0 bottom
C555 "" 0201 2.766,-13.797 r0 bottom
C556 "" 0201 2.766,-14.597 r0 bottom
C557 "" 0201 2.766,-15.397 r0 bottom
C558 "" 0201 2.766,-16.197 r0 bottom
C559 "" 0201 2.766,-16.997 r0 bottom
C560 "" 0201 1.571,-7.77 r90 bottom
C561 "" 0201 1.166,-8.996 r0 bottom
C562 "" 0201 1.166,-9.796 r0 bottom
C563 "" 0201 1.166,-10.596 r0 bottom
C564 "" 0201 1.166,-11.396 r0 bottom
C565 "" 0201 1.166,-12.196 r0 bottom
C566 "" 0201 1.166,-12.996 r0 bottom
C567 "" 0201 1.166,-13.796 r0 bottom
C568 "" 0201 1.166,-14.596 r0 bottom
C569 "" 0201 1.166,-15.396 r0 bottom
C570 "" 0201 1.166,-16.196 r0 bottom
C571 "" 0201 1.166,-16.996 r0 bottom
C574 "" 0201 -0.04,-7.768 r90 bottom
C575 "" 0201 -0.43,-9.004 r0 bottom
C576 "" 0201 -0.43,-9.804 r0 bottom
C577 "" 0201 -0.43,-10.604 r0 bottom
C578 "" 0201 -0.43,-11.404 r0 bottom
C579 "" 0201 -0.43,-12.204 r0 bottom
C580 "" 0201 -0.43,-13.004 r0 bottom
C581 "" 0201 -0.43,-13.804 r0 bottom
C582 "" 0201 -0.43,-14.604 r0 bottom
C583 "" 0201 -0.43,-15.404 r0 bottom
C584 "" 0201 -0.43,-16.204 r0 bottom
C585 "" 0201 -0.43,-17.004 r0 bottom
C586 "" 0201 -1.629,-17.403 r270 bottom
C587 "" 0201 -2.034,-8.986 r0 bottom
C588 "" 0201 -2.034,-9.786 r0 bottom
C589 "" 0201 -2.034,-10.586 r0 bottom
C590 "" 0201 -2.034,-11.386 r0 bottom
C591 "" 0201 -2.034,-12.186 r0 bottom
C592 "" 0201 -2.034,-12.986 r0 bottom
C593 "" 0201 -2.034,-13.786 r0 bottom
C594 "" 0201 -2.034,-14.586 r0 bottom
C595 "" 0201 -2.034,-15.386 r0 bottom
C596 "" 0201 -2.034,-16.186 r0 bottom
C597 "" 0201 -2.429,-17.406 r270 bottom
C598 "" 0201 -8.992,-7.749 r90 bottom
C599 "" 0201 -8.533,-8.975 r0 bottom
C600 "" 0201 -8.533,-9.775 r0 bottom
C601 "" 0201 -8.533,-10.575 r0 bottom
C602 "" 0201 -8.533,-11.375 r0 bottom
C603 "" 0201 -8.533,-12.175 r0 bottom
C604 "" 0201 -8.533,-12.975 r0 bottom
C605 "" 0201 -8.533,-13.775 r0 bottom
C606 "" 0201 -8.533,-14.575 r0 bottom
C607 "" 0201 -8.533,-15.375 r0 bottom
C608 "" 0201 -8.533,-16.175 r0 bottom
C609 "" 0201 -8.991,-17.41 r270 bottom
C610 "" 0201 -10.186,-8.186 r0 bottom
C611 "" 0201 -10.186,-8.986 r0 bottom
C612 "" 0201 -10.186,-9.786 r0 bottom
C613 "" 0201 -10.186,-10.586 r0 bottom
C614 "" 0201 -10.186,-11.386 r0 bottom
C615 "" 0201 -10.186,-12.186 r0 bottom
C616 "" 0201 -10.186,-12.986 r0 bottom
C617 "" 0201 -10.186,-13.786 r0 bottom
C618 "" 0201 -10.186,-14.586 r0 bottom
C619 "" 0201 -10.186,-15.386 r0 bottom
C620 "" 0201 -10.186,-16.186 r0 bottom
C621 "" 0201 -10.186,-16.986 r0 bottom
C622 "" 0201 -11.383,-7.762 r90 bottom
C623 "" 0201 -11.789,-8.989 r0 bottom
C624 "" 0201 -11.789,-9.789 r0 bottom
C625 "" 0201 -11.789,-10.589 r0 bottom
C626 "" 0201 -11.789,-11.389 r0 bottom
C627 "" 0201 -11.789,-12.189 r0 bottom
C628 "" 0201 -11.789,-12.989 r0 bottom
C629 "" 0201 -11.789,-13.789 r0 bottom
C630 "" 0201 -11.789,-14.589 r0 bottom
C631 "" 0201 -11.789,-15.389 r0 bottom
C632 "" 0201 -11.789,-16.189 r0 bottom
C633 "" 0201 -11.789,-16.989 r0 bottom
C634 "" 0201 -12.992,-7.762 r90 bottom
C635 "" 0201 -13.393,-8.984 r0 bottom
C636 "" 0201 -13.393,-9.784 r0 bottom
C637 "" 0201 -13.393,-10.584 r0 bottom
C638 "" 0201 -13.393,-11.384 r0 bottom
C639 "" 0201 -13.393,-12.184 r0 bottom
C640 "" 0201 -13.393,-12.984 r0 bottom
C641 "" 0201 -13.393,-13.784 r0 bottom
C642 "" 0201 -13.393,-14.584 r0 bottom
C643 "" 0201 -13.393,-15.384 r0 bottom
C644 "" 0201 -13.393,-16.184 r0 bottom
C645 "" 0201 -13.393,-16.984 r0 bottom
C646 "" 0201 -14.598,-17.403 r270 bottom
C647 "" 0201 -14.995,-8.984 r0 bottom
C648 "" 0201 -14.995,-9.784 r0 bottom
C649 "" 0201 -14.995,-10.584 r0 bottom
C650 "" 0201 -14.995,-11.384 r0 bottom
C651 "" 0201 -14.995,-12.184 r0 bottom
C652 "" 0201 -14.995,-12.984 r0 bottom
C653 "" 0201 -14.995,-13.784 r0 bottom
C654 "" 0201 -14.995,-14.584 r0 bottom
C655 "" 0201 -14.995,-15.384 r0 bottom
C656 "" 0201 -14.995,-16.184 r0 bottom
C657 "" 0201 -15.37,-17.399 r270 bottom
C658 "" 0201 -1.743,7.819 r270 bottom
C659 "" 0201 14.445,17.46 r270 bottom
C660 "" 0201 10.819,4.924 r270 bottom
C661 "" 0201 -10.121,4.989 r270 bottom
C662 "" 0201 13.859,-7.752 r270 bottom
C663 "" 0201 13.046,-7.75 r270 bottom
C664 "" 0201 0.785,-7.768 r270 bottom
C665 "" 0201 -12.182,-7.766 r270 bottom
CA1 "" ChipResistorArray4 -19.58,21.16 r180 top
CA2 "" ChipResistorArray4 -16.8,21.16 r180 top
CA3 "" ChipResistorArray4 -13.97,21.16 r180 top
CA4 "" ChipResistorArray4 -6.29,21.19 r180 top
CA5 "" ChipResistorArray4 -3.37,21.17 r180 top
CA6 "" ChipResistorArray4 -0.49,21.17 r180 top
CA7 "" ChipResistorArray4 21.164,15.64 r90 top
CA8 "" ChipResistorArray4 21.17,12.82 r90 top
CA9 "" ChipResistorArray4 21.17,9.99 r90 top
CA10 "" ChipResistorArray4 21.17,7.19 r90 top
CA11 "" ChipResistorArray4 21.17,4.43 r90 top
CA12 "" ChipResistorArray4 21.17,1.67 r90 top
CA13 "" ChipResistorArray4 21.09,-4.33 r90 top
CA14 "" ChipResistorArray4 21.1,-7.16 r90 top
CA15 "" ChipResistorArray4 21.09,-9.94 r90 top
CA16 "" ChipResistorArray4 -3.15,-21.49 r0 top
CA17 "" ChipResistorArray4 -6.18,-21.48 r0 top
CA18 "" ChipResistorArray4 -9.233,-21.494 r0 top
CA19 "" ChipResistorArray4 -12.35,-21.49 r0 top
CA20 "" ChipResistorArray4 -15.44,-21.49 r0 top
CA21 "" ChipResistorArray4 -18.53,-21.49 r0 top
CA22 "" ChipResistorArray4 -22.15,-12.51 r270 top
CA23 "" ChipResistorArray4 -22.12,-9.67 r270 top
CA24 "" ChipResistorArray4 -22.12,-6.8 r270 top
CA25 "" ChipResistorArray4 2.422,21.16 r180 top
CA26 "" ChipResistorArray4 5.32,21.16 r180 top
CA27 "" ChipResistorArray4 14.03,21.16 r180 top
CA28 "" ChipResistorArray4 -22.09,10.36 r270 top
CA29 "" ChipResistorArray4 21.11,-16.22 r90 top
CA30 "" ChipResistorArray4 11.19,21.17 r180 top
CA31 "" ChipResistorArray4 -22.09,13.34 r270 top
CA32 "" ChipResistorArray4 -22.07,16.29 r270 top
CA33 "" ChipResistorArray4 2.98,-21.47 r180 top
CA34 "" ChipResistorArray4 -0.06,-21.45 r180 top
CN1 "CHAIN Ccnnector" NSHR-08V-S -20.74,-38.31 r0 top
CN2 "CHAIN Ccnnector" NSHR-08V-S 15.32,-38.23 r0 top
D3 "" DIODE_TOSHIBA_CMS05 -21.44,-39.53 r180 top
D4 "SS2P2L - SS2P3L" DO-220AA 35.85,-32.55 r0 top
D6 "" DIODE_TOSHIBA_CMS05 31.61,-26.87 r270 top
FAN "" PINHEADER_SMD_3PIN 31.32,-37.85 r180 top
ISP1 "Fuse - 1206SFH100F/24-2" MHDR1X6 25.85,-6.05 r90 top
J0 "Jumper to switch JTAG 2 between ARM and Simluator ATMEGA" 0603#1 31.01,-22.96 r0 top
J1 "Jumper to switch JTAG 2 between ARM and Simluator ATMEGA" 0603#1 31.04,-18.24 r0 top
J2 "Jumper to switch JTAG 2 between ARM and Simluator ATMEGA" 0603#1 31.03,-19.85 r0 top
J3 "Jumper to switch JTAG 2 between ARM and Simluator ATMEGA" 0603#1 31.03,-21.4 r0 top
J4 "Jumper to switch JTAG 2 between ARM and Simluator ATMEGA" 0603#1 27.58,-21.4 r0 top
J5 "Jumper to switch JTAG 2 between ARM and Simluator ATMEGA" 0603#1 27.58,-19.85 r0 top
J6 "Jumper to switch JTAG 2 between ARM and Simluator ATMEGA" 0603#1 27.6,-22.96 r0 top
J7 "Jumper to switch JTAG 2 between ARM and Simluator ATMEGA" 0603#1 27.61,-24.52 r0 top
J8 "Jumper to switch JTAG 2 between ARM and Simluator ATMEGA" 0603#1 -25.53,-20.75 r0 top
J9 "Jumper to switch JTAG 2 between ARM and Simluator ATMEGA" 0603#1 -29.15,-25.5 r180 top
J10 "Jumper to switch JTAG 2 between ARM and Simluator ATMEGA" 0603#1 -28.53,-23.94 r180 top
J11 "Jumper to switch JTAG 2 between ARM and Simluator ATMEGA" 0603#1 -25.2,-23.94 r180 top
J12 "Jumper to switch JTAG 2 between ARM and Simluator ATMEGA" 0603#1 -25.23,-22.38 r180 top
J13 "Jumper to switch JTAG 2 between ARM and Simluator ATMEGA" 0603#1 -25.7,-25.51 r180 top
J14 "Jumper to switch JTAG 2 between ARM and Simluator ATMEGA" 0603#1 -28.54,-22.37 r0 top
J15 "Jumper to switch JTAG 2 between ARM and Simluator ATMEGA" 0603#1 -28.79,-20.75 r0 top
J16 "Jumper to switch JTAG 2 between ARM and Simluator ATMEGA" 0603#1 27.58,-18.25 r0 top
J17 "Jumper to switch JTAG 2 between ARM and Simluator ATMEGA" 0603#1 27.58,-16.71 r0 top
J18 "Jumper to switch JTAG 2 between ARM and Simluator ATMEGA" 0603#1 27.57,-15.17 r0 top
J19 "Jumper to switch JTAG 2 between ARM and Simluator ATMEGA" 0603#1 25.17,-23.66 r90 top
JTAG1 "" HDR2X5_SMD 37.66,-24.83 r0 top
JTAG2 "" HDR2X5_SMD 37.66,-8.87 r0 top
L1 "" Inductor_XAL1010 -17.15,32.35 r270 top
L2 "" Inductor_XAL1010 12.09,34.07 r90 top
L3 "" 0805 -45.39,23.01 r90 top
L4 "" 0805 -43.33,23.02 r90 top
L5 "ASPI-6045S-2R2N-T" Inductor_IHLP2020CZER2R2M01#1 -31.16,31 r0 top
L6 "ASPI-6045S-2R2N-T" Inductor_IHLP2020CZER2R2M01#2 -33.554,-33.639 r180 top
L7 "Fuse - 1206SFH100F/24-2" Inductor_COILCRAFT_SLC1175 -17.12,32.34 r0 top
L8 "Fuse - 1206SFH100F/24-2" Inductor_COILCRAFT_SLC1175 12.1,34.08 r0 top
L9 "VLC5045T-2R2N" Inductor_5mm_5mm 27.18,-31.11 r180 top
LCD "" Header_1mmPitch_6Pos_BM06B-SRSS-TB -12.9,-31.52 r0 top
LED1 "" 0603#2 -45.2,-30.33 r180 top
LED2 "" 0603#1 -26.75,-39.69 r270 top
LED3 "" 0603#1 21.56,-39.84 r270 top
LED4 "LED Main" LED_RA_1208 42.79,3.93 r180 top
LED5 "" 0603#1 33.81,10.34 r0 top
LED6 "" 0603#1 6.41,-36.72 r0 top
LED7 "" 0603#1 -45.86,11.66 r90 top
LED8 "" 0603#1 -45.86,8.25 r90 top
LED9 "" 0603#1 -45.86,4.85 r90 top
LED10 "" 0603#1 -45.86,1.35 r90 top
LED11 "" 0603#1 -45.86,-2.13 r90 top
LED12 "" 0603#1 -45.86,-5.54 r90 top
LED13 "" 0603#1 -45.86,-8.97 r90 top
LED14 "" 0603#1 -45.86,-12.48 r90 top
Q1 "" LFPAK-4Lead -26.84,40.39 r270 top
Q2 "" LFPAK-4Lead -19.75,40.39 r270 top
Q3 "" LFPAK-4Lead 22.63,40.11 r90 top
Q4 "" LFPAK-4Lead 22.64,45.58 r90 top
Q5 "" LFPAK-4Lead -26.84,45.92 r270 top
Q6 "" LFPAK-4Lead -19.75,45.9 r270 top
Q7 "" LFPAK-4Lead 30.05,40.09 r90 top
Q8 "" LFPAK-4Lead 30.04,45.57 r90 top
Q9 "" LFPAK-4Lead -33.89,40.38 r270 top
Q10 "" LFPAK-4Lead 22.62,34.59 r90 top
Q11 "" LFPAK-4Lead -33.9,45.91 r270 top
Q12 "" LFPAK-4Lead 30.06,34.6 r90 top
Q13 "" SOT-23B 22.905,23.38 r270 top
Q14 "" SOT-23B 24.25,15.86 r0 top
Q15 "" SOT-23B 22.9,26.84 r270 top
Q16 "" SOT-23B 24.325,20.175 r180 top
R1 "" 0603#1 -4.45,47 r90 top
R2 "" 0603#1 -1.073,47 r270 top
R3 "" 0603#1 -4.73,39.49 r270 top
R4 "" 0603#1 -2.762,47 r90 top
R5 "" 0603#1 0.615,47 r270 top
R6 "" 0603#1 -1.09,38.74 r0 top
R7 "" 0603#1 -4.36,43.282 r270 top
R8 "" 0603#1 -2.683,43.282 r90 top
R9 "" 0603#1 -1.007,43.282 r90 top
R10 "" 0603#1 2.347,43.282 r90 top
R11 "" 0603#1 -7.39,12.28 r270 top
R12 "" 0603#1 -7.4,16.1 r270 top
R13 "" 0603#1 0.34,28.44 r90 top
R14 "" 0603#1 5.02,24.61 r180 top
R15 "" 0603#1 4.023,43.282 r90 top
R16 "" 0603#1 5.7,43.282 r270 top
R17 "" 0603#1 -24.4,9.56 r90 top
R18 "" 0603#1 -25.9,9.56 r90 top
R19 "" 0603#1 -32.04,17.69 r90 top
R20 "" 0603#1 -29.05,17.69 r90 top
R21 "" 0603#1 -25.08,16.78 r180 top
R22 "" 0603#1 -25.08,18.29 r180 top
R45 "" 0603#1 -25.35,29.09 r270 top
R46 "" 0603#1 -23.9,29.09 r90 top
R47 "" 0603#1 -39.43,-32.64 r90 top
R48 "" 0603#1 -40.77,-31.92 r270 top
R50 "" 0603#1 -39.47,-28.34 r270 top
R51 "" 0603#1 -42.14,-31.62 r90 top
R52 "" 0603#1 25.87,-39.96 r90 top
R53 "" 0603#1 39.96,7.88 r0 top
R54 "" 0603#1 -25.08,-11 r0 top
R55 "" 0603#1 42.45,8.76 r90 top
R56 "Impedance Resistor for Chain OUT" 0603#1 -20.4,-31.77 r0 top
R57 "Fuse - 1206SFH100F/24-2" 0603#1 20.38,-33.48 r90 top
R58 "Impedance Control for Chain IN" 0603#1 -20.39,-33.35 r180 top
R59 "Impedance control for CHAIN IN" 0603#1 -27.45,-35.3 r0 top
R60 "" 0603#1 27.29,2.61 r0 top
R61 "" 0603#1 11.8,23.1 r0 top
R62 "" 0603#1 16.79,23.06 r0 top
R63 "" 0603#1 27.3,4.82 r0 top
R64 "" 0603#1 33.8,11.8 r180 top
R65 "" 0603#1 21.55,-1.32 r90 top
R66 "" 0603#1 22.74,-32.62 r0 top
R67 "" 0603#1 8.29,-34.63 r0 top
R68 "" 0603#1 -28.85,-12.71 r0 top
R69 "" 0603#1 -39.49,-15.96 r90 top
R70 "Fuse - 1206SFH100F/24-2" 0603#1 40.18,-16.68 r0 top
R71 "Fuse - 1206SFH100F/24-2" 0603#1 36.58,-16.69 r180 top
R72 "" 0603#1 -35.83,-13.76 r0 top
R73 "" 0603#1 40.88,-32.42 r180 top
R74 "" 0603#2 -45.2,-31.65 r180 top
R75 "" 0603#1 -37.16,-19.5 r90 top
R76 "" 0603#1 -34.26,-18.73 r0 top
R77 "" 0603#1 -37.928,-31.194 r90 top
R78 "" 0603#2 -17.57,-39.75 r90 top
R79 "" 0603#2 43.3,-30.51 r90 top
R80 "" 0603#2 43.29,-33.18 r90 top
R81 "" 0603#2 -28.12,-39.49 r90 top
R82 "" 0603#2 23.56,-40.65 r0 top
R83 "" 0603#2 -2.804,-19.01 r180 top
RA1 "" ChipResistorArray4 -41.42,-12.87 r270 top
RA2 "" ChipResistorArray4 -43.75,7.94 r0 top
RA3 "" ChipResistorArray4 -22.28,-3.77 r180 top
RA4 "" ChipResistorArray4 -36.46,8.29 r90 top
RA5 "" ChipResistorArray4 -22.97,-27.65 r90 top
RA6 "" ChipResistorArray4 -6.32,-33.06 r0 top
RA7 "" ChipResistorArray4 -8.45,-36.24 r270 top
RX "" 1206 -27.91,20.85 r0 top
S1 "" SOT-23B 21.61,-13.15 r270 top
S2 "" SOT-23B -9.91,21.52 r270 top
U1 "" QFN50P800X800X10-48N -40.418,15.344 r0 top
U2 "" LQFP64_L 14.41,-27.29 r0 top
U3 "" BGA10x10-B144/X.45 -13.79,12.62 r180 top
U4 "" CP-32-3_L -2.49,34.01 r0 top
U5 "" BGA10x10-B144/X.45 0.245,12.62 r180 top
U6 "" BGA10x10-B144/X.45 13.24,12.62 r180 top
U7 "" BGA10x10-B144/X.45 -10.533,0.158 r180 top
U8 "" BGA10x10-B144/X.45 10.416,0.093 r180 top
U9 "" BGA10x10-B144/X.45 -12.588,-12.583 r180 top
U10 "" 8S2_N -24.01,2.85 r270 top
U11 "" 100T1_L -35.52,-2.75 r0 top
U12 "" FBGA100_2 0.8,-29.53 r0 top
U13 "" BGA10x10-B144/X.45 0.363,-12.597 r180 top
U14 "" BGA10x10-B144/X.45 13.445,-12.568 r180 top
U15 "" 8-PSOP -32.68,24.76 r180 top
U16 "" 8-VFDN-2PAD -26.17,-32.09 r0 top
U17 "LVDS DS90LV049HMTX/NOPB" TSSOP16_M -9.84,-25.97 r0 top
U18 "93LC56B" SOT23-6 -23.785,2.882 r180 top
U23 "LM317 - SOT223 - 3" SOT-223 27.18,10.46 r270 top
U25 "Simulator ATMEL" TQFP32_M 34.68,3.1 r0 top
U26 "" QFN32-32M1 -33.81,-23.21 r0 top
U27 "" SOT26 31.52,-31.93 r90 top
U28 "" SOT-363 -13.79,-36.48 r180 top
U29 "BSS138DW" SOT-363 -10.93,-36.48 r180 top
USB "" MiniUSB_TypeB -43.42,31.1 r180 top
UUSB "" USB_MICRO_10104110-0001LF -43.9,-24.62 r270 top
X1 "" CRYSTAL_SMD_5mm_3.2mm -29.92,13.81 r0 top
X2 "" CRYSTAL_SMD_5mm_3.2mm -27.03,-17.53 r0 top
X3 "OSCILLATOR" OSCILLATOR_SMD_5mm_3.2mm -17.85,-26.09 r270 top
X4 "OSCILLATOR" CRYSTAL_SMD_5mm_3.2mm 29.34,-5.33 r270 top
X5 "OSCILLATOR FOR ARM" Crystal_SMD_3.2mm_2mm -2.49,-36.71 r180 top
X6 "" Crystal_SMD_3.2mm_2mm -39.82,-19.48 r180 top

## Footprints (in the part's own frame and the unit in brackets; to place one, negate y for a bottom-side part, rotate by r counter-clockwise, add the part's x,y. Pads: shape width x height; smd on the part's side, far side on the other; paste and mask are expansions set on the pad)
8-PSOP [mm] "National Semi - LM22676"
  rect 1.4x0.51 smd: 1(-2.632,1.905) 2(-2.633,0.635) 3(-2.632,-0.635) 4(-2.632,-1.905) 5(2.613,-1.925) 6(2.612,-0.655) 7(2.613,0.615) 8(2.612,1.885)
  rect 2.6x3.5 smd: 9(-0.033,-0.008)
  silkscreen extent -2.66,-2.29 1.62,2.79, body extent -2.99,-2.34 2.88,2.34, height 1.25
8-VFDN-2PAD [mm]
  rect 1x0.51 smd: 1(-1.872,1.428) 2(-1.872,0.478) 3(-1.872,-0.472) 4(-1.872,-1.422)
  rect 0.8x0.51 smd: 5(1.89,-1.43) 6(1.89,-0.48) 7(1.89,0.47) 8(1.89,1.42)
  rect 2.2x2.125 smd: 9(0.06,1.13)
  rect 2.2x1.775 smd: 10(0.052,-1.347)
  silkscreen extent -2.58,-2.55 2.52,3.05, body extent -2.27,-2.41 2.21,2.46, height 1
8S2_N [mm] "8-Pin Small Outline Package 1.27 mm Pitch, IPC Medium Density"
  oval 2.2x0.6 smd: 1(-3.4,1.905) 2(-3.4,0.635) 3(-3.4,-0.635) 4(-3.4,-1.905) 5(3.4,-1.905) 6(3.4,-0.635) 7(3.4,0.635) 8(3.4,1.905)
  silkscreen extent -5.43,-2.75 4.79,2.75, body extent -2.7,-2.72 2.75,2.78, height 2.03
100T1_L [mm] "100-Pin Thin Quad Flat Pack 0.5 mm Pitch, IPC High Density"
  oval 1.55x0.25 smd: 1(-7.525,6) 2(-7.525,5.5) 3(-7.525,5) 4(-7.525,4.5) 5(-7.525,4) 6(-7.525,3.5) 7(-7.525,3) 8(-7.525,2.5) 9(-7.525,2) 10(-7.525,1.5) 11(-7.525,1) 12(-7.525,0.5) 13(-7.525,0) 14(-7.525,-0.5) 15(-7.525,-1) 16(-7.525,-1.5) 17(-7.525,-2) 18(-7.525,-2.5) 19(-7.525,-3) 20(-7.525,-3.5) 21(-7.525,-4) 22(-7.525,-4.5) 23(-7.525,-5) 24(-7.525,-5.5) 25(-7.525,-6) 51(7.525,-6) 52(7.525,-5.5) 53(7.525,-5) 54(7.525,-4.5) 55(7.525,-4) 56(7.525,-3.5) 57(7.525,-3) 58(7.525,-2.5) 59(7.525,-2) 60(7.525,-1.5) 61(7.525,-1) 62(7.525,-0.5) 63(7.525,0) 64(7.525,0.5) 65(7.525,1) 66(7.525,1.5) 67(7.525,2) 68(7.525,2.5) 69(7.525,3) 70(7.525,3.5) 71(7.525,4) 72(7.525,4.5) 73(7.525,5) 74(7.525,5.5) 75(7.525,6)
  oval 0.25x1.55 smd: 26(-6,-7.525) 27(-5.5,-7.525) 28(-5,-7.525) 29(-4.5,-7.525) 30(-4,-7.525) 31(-3.5,-7.525) 32(-3,-7.525) 33(-2.5,-7.525) 34(-2,-7.525) 35(-1.5,-7.525) 36(-1,-7.525) 37(-0.5,-7.525) 38(0,-7.525) 39(0.5,-7.525) 40(1,-7.525) 41(1.5,-7.525) 42(2,-7.525) 43(2.5,-7.525) 44(3,-7.525) 45(3.5,-7.525) 46(4,-7.525) 47(4.5,-7.525) 48(5,-7.525) 49(5.5,-7.525) 50(6,-7.525) 76(6,7.525) 77(5.5,7.525) 78(5,7.525) 79(4.5,7.525) 80(4,7.525) 81(3.5,7.525) 82(3,7.525) 83(2.5,7.525) 84(2,7.525) 85(1.5,7.525) 86(1,7.525) 87(0.5,7.525) 88(0,7.525) 89(-0.5,7.525) 90(-1,7.525) 91(-1.5,7.525) 92(-2,7.525) 93(-2.5,7.525) 94(-3,7.525) 95(-3.5,7.525) 96(-4,7.525) 97(-4.5,7.525) 98(-5,7.525) 99(-5.5,7.525) 100(-6,7.525)
  silkscreen extent -7.65,6.55 -7.4,6.8, body extent -7,-7 7,7, height 1.05
0201 [mm]
  rect 0.3x0.3 smd: 1(-0.3,0) 2(0.3,0)
0603#1 [mm]
  rect 1.1x1 smd: 1(-0.85,0) 2(0.85,0)
  silkscreen extent -0.2,-0.41 0.18,0.38
0603#2 [mm]
  rect 0.6x1 smd: 1(-0.78,0) 2(0.78,0)
  silkscreen extent -1.2,-0.68 1.19,0.69, body extent -0.99,-0.47 1.02,0.47, height 0.8
0805 [mm]
  rect 1.3x1.5 smd: 1(-0.916,-0.001) 2(0.916,0.001)
1206 [mm] "1206 Standard"
  rect 1.45x1.8 smd: 1(-1.495,0) 2(1.495,0)
  silkscreen extent -0.69,-0.82 0.69,0.82
Barrel_JACK_SMD_5.5_2.5 [mm]
  rect 2.4x2.8 smd: 1(3.05,5.845) 2(-3.05,5.845) 3(3.05,-5.845) 4(-3.06,-5.85)
  round 1.6 hole 1.6 unplated: X(-2.89,-0.005) Y(1.59,-0.005)
  silkscreen extent -7.78,-4.57 6.68,4.44, body extent -7.89,-4.55 6.68,4.47, height 11
BGA10x10-B144/X.45 [mm]
  round 0.5 smd: A1(-4.4,4.4) A2(-3.6,4.4) A3(-2.8,4.4) A4(-2,4.4) A5(-1.2,4.4) A6(-0.4,4.4) A7(0.4,4.4) A8(1.2,4.4) A9(2,4.4) A10(2.8,4.4) A11(3.6,4.4) A12(4.4,4.4) B1(-4.4,3.6) B2(-3.6,3.6) B3(-2.8,3.6) B4(-2,3.6) B5(-1.2,3.6) B6(-0.4,3.6) B7(0.4,3.6) B8(1.2,3.6) B9(2,3.6) B10(2.8,3.6) B11(3.6,3.6) B12(4.4,3.6) C1(-4.4,2.8) C2(-3.6,2.8) C3(-2.8,2.8) C4(-2,2.8) C5(-1.2,2.8) C6(-0.4,2.8) C7(0.4,2.8) C8(1.2,2.8) C9(2,2.8) C10(2.8,2.8) C11(3.6,2.8) C12(4.4,2.8) D1(-4.4,2) D2(-3.6,2) D3(-2.8,2) D4(-2,2) D5(-1.2,2) D6(-0.4,2) D7(0.4,2) D8(1.2,2) D9(2,2) D10(2.8,2) D11(3.6,2) D12(4.4,2) E1(-4.4,1.2) E2(-3.6,1.2) E3(-2.8,1.2) E4(-2,1.2) E5(-1.2,1.2) E6(-0.4,1.2) E7(0.4,1.2) E8(1.2,1.2) E9(2,1.2) E10(2.8,1.2) E11(3.6,1.2) E12(4.4,1.2) F1(-4.4,0.4) F2(-3.6,0.4) F3(-2.8,0.4) F4(-2,0.4) F5(-1.2,0.4) F6(-0.4,0.4) F7(0.4,0.4) F8(1.2,0.4) F9(2,0.4) F10(2.8,0.4) F11(3.6,0.4) F12(4.4,0.4) G1(-4.4,-0.4) G2(-3.6,-0.4) G3(-2.8,-0.4) G4(-2,-0.4) G5(-1.2,-0.4) G6(-0.4,-0.4) G7(0.4,-0.4) G8(1.2,-0.4) G9(2,-0.4) G10(2.8,-0.4) G11(3.6,-0.4) G12(4.4,-0.4) H1(-4.4,-1.2) H2(-3.6,-1.2) H3(-2.8,-1.2) H4(-2,-1.2) H5(-1.2,-1.2) H6(-0.4,-1.2) H7(0.4,-1.2) H8(1.2,-1.2) H9(2,-1.2) H10(2.8,-1.2) H11(3.6,-1.2) H12(4.4,-1.2) J1(-4.4,-2) J2(-3.6,-2) J3(-2.8,-2) J4(-2,-2) J5(-1.2,-2) J6(-0.4,-2) J7(0.4,-2) J8(1.2,-2) J9(2,-2) J10(2.8,-2) J11(3.6,-2) J12(4.4,-2) K1(-4.4,-2.8) K2(-3.6,-2.8) K3(-2.8,-2.8) K4(-2,-2.8) K5(-1.2,-2.8) K6(-0.4,-2.8) K7(0.4,-2.8) K8(1.2,-2.8) K9(2,-2.8) K10(2.8,-2.8) K11(3.6,-2.8) K12(4.4,-2.8) L1(-4.4,-3.6) L2(-3.6,-3.6) L3(-2.8,-3.6) L4(-2,-3.6) L5(-1.2,-3.6) L6(-0.4,-3.6) L7(0.4,-3.6) L8(1.2,-3.6) L9(2,-3.6) L10(2.8,-3.6) L11(3.6,-3.6) L12(4.4,-3.6) M1(-4.4,-4.4) M2(-3.6,-4.4) M3(-2.8,-4.4) M4(-2,-4.4) M5(-1.2,-4.4) M6(-0.4,-4.4) M7(0.4,-4.4) M8(1.2,-4.4) M9(2,-4.4) M10(2.8,-4.4) M11(3.6,-4.4) M12(4.4,-4.4)
  silkscreen extent -5.89,-5.1 5.1,5.1
Cap_7mm3_4mm3 [mm] "Capacitor 7.3mm X 4.3mm"
  rect 2.4x2.8 smd: 1(-3.213,0) 2(3.213,0)
  silkscreen extent -3.7,-2.29 3.64,2.34
Capacitor_SMD_8.3_8.3 [mm]
  rect 3x1.8 smd: 1(-3.28,0) 2(3.28,0)
  silkscreen extent -4.19,-4.12 4.15,4.26, body extent -4.22,-4.15 4.16,4.29, height 10
ChipResistorArray4 [mm]
  rect 0.4x0.6 smd: 1(-0.81,-0.5) 2(-0.81,0.5) 7(0.81,-0.5) 8(0.81,0.5)
  rect 0.3x0.6 smd: 3(-0.252,-0.5) 4(-0.252,0.5) 5(0.26,-0.5) 6(0.26,0.5)
  silkscreen extent -1.2,-0.96 1.19,0.99
CP-32-3_L [mm] "QFN, 32-Leads, Body 5x5mm, Pitch 0.5mm, IPC High Density"
  oval 0.7x0.25 smd: 1(-2.45,1.75) 2(-2.45,1.25) 3(-2.45,0.75) 4(-2.45,0.25) 5(-2.45,-0.25) 6(-2.45,-0.75) 7(-2.45,-1.25) 8(-2.45,-1.75) 17(2.45,-1.75) 18(2.45,-1.25) 19(2.45,-0.75) 20(2.45,-0.25) 21(2.45,0.25) 22(2.45,0.75) 23(2.45,1.25) 24(2.45,1.75)
  oval 0.25x0.7 smd: 9(-1.75,-2.45) 10(-1.25,-2.45) 11(-0.75,-2.45) 12(-0.25,-2.45) 13(0.25,-2.45) 14(0.75,-2.45) 15(1.25,-2.45) 16(1.75,-2.45) 25(1.75,2.45) 26(1.25,2.45) 27(0.75,2.45) 28(0.25,2.45) 29(-0.25,2.45) 30(-0.75,2.45) 31(-1.25,2.45) 32(-1.75,2.45)
  rect 3.3x3.3 smd: 33(0,0)
  body extent -2.58,-2.58 2.58,2.58, height 1
Crystal_SMD_3.2mm_2mm [mm]
  rect 1.4x1.2 smd: 1(-1.1,-0.805) 2(1.1,-0.805) 3(1.1,0.805) 4(-1.1,0.805)
  silkscreen extent -2.42,-1.32 1.7,1.28, body extent -1.66,-1.28 1.67,1.29, height 1
CRYSTAL_SMD_5mm_3.2mm [mm]
  rect 2x1.2 smd: 1(-1.87,-1.215) 2(1.87,-1.215) 3(1.87,1.175) 4(-1.87,1.215)
  silkscreen extent -3.32,-2.25 3.07,1.98, body extent -2.68,-1.64 2.7,1.63, height 1
DIODE_TOSHIBA_CMS05 [mm]
  rect 1.4x2.1 smd: 1(-2.251,0) 2(2.251,0)
  silkscreen extent -2.25,-1.35 2.3,1.38
DO-220AA [mm]
  rect 0.762x1.27 smd: 1(1.185,0)
  rect 2.67x2.54 smd: 2(-1.185,0)
  silkscreen extent -2.68,-1.46 1.75,1.49
FBGA100_2 [mm] "BGA, 100-Leads, Body 11x11mm, Pitch 1mm"
  round 0.45 smd: A1(-4.5,4.5) A2(-3.5,4.5) A3(-2.5,4.5) A4(-1.5,4.5) A5(-0.5,4.5) A6(0.5,4.5) A7(1.5,4.5) A8(2.5,4.5) A9(3.5,4.5) A10(4.5,4.5) B1(-4.5,3.5) B2(-3.5,3.5) B3(-2.5,3.5) B4(-1.5,3.5) B5(-0.5,3.5) B6(0.5,3.5) B7(1.5,3.5) B8(2.5,3.5) B9(3.5,3.5) B10(4.5,3.5) C1(-4.5,2.5) C2(-3.5,2.5) C3(-2.5,2.5) C4(-1.5,2.5) C5(-0.5,2.5) C6(0.5,2.5) C7(1.5,2.5) C8(2.5,2.5) C9(3.5,2.5) C10(4.5,2.5) D1(-4.5,1.5) D2(-3.5,1.5) D3(-2.5,1.5) D4(-1.5,1.5) D5(-0.5,1.5) D6(0.5,1.5) D7(1.5,1.5) D8(2.5,1.5) D9(3.5,1.5) D10(4.5,1.5) E1(-4.5,0.5) E2(-3.5,0.5) E3(-2.5,0.5) E4(-1.5,0.5) E5(-0.5,0.5) E6(0.5,0.5) E7(1.5,0.5) E8(2.5,0.5) E9(3.5,0.5) E10(4.5,0.5) F1(-4.5,-0.5) F2(-3.5,-0.5) F3(-2.5,-0.5) F4(-1.5,-0.5) F5(-0.5,-0.5) F6(0.5,-0.5) F7(1.5,-0.5) F8(2.5,-0.5) F9(3.5,-0.5) F10(4.5,-0.5) G1(-4.5,-1.5) G2(-3.5,-1.5) G3(-2.5,-1.5) G4(-1.5,-1.5) G5(-0.5,-1.5) G6(0.5,-1.5) G7(1.5,-1.5) G8(2.5,-1.5) G9(3.5,-1.5) G10(4.5,-1.5) H1(-4.5,-2.5) H2(-3.5,-2.5) H3(-2.5,-2.5) H4(-1.5,-2.5) H5(-0.5,-2.5) H6(0.5,-2.5) H7(1.5,-2.5) H8(2.5,-2.5) H9(3.5,-2.5) H10(4.5,-2.5) J1(-4.5,-3.5) J2(-3.5,-3.5) J3(-2.5,-3.5) J4(-1.5,-3.5) J5(-0.5,-3.5) J6(0.5,-3.5) J7(1.5,-3.5) J8(2.5,-3.5) J9(3.5,-3.5) J10(4.5,-3.5) K1(-4.5,-4.5) K2(-3.5,-4.5) K3(-2.5,-4.5) K4(-1.5,-4.5) K5(-0.5,-4.5) K6(0.5,-4.5) K7(1.5,-4.5) K8(2.5,-4.5) K9(3.5,-4.5) K10(4.5,-4.5)
  silkscreen extent -6,-5.5 5.5,6, body extent -5.5,-5.5 5.5,5.5, height 1.55
HDR2X5_SMD [mm]
  rect 2.8x1 smd: 1(2.811,-5.087) 2(-2.811,-5.074) 3(2.811,-2.547) 4(-2.811,-2.534) 5(2.811,-0.007) 6(-2.811,0.006) 7(2.811,2.533) 8(-2.811,2.546) 9(2.811,5.073) 10(-2.811,5.086)
  silkscreen extent -2.46,-6.19 2.7,6.08
Header_1mmPitch_6Pos_BM06B-SRSS-TB [mm]
  rect 0.6x1.55 smd: 1(-2.49,1.255) 2(-1.49,1.255) 3(-0.49,1.255) 4(0.51,1.255) 5(1.51,1.255) 6(2.51,1.255)
  rect 1.2x1.8 smd: X(-3.79,-1.255) Y(3.79,-1.255)
  silkscreen extent -4.33,-0.24 4.27,1.92, body extent -3.64,-1.94 3.53,0.92, height 5.4
Inductor_5mm_5mm [mm]
  rect 2x5 smd: 1(1.525,0) 2(-1.525,0)
  silkscreen extent -2.69,-2.66 2.67,2.65
Inductor_COILCRAFT_SLC1175 [mm]
  rect 3.5x2.6 smd: 1(-3.995,0) 2(3.995,0)
Inductor_IHLP2020CZER2R2M01#1 [mm]
  rect 2x5.7 smd: 1(2.04,-0.39) 2(-2.16,-0.38)
  silkscreen extent -3.37,-3.43 3.25,2.71
Inductor_IHLP2020CZER2R2M01#2 [mm]
  rect 2x5.7 smd: 1(2.273,-0.386) 2(-2.334,-0.4)
  silkscreen extent -3.37,-3.43 3.25,2.71
Inductor_XAL1010 [mm]
  rect 2.38x11.31 smd: 1(-3.335,0) 2(3.335,0)
  silkscreen extent -4.95,-5.76 4.98,5.8, body extent -4.19,-5.44 4.2,5.46, height 10
LED_RA_1208 [mm] "Typical INFRARED GaAs LED; 2 Leads"
  rect 1.5x1.6 smd: 1(0.241,-1.657) 2(0.236,1.737)
  rect 0.9x0.9 smd: 3(0.908,0.04)
  silkscreen extent -1.45,-2.8 1.6,2.84
LFPAK-4Lead [mm] "This is used by most MOSFETs"
  rect 0.7x1.2 smd: 1(-1.905,-1.84) 2(-0.635,-1.84) 3(0.635,-1.84) 4(1.905,-1.84)
  rect 5x4.4 smd: 5(-0.015,1.84)
  silkscreen extent -2.65,-2.63 2.58,4.15
LQFP64_L [mm] "Thin QFP, 64-Leads, Body 10x10mm, Pitch 0.5mm, IPC High Density"
  oval 1.55x0.25 smd: 1(-5.525,3.75) 2(-5.525,3.25) 3(-5.525,2.75) 4(-5.525,2.25) 5(-5.525,1.75) 6(-5.525,1.25) 7(-5.525,0.75) 8(-5.525,0.25) 9(-5.525,-0.25) 10(-5.525,-0.75) 11(-5.525,-1.25) 12(-5.525,-1.75) 13(-5.525,-2.25) 14(-5.525,-2.75) 15(-5.525,-3.25) 16(-5.525,-3.75) 33(5.525,-3.75) 34(5.525,-3.25) 35(5.525,-2.75) 36(5.525,-2.25) 37(5.525,-1.75) 38(5.525,-1.25) 39(5.525,-0.75) 40(5.525,-0.25) 41(5.525,0.25) 42(5.525,0.75) 43(5.525,1.25) 44(5.525,1.75) 45(5.525,2.25) 46(5.525,2.75) 47(5.525,3.25) 48(5.525,3.75)
  oval 0.25x1.55 smd: 17(-3.75,-5.525) 18(-3.25,-5.525) 19(-2.75,-5.525) 20(-2.25,-5.525) 21(-1.75,-5.525) 22(-1.25,-5.525) 23(-0.75,-5.525) 24(-0.25,-5.525) 25(0.25,-5.525) 26(0.75,-5.525) 27(1.25,-5.525) 28(1.75,-5.525) 29(2.25,-5.525) 30(2.75,-5.525) 31(3.25,-5.525) 32(3.75,-5.525) 49(3.75,5.525) 50(3.25,5.525) 51(2.75,5.525) 52(2.25,5.525) 53(1.75,5.525) 54(1.25,5.525) 55(0.75,5.525) 56(0.25,5.525) 57(-0.25,5.525) 58(-0.75,5.525) 59(-1.25,5.525) 60(-1.75,5.525) 61(-2.25,5.525) 62(-2.75,5.525) 63(-3.25,5.525) 64(-3.75,5.525)
  silkscreen extent -5.65,-4.35 4.35,4.55, body extent -5,-5 5,5, height 1.6
MHDR1X6 [mm] "Connector; Header; 6 Position"
  rect 1x1 hole 0.6: 1(0,0)
  round 1 hole 0.6: 2(1.27,0) 3(2.54,0) 4(3.81,0) 5(5.08,0) 6(6.35,0)
  silkscreen extent -0.9,-0.9 7.25,0.9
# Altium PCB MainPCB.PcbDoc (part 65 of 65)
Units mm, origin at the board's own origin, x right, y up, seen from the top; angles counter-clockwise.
Board outline 92.01 x 92.01 mm, 10 copper layers (Top Layer, PowerPlane2, Mid-Layer 1, MidLayer4, PowerPlane1, Mid-Layer 2, SecondaryGND, Mid-Layer 3, GroundPlane, Bottom Layer); 840 components, 219 nets, 3641 pads, 3367 vias.

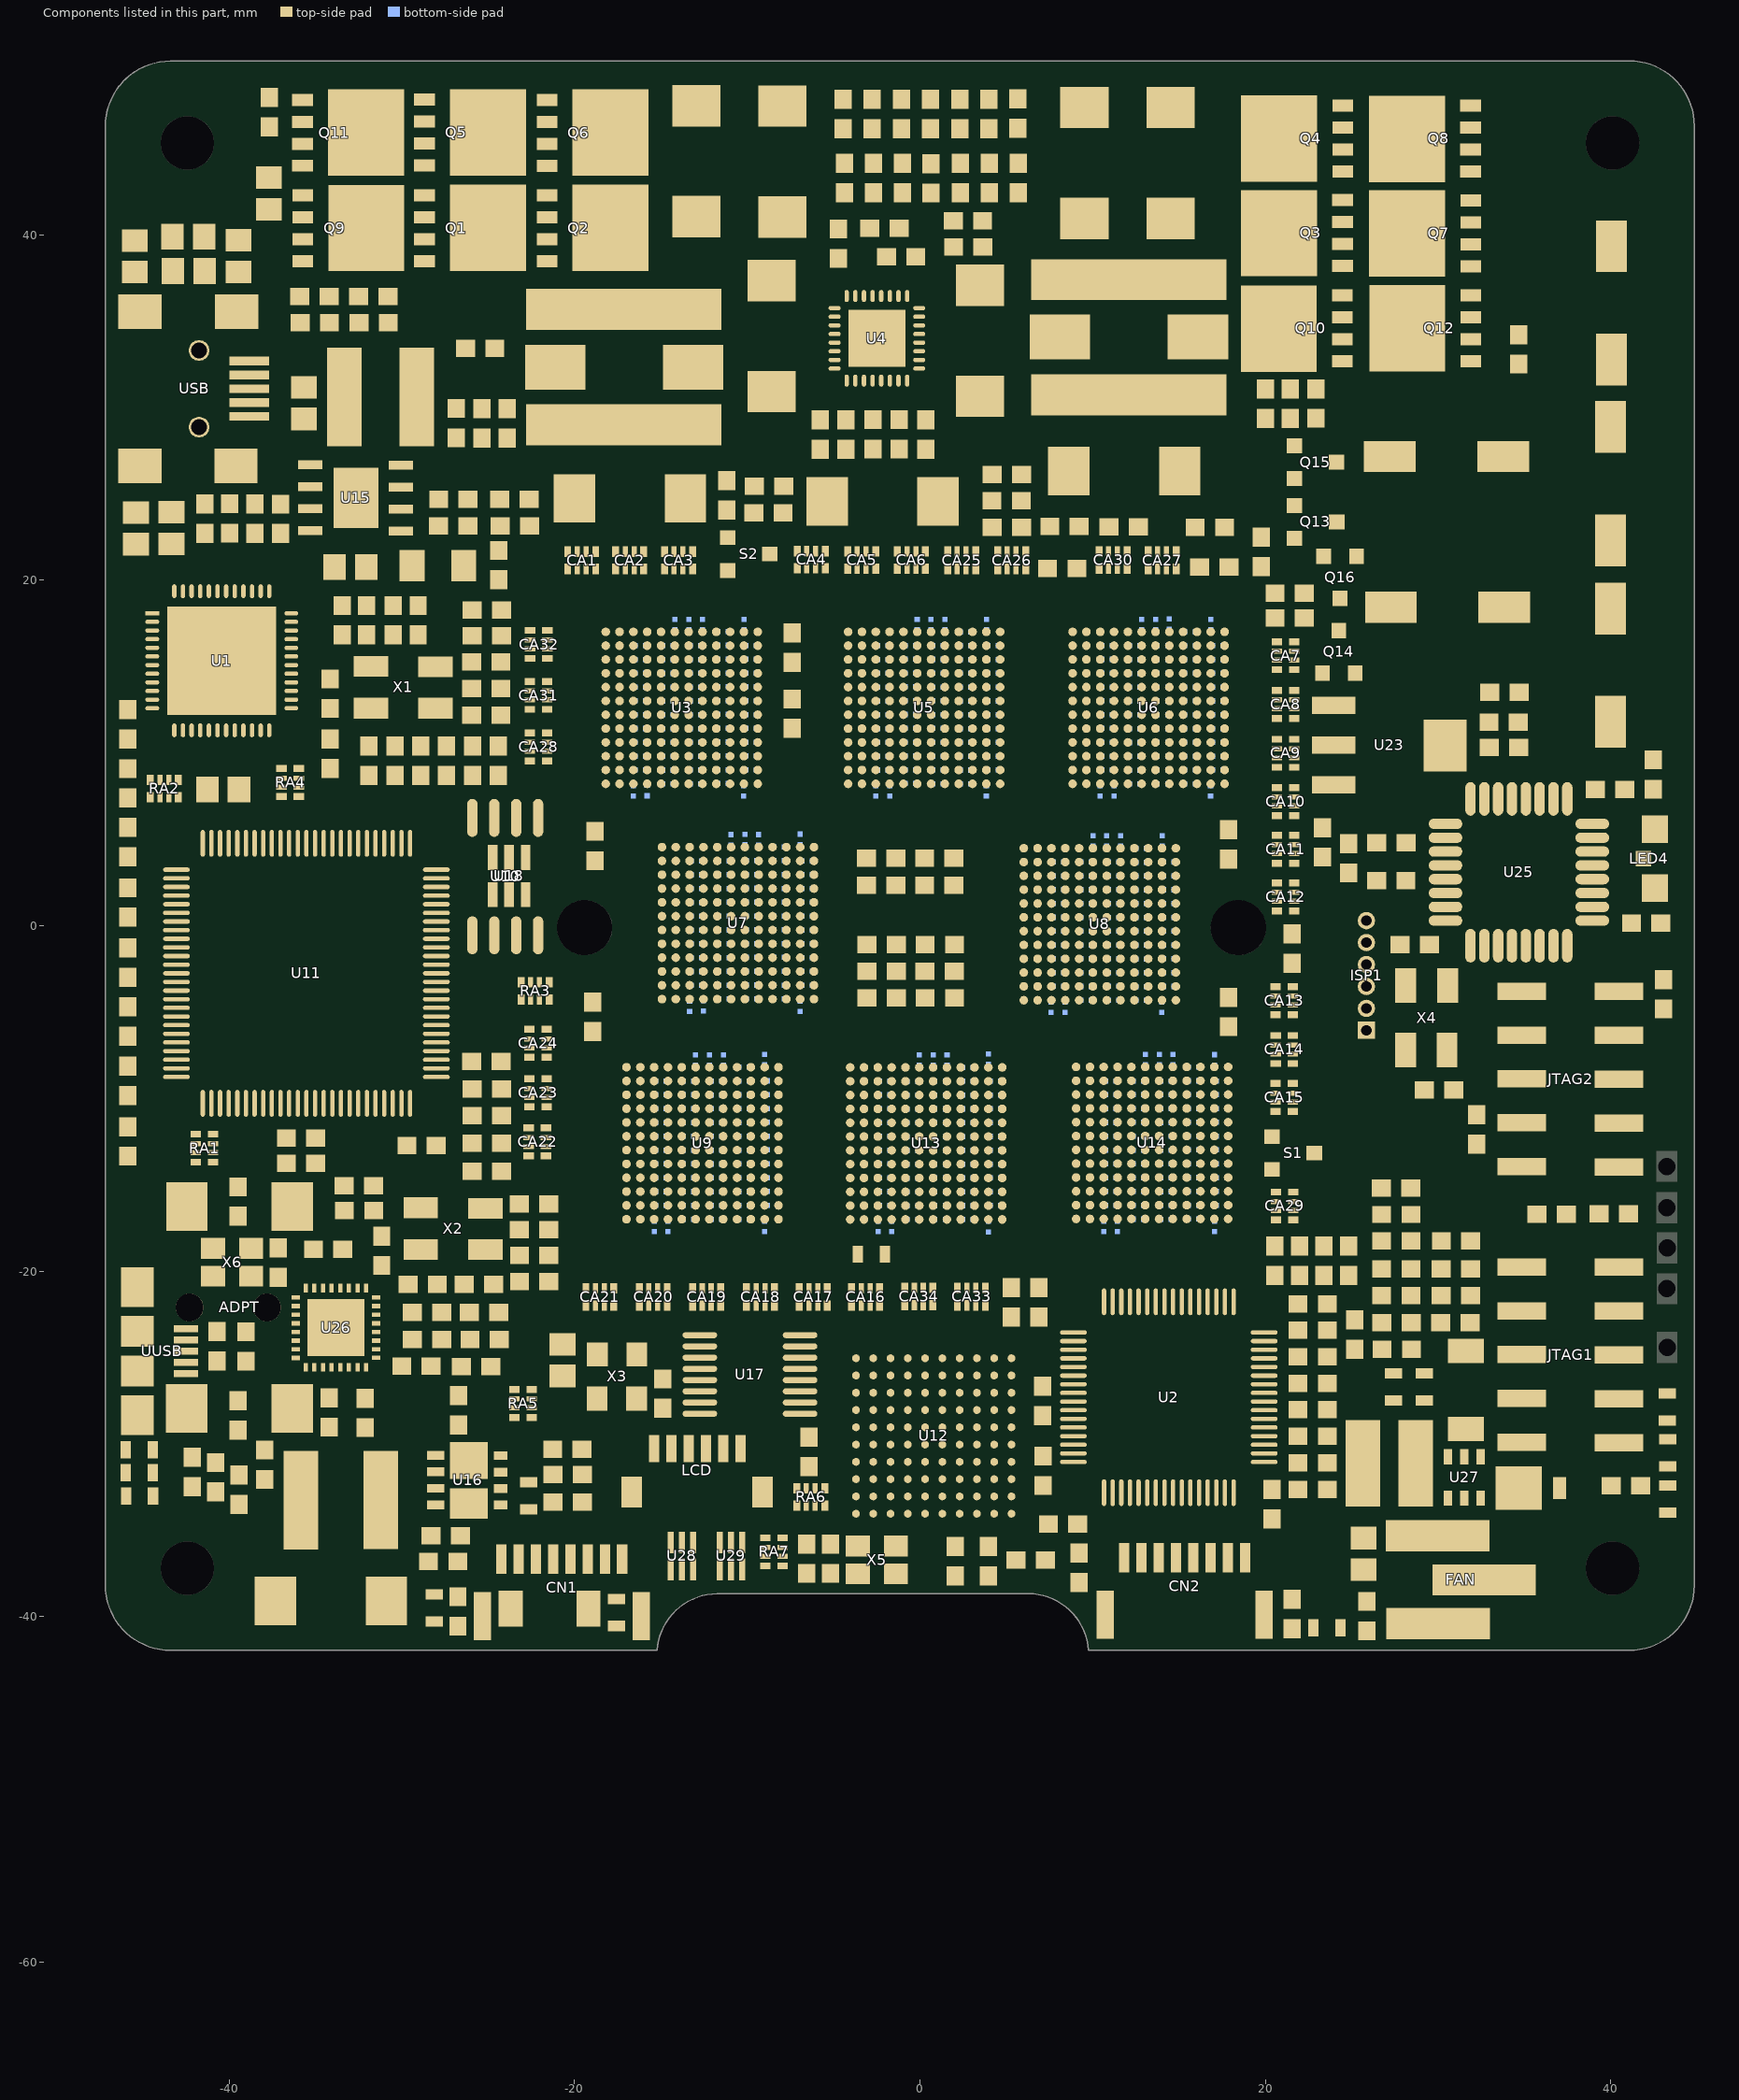
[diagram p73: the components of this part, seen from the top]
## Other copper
Top Layer:
  rectangle net V1.0REGSW: -25.65,-31.82 -23.87,-30.4
  rectangle net PWR_MAIN: -24.79,-32.86 -23.78,-32.27
  rectangle net VCC+5: -15.66,-35.65 -14.27,-34.39
  rectangle net VCC+5_FB: 42.8,-32.45 43.83,-31.05
  rectangle net VCC+5: 42.77,-29.77 43.83,-28.32
  rectangle net GND: -6.8,-32.27 -6.09,-31.37
  rectangle net GND: -7.32,-32.85 -5.34,-32.24
  rectangle net VCC_D: -1.5,23 2.43,26.17
  rectangle net GND: -6.57,23 -2.21,26.19
  rectangle net VCC_D: 8.55,19.52 9.58,20.35
  rectangle net PWR_MAIN: -41.89,-17.64 -40.47,-15.15
  rectangle net VCC_D: 19.39,8.76 20.324,16.79
  rectangle net VCC_D: -7.3,19.48 6.43,20.16
  rectangle net VCC_D: -20.7,19.6 -12.65,20.09
  rectangle net V3.3REGSW: -35.99,23.52 -34.6,24.28
  rectangle net VCC_D: -19.4,-20.6 -7.16,-19.8
  rectangle net VCC_D: 19.57,-11.16 20.156,-3.086
  rectangle net PWR_MAIN: -37.98,-15.04 -35.12,-14.64
  rectangle net GND: -44.1,-29.34 -43.65,-26.54
  rectangle net GND: -37.98,-29.33 -37.53,-26.53
  rectangle net PWR_MAIN: -37.99,-17.64 -37.54,-14.84
  rectangle net PWR_MAIN: -44.06,-17.65 -43.14,-14.84
  rectangle net GND: -28.91,-32.5 -27.91,-31.3
  rectangle net VCC_D: 7.39,38.63 16.47,43.22
  rectangle net GND: 1.59,35.48 5.4,38.47
  rectangle net GND: -10.73,35.91 -5.97,38.85
  rectangle net VCC_D: -14.83,39.63 -5.95,43.02
  rectangle net GND: -10.36,36.09 -7.16,38.7
  rectangle net GND: 7.47,44.42 16.55,49.01
  rectangle net GND: -14.82,44.55 -5.95,49.14
  rectangle net PWR_MAIN: 25.82,16.5 29.55,20.56
  rectangle net PWR_MAIN: 25.17,25.18 29.47,28.89
  rectangle net PWR_MAIN: 41.27,10.59 43.64,15.18
  rectangle net PWR_MAIN: 36.72,10.1 41.39,15.19
  rectangle net PWR_MAIN: 37.57,20.37 44.01,24.48
  rectangle net PWR_MAIN: 37.11,31.09 41.43,35.98
  rectangle net GND: 41.86,27.25 44.05,40.3
  rectangle net GND: 35.79,36.47 44.06,41.01
  rectangle net GND: 36.62,25.02 44.05,30.41
  rectangle net GND: 36.29,15.65 43.71,19.88
  rectangle net GND: 30.14,15.65 36.82,30.23
  rectangle net GND: -23.29,-3.57 -21.27,-2.345
  rectangle net VCC_D: 19.57,-17.25 20.89,-15.08
  rectangle net GND: -36.43,39.22 -34.62,42.89
  rectangle net GND: -22.28,39.29 -20.47,42.96
  rectangle net GND: -29.38,39.23 -27.57,42.9
  rectangle net ADP18502_SW1: -20.09,34.77 -15.68,42.9
  rectangle net VCC_D: -38.055,-40.885 -35.421,-36.743
  rectangle net GND: -33.456,-40.885 -29.69,-37.013
  rectangle net ADP18502_SW1: -22.28,44.77 -20.47,48.44
  rectangle net ADP18502_SW1: -29.37,44.81 -27.56,48.48
  rectangle net ADP18502_SW1: -36.42,44.79 -34.61,48.46
  rectangle net ADP18502_SW2: 6.35,29.55 9.86,32.85
  rectangle net VCC_D: 14.29,35.15 17.85,38.59
  rectangle net ADP18502_SW2: 23.4,43.06 25.21,46.7
  rectangle net GND: 30.77,43.05 32.58,46.72
  rectangle net GND: 30.79,37.58 32.6,41.25
  rectangle net ADP18502_SW2: 23.36,37.58 25.17,41.21
  rectangle net ADP18502_SW2: 23.34,32.08 25.15,35.75
  rectangle net GND: 30.79,32.08 32.6,35.75
  rectangle net ADP18502_SW2: 24.94,43.06 27.23,46.69
  rectangle net ADP18502_SW2: 24.85,37.58 27.14,41.21
  rectangle net ADP18502_SW2: 24.54,32.08 26.83,35.76
  rectangle net ADP18502_SW2: 26.03,42.03 30.44,43.48
  rectangle net ADP18502_SW2: 26.03,36.86 30.44,38.31
  rectangle net GND: 33.26,41.86 36.14,48.2
  rectangle net PWR_MAIN: 18.61,42.41 22.98,43.41
  rectangle net PWR_MAIN: 18.59,36.93 22.98,37.65
  rectangle net VCC_D: -21.96,-13.57 -20.99,-5.76
  region net VCC_D: 6.38,20.04 6.38,21.01 -7.29,21.01 -7.29,20.04
  region net VCC_D: -12.87,19.99 -12.87,20.96 -20.68,20.96 -20.68,19.99
  region net VCC_D: 21,16.72 20.03,16.72 20.03,0.67 21,0.67
  region net VCC_D: 20.95,-3.24 19.98,-3.24 19.98,-11.05 20.95,-11.05
  region net VCC_D: -19.58,-20.36 -19.58,-21.33 -2.06,-21.33 -2.06,-20.36
  region net GND: -1.16,-20.35 -1.16,-21.32 4.05,-21.32 4.05,-20.35
  rectangle net VCC_D: -21.88,9.28 -20.91,17.31
  rectangle net GND: -23.22,9.29 -22.25,17.31
  region net GND: -19.56,-21.67 -19.56,-22.64 -2.04,-22.64 -2.04,-21.67
  region net VCC+3.3: -1.15,-21.64 -1.15,-22.61 4.06,-22.61 4.06,-21.64
  rectangle net GND: -23.28,-13.56 -22.31,-5.75
  region net GND: -12.9,21.3 -12.9,22.23 -20.71,22.23 -20.71,21.3
  region net GND: 6.41,21.32 6.41,22.29 -7.26,22.29 -7.26,21.32
  region net GND: 10.069,22.3 10.069,21.33 15.11,21.33 15.11,22.3
  region net VCC_D: 10.08,21.03 10.08,20.06 15.12,20.06 15.12,21.03
  region net GND: 22.3,16.7 21.33,16.7 21.33,0.65 22.3,0.65
  region net GND: 22.26,-3.31 21.29,-3.31 21.29,-11.12 22.26,-11.12
  rectangle net GND: -39.99,28.54 -34.97,29.74
  rectangle net ADP18502_DL1: -22.19,37.17 -20.99,38.53
  rectangle net GND: -36.27,7.26 -35.19,9.33
  rectangle net GND: 21.31,-17.22 22.57,-15.21
  rectangle net USB_VBUS: -40,32.44 -37.36,33.57
  rectangle net GND: -43.91,37.15 -42.61,41.21
  rectangle net GND: -46.2,39.03 -44.71,41.86
  rectangle net GND: -40.24,39.04 -36.99,42.09
  rectangle net USB_VBUS: -29.3,19.94 -28.01,21.74
  rectangle net GND: -21.65,23.03 -18.17,26.53
  rectangle net GND: 13.25,24.56 19.5,28.39
  rectangle net VCC_D: 16.92,3.22 18.36,4.42
  rectangle net ADP18502_SW1: -34.26,37.46 -29.83,38.85
  rectangle net GND: -43.2,-26.92 -41.78,-25.8
  rectangle net PWR_MAIN: -43.98,-23.52 -43.26,-21.54
  rectangle net NetC153_1: 27.06,-26.63 27.83,-25.88
  rectangle net GND: -41,-22.74 -39.84,-21.98
  rectangle net GND: -3.633,-4.721 -2.501,4.469
  rectangle net GND: -0.237,-4.677 0.791,4.454
  region net NetC153_2: 27.92,-28.05 27.71,-28.26 27.09,-28.26 26.69,-28.66 24.64,-28.66 24.63,-28.67 24.63,-27.21 24.95,-26.92 27.69,-26.92 27.92,-27.15
  region net ADP18502_SW1: -20.88,36.88 -20.91,36.85 -22.8,36.85 -22.8,37.89 -23.36,38.45 -23.36,42.85 -23.39,42.88 -23.41,42.86 -27.24,42.86 -27.25,42.85 -27.21,42.81 -27.21,35.61 -26.09,34.49 -20.71,34.49
  region net ADP18502_SW1: -15.91,39.73 -13.01,36.86 -15.85,36.86 -15.9,36.91
  region net VCC_D: -15.01,22.98 -15.23,23.16 -16.7,23.16 -17.08,23.53 -17.08,25.05 -17.74,25.711 -17.74,27.92 -14.86,30.8 -14.86,33.06 -14.28,33.64 -8.59,33.64 -7.43,32.48 -7.14,32.19 -7.14,29.6 -7.16,29.6 -8.24,28.52 -10.15,28.52 -10.86,27.81 -11.52,27.81 -11.52,27.43 -12.01,26.92 -12.01,26.51 -12,23.24 -12.34,22.98
  region net ADP18502_SW1: -23.24,34.52 -23.24,31 -23.22,30.98 -19.39,30.98 -19.39,33.49 -18.24,34.64 -18.24,34.68
  region net VCC_D: 8.13,39.77 6.62,38.26 6.62,38.25 17.03,38.25 17.1,38.18 17.41,38.18 17.41,38.2 15.87,39.74 15.88,39.75 15.88,40.3 13.44,42.11 10.91,42.12 8.16,40.3 8.13,40.27
  region net VCC_D: 5.24,32.17 5.88,31.53 5.88,29.47 6.3,29.05 9.45,29.05 10.41,28.09 10.41,24.9 9.77,24.26 7.36,24.26 6.8,24.82 6.8,26.74 6.62,26.92 3.31,26.92 1.4,28.83 1.4,31.58 1.99,32.17
Mid-Layer 1:
  rectangle net VCC_D: 2.55,25.66 3.9,27.36
  rectangle net PWR_MAIN: -23.81,20.8 -21.39,22.57
  rectangle net PWR_MAIN: 17.86,32.65 22.88,44.39
  region net VCC+5: 27.42,-31.98 29.26,-31.98 29.69,-32.41 29.69,-33.98 27.41,-36.26 27.41,-37.8 27.37,-37.8 26.79,-38.38 25.05,-38.38 24.72,-38.05 24.72,-36.88 25.42,-36.18 26.23,-36.18 26.23,-35.27 27.01,-34.49 27.01,-32.39
  region net VCC_D: 3.4,26.05 3.29,26.16 -1.56,26.16 -1.91,25.81 -1.91,23.25 -1.27,22.61 3.09,22.61 4.17,23.69 4.17,23.83
Mid-Layer 2:
  rectangle net SC_CHIP_DONE3: 15.337,-6.718 16.481,-5.819
  rectangle net SC_CHIP_DONE5: 1.204,-23.475 1.815,-22.729
Mid-Layer 3:
  region net VCC_D: 3.22,26.11 -1.4,26.11 -1.87,25.64 -1.87,23.21 -1.2,22.54 3.02,22.54 3.95,23.47 3.95,23.56
Bottom Layer:
  rectangle net V1.0REGSW: -24.536,-39.636 -22.931,-38.375
  rectangle net SC_SPI_NCS: -16.009,-2.643 -15.769,-2.456
  rectangle net FT2232_A0: -37.402,6.825 -36.854,7.395
  rectangle net V1.0REGSW: -36.97,-34.319 -34.117,-30.492
  rectangle net VCC_D: 2.43,25.49 3.85,27.95
  rectangle net V1.0REGSW: -27.588,-32.11 -24.19,-29.998
  rectangle net GND: -4.53,31.9 -0.51,36.04
  region net NetC153_2: 25.16,-29.9 25.25,-29.99 30.12,-29.99 31,-30.87 31,-31.9 30.72,-32.18 25.21,-32.18 25.04,-32.01 25.04,-30.11 25.16,-29.99
  region net VCC_D: 3.62,26.23 -1.44,26.23 -1.88,25.79 -1.88,23.13 -1.33,22.58 3.12,22.58 4.27,23.73 4.27,23.82
  region net ADP18502_SW2: 25.42,37 23.69,37 23.4,37.29 23.4,40.89 23.73,41.23 24.8,41.23 25.04,41.47 25.04,42.29 25.42,42.65 30.51,42.65 30.53,42.67 30.53,38.03 31.02,37.54 31,37.52 31,36.86
  region net PWR_MAIN: 22.83,42.62 22.83,32.65 22.32,32.14 19.13,32.14 18.234,33.036 17.9,33.395 17.9,41.553 19.015,42.62
  region net VCC_D: -6.62,39.15 -10.79,39.15 -11.54,38.4 -11.54,34.26 -10.48,33.2 -7.21,33.2 -6.53,32.52 -6.53,29.585 -7.508,28.6 -9.65,28.6 -11.75,26.5 -11.75,23.38 -12.36,22.77 -16.58,22.77 -17.49,23.68 -17.49,35.62 -15.56,37.55 -15.56,42.23 -14.3,43.49 -6.82,43.49 -5.57,42.24 -5.57,40.2
  region net ADP18502_SW2: 6.8,31.7 7.64,32.54 18.12,32.54 18.87,31.79 22.62,31.79 23.24,32.41 23.24,35.51 23.51,35.77 25.131,35.781 25.41,36.06 25.41,37.122 25.886,37.61 30.24,37.62 31,36.86 31,35.53 30.71,35.24 30.71,29.46 29.87,28.62 26.12,28.62 24.99,27.49 17.38,27.49 16.53,28.34 7.51,28.34 6.809,29.041
PowerPlane2 (plane layer: these items are gaps in the copper):
  circle w0.5: c40.094,-37.18 r2.006
  circle w0.5: c40.1,45.32 r2.006
  circle w0.5: c-42.4,45.31 r2.006
  circle w0.5: c-42.41,-37.19 r2.006
  lines w0.2: -16.22,-35.85 -14.25,-37.82 -9.41,-37.82 -9.02,-37.43 22.47,-37.43 23.63,-38.59 28.15,-38.59 28.9,-37.84 28.9,-36.81 28.24,-36.15 27.78,-36.15 24.03,-36.15 -10.9,-36.15 -13.23,-33.82 -15.62,-33.82 -16.22,-34.42 -16.22,-35.85
  lines w0.25: 7.12,32.56 17.32,32.56 18.46,31.42 22.2,31.42 23.17,32.39 23.17,41.06 23.73,41.62 26.08,41.62 27.51,43.05 30.28,43.05 30.83,42.5 30.83,29.73 29.89,28.79 25.99,28.79 24.79,27.59 17.47,27.59 16.69,28.37 8.01,28.37 6.41,29.97 6.41,31.81 7.16,32.56 ; 11.91,25.31 11.91,28.37 ; -34.74,35.99 -34.74,40.2 -34.74,43.28 -34.63,43.39 -15.9,43.39 -15.9,36.58 -15.9,36.47 -16.38,35.99 -34.74,35.99
  lines w0.3: 11.91,25.31 13.03,24.19 16.39,24.19 19.02,24.19 20.99,22.22 20.99,17.75 20.99,-21.54 -13.54,-21.54 -21.92,-21.54 -22.39,-21.07 -22.39,-19.5 -22.39,-19.44 -22.39,21.51 -21.05,22.85 -18.46,22.85 -17.73,23.58 -17.73,34.57 -15.9,36.4 -15.9,41.9 -15.9,43.36 7.57,43.36 17.1,43.36 17.41,43.05 17.41,32.65 17.32,32.56 ; -42.66,-8.16 -42.66,-6.32 -41.63,-5.29 -41.63,1.44 -40.74,2.33 -40.14,2.93 -34.59,2.93 -32.15,0.49 -32.15,-7.75 -33.74,-9.34 -33.74,-11.61 -31.14,-14.21 -31.14,-16.93 -31.74,-17.53 -33.11,-17.53 -33.21,-17.43 -33.21,-15.49 -33.21,-14.29 -34.23,-13.27 -35.87,-13.27 -36.92,-12.22 -38.45,-12.22 -39.02,-11.65 -39.02,-9.59 -39.72,-8.89 -41.93,-8.89 -42.66,-8.16
GroundPlane (plane layer: these items are gaps in the copper):
  circle w0.5: c-42.416,-37.18 r2.006
  circle w0.5: c40.094,-37.18 r2.006
  circle w0.5: c40.094,45.32 r2.006
  circle w0.5: c-42.396,45.31 r2.006
  lines w0.15: -41.27,-14.97 -41.27,-14.54 -41.02,-14.29 -40.39,-14.29 -40.16,-14.52 -38.98,-14.52 -38.16,-13.7 -37.18,-12.72 -35.95,-12.72 -35.68,-12.45 -35.68,-11.16 -35.01,-10.49 -35.01,-9.23 -35.53,-8.71 -35.53,-8.31 -35.26,-8.04 -34.73,-8.04 -34.21,-8.56 -34.21,-12.85 -34.85,-13.49 -36.5,-13.49 -38.31,-15.3 -40.94,-15.3 -41.27,-14.97
  lines w0.25: 11.36,28.89 8.16,28.89 6.75,30.3 6.75,31.69 8.18,33.12 14.67,33.12 17.81,36.26 17.81,43.23 ; 11.43,28.9 27.34,28.9 29.89,31.45 30.61,32.17 30.61,43.12 30.13,43.6 26.47,43.6 26.1,43.23 20.45,43.23 17.81,43.23 ; 17.81,37.49 17.81,43.23
  lines w0.3: -6.62,28.45 -6.62,32.1 -7.79,33.27 -7.79,35.08 -6.43,36.44 -6.43,38.95 -5.67,39.71 -5.67,41.27 -5.67,42.96 -6.24,43.53 -6.24,45.6 -5.57,46.27 -5.57,48.33 -5.05,48.85 -4.99,48.91 6.26,48.91 6.43,48.74 6.43,40.19 4.82,38.58 1.66,38.58 1.18,38.1 1.18,36.53 1.74,35.97 1.74,27.33 0.79,26.38 -5.69,26.38
PowerPlane1 (plane layer: these items are gaps in the copper):
  lines w0.2: -17.37,-34.74 -17.37,-30.5 -16.73,-29.86 -15.06,-29.86 -14.35,-30.57 -14.35,-33.31 -13.17,-34.49 -13.17,-35.8 -12.42,-36.55 -12.42,-37.81 -14.3,-37.81 -17.37,-34.74
  lines w0.25: -17.06,23.89 -17.06,36.41 -15.87,37.6 -15.87,42.78 -15.31,43.34 -15.28,43.34 -6.81,43.34 -5.67,42.2 -5.67,39.87 -6.47,39.07 -10.33,39.07 -10.9,38.5 -10.9,34.6 -9.15,32.85 -7.57,32.85 -6.47,31.75 -6.47,29.86 -7.32,29.01 -9.41,29.01 -11.93,26.49 -11.93,23.47 -12.63,22.77 -14.92,22.77 -15.29,23.14 -16.31,23.14 -17.06,23.89
  lines w0.3: 1.79,-36.53 0.14,-36.53 -0.57,-35.82 -0.57,-33.7 -2.38,-31.89 -2.38,-26.72 -1.3,-25.64 2.21,-25.64 3.87,-27.3 3.87,-32.84 5.76,-34.73 5.76,-36.08 5.32,-36.52 3.38,-36.52 ; 6.28,-29.06 6.28,-29.63 10.05,-33.4 10.05,-34.39 10.81,-35.15 18.48,-35.15 19.45,-34.18 19.45,-22.95 18.1,-21.6 8.73,-21.6 7.04,-23.29 ; 6.3,-27.26 6.3,-24.73 7.04,-23.99 7.04,-23.29 ; 7.04,-23.34 7.04,-23.29 ; -38.85,-40.21 -38.11,-40.95 -30.03,-40.95 -29.52,-40.44 -29.52,-36 -29.21,-35.69 -29.21,-30.35 -28.89,-30.03 -26.68,-30.03 -25.71,-29.06 -25.71,-27.48 -24.94,-26.71 -23.91,-26.71 -19.13,-21.93 -7.79,-21.93 -7.65,-21.79 -7.65,-19.67 -7.72,-19.6 -19.63,-19.6 -20.32,-18.91 -20.32,-11.22 -20.59,-10.95 -23.29,-10.95 -23.71,-11.37 -23.71,-15.75 -34.39,-26.43 -38.85,-30.89 -38.85,-40.21
SecondaryGND (plane layer: these items are gaps in the copper):
  circle w0.5: c-42.424,-37.149 r2.006
  circle w0.5: c40.086,-37.149 r2.006
  circle w0.5: c40.086,45.351 r2.006
  circle w0.5: c-42.404,45.341 r2.006
  lines w0.25: 11.336,29.007 6.589,29.007 6.272,29.324 6.272,32.809 6.7,33.237 14.646,33.237 17.786,36.377 17.786,43.298 18.205,43.717 20.796,43.717 25.787,43.717 30.106,43.717 30.586,43.237 30.586,32.287 29.866,31.567 27.316,29.017 11.406,29.017
  lines w0.3: -6.595,29.175 -6.595,31.803 -7.765,32.973 -7.765,35.081 -6.405,36.441 -6.405,38.951 -5.645,39.711 -5.645,41.271 -5.645,42.431 -6.215,43.001 -6.215,45.601 -5.545,46.271 -5.545,47.94 -4.574,48.911 5.405,48.911 6.455,47.861 6.455,40.191 4.845,38.581 1.685,38.581 1.205,38.101 1.205,36.531 1.56,36.176 1.56,27.126 0.815,26.381 -4.601,26.381

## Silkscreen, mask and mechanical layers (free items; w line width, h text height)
Top Overlay:
  drawing of 1812 lines, arcs and shapes, not listed
  text "Butterfly Labs" at -46.238,55.819 h4
  text "Revision E" at 22.376,51.901 h4.5
  text "BitFORCE SC 1.0" at -46.932,51.365 h6
  text "Max Temp. 83C" at 35.35,35.08 h1.3 r90
  text "HIPTFJSJ" at -30.8,28.12 h1.2 r90
  text "A" at 16.89,25.3 h4
  text "Simulator" at 31.83,2.83 h1.2
  text "E54CDC75C4FAC2DF" at -41.22,-0.6 h1.3
  text "4E331F259A87532A" at -41.22,-2.378 h1.3
  text "DD70F05D18D66FC9" at -41.22,-4.156 h1.3
  text "F936F7AA40EC99D8" at -41.22,-5.934 h1.3
  text "BitFORCE SC  Rev. C" at 24.59,-8.18 h1.2 r90
  text "BUTTERFLYLABS" at 23.53,-8.2 h1.5 r90
  text "OBTTFS" at 37.27,-9.786 h1.2 r90
  text "B" at -33.3,-14.04 h4
  text "MAIN" at 44.839,-14.855 h1.2 r90
  text "12V" at -46.86,-16.14 h1.5
  text "5V" at 44.838,-16.779 h1.2 r90
  text "DC" at -46.35,-17.23 h1.5
  text "3.3V" at 44.838,-19.616 h1.2 r90
  text "1.0V" at 44.838,-22.31 h1.2 r90
  text "GND" at 44.838,-25.908 h1.2 r90
  text "ARM" at 12.53,-27.35 h2
  text "HIPTFJSJ" at 27.527,-33.67 h1.2 r90
  text "CHAIN-OUT" at 11.81,-35.39 h1.3
  text "CHAIN-IN" at -23.59,-35.575 h1.3
  text "YLW" at 33.15,-35.73 h1.5
  text "RED" at 27.13,-38.3 h1.5
  text "BLK" at 33.28,-40.87 h1.5
  text "By Nasser GHOSEIRI - Jan 2013" at 30.139,-43.279 h1
  text "Corrected R70" at 34.106,-45.859 h1.5
  text "Added RA7, RA6, U28, U29, U27, L9, C159, C153, D4, C154, R79, R80,C151" at -41.705,-46.283 h1.5
  text "Corrected TempSensors nets" at 34.106,-47.139 h1.5
  text "Added R81, R82" at -41.635,-47.523 h1.5
  text "Changed engines from normal QFN to BGA144" at 34.106,-48.449 h1.5
  text "Removed U24" at -41.625,-48.813 h1.5
  text "Revision C" at 14.981,-49.523 h3.5
  text "Changed values of R60 to R63" at 34.106,-49.74 h1.5
  text "Changed values of R60 to R63" at 34.106,-49.74 h1.5
  text "C104 changed package from 1206 to 0603" at -41.675,-50.033 h1.5
  text "Revision B3" at -62.825,-50.393 h3.5
  text "D2 was removed" at 34.106,-50.956 h1.5
  text "R47 and R48 values in the BOM changed" at -41.635,-51.303 h1.5
  text "L6 Was changed" at 34.106,-52.265 h1.5
  text "ISP1 Header part number corrected to: GRPB061VWVN-RC" at -41.635,-52.483 h1.5
  text "R83 was added" at 34.106,-53.524 h1.5
  text "L6 changed to VLC5045T-3R3N" at -41.575,-53.733 h1.52
  text "BGA Pad sizes changed from 0.45mm to 0.5mm" at 33.959,-57.159 h1.5
  text "R80 changed from 16K to 9.53K" at -41.585,-57.203 h1.5
  text "R48 Pin 1 was NOT connected to ground" at -41.515,-58.483 h1.5
  text "BitFORCE SC Chips pinout corrected" at 33.927,-58.547 h1.5
  text "Revision C.4" at 11.327,-60.333 h3.5
  text "Revision B4" at -62.965,-60.363 h3.5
